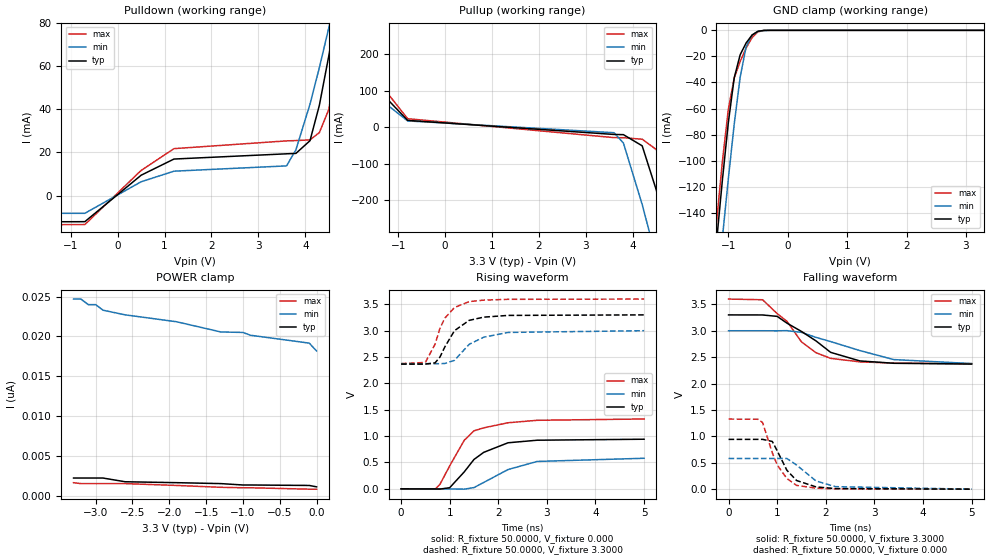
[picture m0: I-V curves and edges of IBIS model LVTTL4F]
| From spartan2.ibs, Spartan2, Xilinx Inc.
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|   Model LVTTL4F
[Model]   LVTTL4F
Model_type   I/O
Polarity   Non-Inverting
Enable   Active-Low
Vinl =   0.800V
Vinh =   2.000V
Vmeas =   1.4000V
Cref =  35.0000pF
Rref =   1.0000M
Vref =  0.000V
C_comp   6.5000pF   5.0000pF   8.0000pF
[Temperature Range]   27.0000   100.0000   0.000
[Voltage Range]   3.3000V   3.0000V   3.6000V
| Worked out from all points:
|   slope of the pulldown table from 0 to 0.495 V, typ, clamps not added: 52.7 ohm
|   slope of the pullup table from 0 to 0.495 V, typ, clamps not added: 72 ohm
|   GND clamp passes 1 mA (typ) near -0.51 V on its own axis
|   rising waveform, R_fixture 50.0000, V_fixture 0.000: 20-80 % time 649ps typ, 853ps min, 538ps max; typ from 0 V to 0.941 V
|   rising waveform, R_fixture 50.0000, V_fixture 3.3000: 20-80 % time 419ps typ, 526ps min, 353ps max; typ from 2.37 V to 3.3 V
|   falling waveform, R_fixture 50.0000, V_fixture 3.3000: 20-80 % time 914ps typ, 1.33ns min, 768ps max; typ from 3.3 V to 2.37 V
|   falling waveform, R_fixture 50.0000, V_fixture 0.000: 20-80 % time 386ps typ, 512ps min, 365ps max; typ from 0.943 V to 0.001 V
[Pulldown]
| voltage   I(typ)   I(min)   I(max)
-3.3V     -12.23mA   -8.171mA   -13.61mA
-700mV    -12.05mA   -8.171mA   -13.39mA
500mV     9.467mA    6.427mA    11.68mA
1.2V      16.95mA    11.33mA    21.76mA
3.6V      19.37mA    13.78mA    25.36mA
3.8V      19.56mA    21.23mA    25.5mA
4.1V      25.44mA    42.35mA    25.81mA
4.3V      41.86mA    59.27mA    29.21mA
4.5V      64.6mA     77.61mA    39.82mA
4.7V      89.71mA    97.03mA    64.96mA
4.9V      116.1mA    117.3mA    95.67mA
6.6V      348mA      295mA      376.7mA
[Pullup]
| voltage   I(typ)   I(min)   I(max)
-3.3V     354.4mA    271.9mA    429.9mA
-2.7V     272.8mA    207.8mA    331mA
-800mV    18.43mA    17.03mA    23.04mA
3.6V      -19.96mA   -15.22mA   -28.65mA
3.8V      -20.52mA   -43.41mA   -28.84mA
4.2V      -51mA      -211.2mA   -32.92mA
4.5V      -171.4mA   -357.8mA   -61.08mA
4.7V      -272mA     -457.9mA   -116mA
4.9V      -376.2mA   -559mA     -210.3mA
5.1V      -482.2mA   -660.7mA   -313.6mA
5.3V      -589.2mA   -762.8mA   -420.3mA
6.6V      -1.293A    -1.432A    -1.133A
[GND_clamp]
| voltage   I(typ)   I(min)   I(max)
-3.3V     -1.286A    -1.273A    -1.289A
-1.2V     -163.3mA   -206.7mA   -148.3mA
-1.1V     -115.2mA   -159.6mA   -101mA
-1V       -71.04mA   -114.2mA   -60.78mA
-900mV    -36.42mA   -71.86mA   -36.53mA
-800mV    -18.72mA   -35.86mA   -23.84mA
-700mV    -9.715mA   -12.62mA   -13.63mA
-600mV    -3.608mA   -3.649mA   -5.601mA
-500mV    -692.7uA   -854.2uA   -1.156mA
-400mV    -68.48uA   -138.7uA   -98.51uA
-300mV    -4.365uA   -16.73uA   -4.597uA
3.3V      1.164nA    19.44nA    698.5pA
[POWER_clamp]
| voltage   I(typ)   I(min)   I(max)
-3.3V     2.212nA    24.68nA    1.63nA
-3.2V     2.212nA    24.68nA    1.513nA
-3.1V     2.212nA    23.98nA    1.513nA
-3V       2.212nA    23.98nA    1.513nA
-2.9V     2.212nA    23.28nA    1.513nA
-2.6V     1.746nA    22.7nA     1.513nA
-1.9V     1.63nA     21.83nA    1.281nA
-1.3V     1.513nA    20.55nA    1.048nA
-1V       1.339nA    20.49nA    989.5pA
-900mV    1.339nA    20.14nA    989.5pA
-100mV    1.281nA    19.15nA    814.9pA
0V        1.106nA    18.16nA    814.9pA
[Ramp]
| variable   typ   min   max
dV/dt_r   0.5647/0.6500n   0.3480/0.8497n   0.7950/0.5579n
dV/dt_f   0.5586/0.9517n   0.3726/1.3252n   0.7338/0.7688n
R_load = 50.0000
[Rising Waveform]
R_fixture = 50.0000
V_fixture = 0.000
| time   V(typ)   V(min)   V(max)
0s        0V         0V         0V
700ps     -2.021mV   226.2uV    -4.415mV
800ps     -4.588mV   188uV      85.45mV
1ns       21.52mV    -1.672mV   434.2mV
1.3ns     321.5mV    -6.047mV   921.4mV
1.5ns     557.2mV    23.94mV    1.1V
1.7ns     692mV      121.2mV    1.157V
2.2ns     873.5mV    365.6mV    1.253V
2.8ns     922.2mV    519.7mV    1.3V
5ns       941.2mV    580mV      1.325V
[Rising Waveform]
R_fixture = 50.0000
V_fixture = 3.3000
V_fixture_min = 3.0000
V_fixture_max = 3.6000
| time   V(typ)   V(min)   V(max)
0s        2.365V     2.374V     2.375V
500ps     2.365V     2.374V     2.397V
700ps     2.39V      2.374V     2.744V
800ps     2.499V     2.374V     3.043V
900ps     2.691V     2.377V     3.237V
1.1ns     3V         2.437V     3.439V
1.4ns     3.195V     2.74V      3.551V
1.7ns     3.256V     2.876V     3.579V
2.2ns     3.289V     2.966V     3.594V
5ns       3.299V     2.999V     3.599V
[Falling Waveform]
R_fixture = 50.0000
V_fixture = 3.3000
V_fixture_min = 3.0000
V_fixture_max = 3.6000
| time   V(typ)   V(min)   V(max)
0s        3.3V       3V         3.6V
700ps     3.299V     3V         3.587V
1ns       3.272V     2.999V     3.325V
1.2ns     3.145V     3.002V     3.18V
1.5ns     2.987V     2.97V      2.789V
1.8ns     2.807V     2.874V     2.584V
2.1ns     2.591V     2.795V     2.477V
2.7ns     2.429V     2.625V     2.411V
3.4ns     2.384V     2.454V     2.388V
5ns       2.369V     2.379V     2.377V
[Falling Waveform]
R_fixture = 50.0000
V_fixture = 0.000
| time   V(typ)   V(min)   V(max)
0s        943.3mV    581.6mV    1.327V
600ps     943.4mV    581.6mV    1.325V
700ps     943.7mV    581.6mV    1.262V
900ps     903.3mV    581.6mV    689.3mV
1ns       728.3mV    581.8mV    460.1mV
1.2ns     357.9mV    581.3mV    201.4mV
1.4ns     164mV      456.6mV    71.6mV
1.8ns     43.47mV    155.2mV    18.74mV
2.2ns     11.27mV    47.74mV    7.191mV
5ns       636.3uV    446.4uV    717.8uV
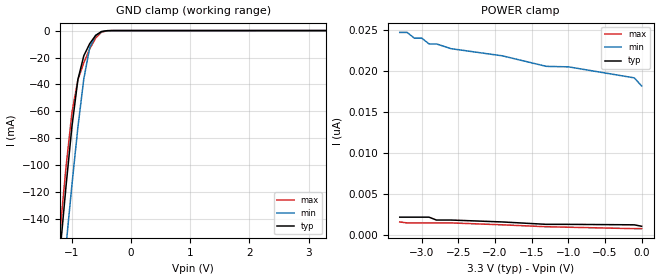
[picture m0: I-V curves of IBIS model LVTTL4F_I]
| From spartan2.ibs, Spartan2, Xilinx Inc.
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|   Model LVTTL4F_I
[Model]   LVTTL4F_I
Model_type   Input
Polarity   Non-Inverting
Vinl =   0.800V
Vinh =   2.000V
C_comp   6.5000pF   5.0000pF   8.0000pF
[Temperature Range]   27.0000   100.0000   0.000
[Voltage Range]   3.3000V   3.0000V   3.6000V
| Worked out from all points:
|   GND clamp passes 1 mA (typ) near -0.51 V on its own axis
[GND_clamp]
| voltage   I(typ)   I(min)   I(max)
-3.3V     -1.286A    -1.273A    -1.289A
-1.2V     -163.3mA   -206.7mA   -148.3mA
-1.1V     -115.2mA   -159.6mA   -101mA
-1V       -71.04mA   -114.2mA   -60.78mA
-900mV    -36.42mA   -71.86mA   -36.53mA
-800mV    -18.72mA   -35.86mA   -23.84mA
-700mV    -9.715mA   -12.62mA   -13.63mA
-600mV    -3.608mA   -3.649mA   -5.601mA
-500mV    -692.7uA   -854.2uA   -1.156mA
-400mV    -68.48uA   -138.7uA   -98.51uA
-300mV    -4.365uA   -16.73uA   -4.597uA
3.3V      1.164nA    19.44nA    698.5pA
[POWER_clamp]
| voltage   I(typ)   I(min)   I(max)
-3.3V     2.212nA    24.68nA    1.63nA
-3.2V     2.212nA    24.68nA    1.513nA
-3.1V     2.212nA    23.98nA    1.513nA
-3V       2.212nA    23.98nA    1.513nA
-2.9V     2.212nA    23.28nA    1.513nA
-2.8V     1.863nA    23.28nA    1.513nA
-2.6V     1.863nA    22.7nA     1.513nA
-1.9V     1.63nA     21.83nA    1.281nA
-1.3V     1.339nA    20.55nA    1.048nA
-1V       1.339nA    20.49nA    989.5pA
-100mV    1.281nA    19.15nA    814.9pA
0V        1.106nA    18.16nA    814.9pA
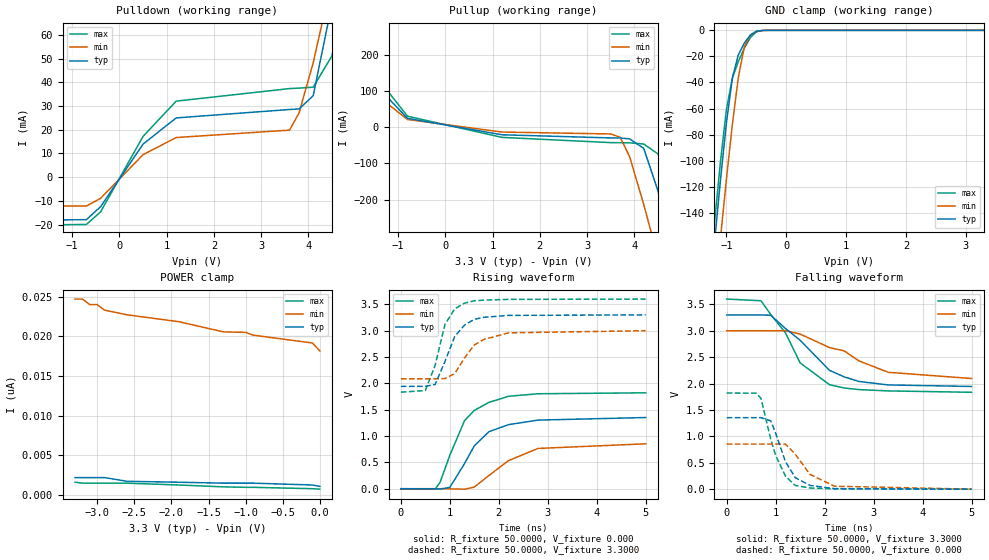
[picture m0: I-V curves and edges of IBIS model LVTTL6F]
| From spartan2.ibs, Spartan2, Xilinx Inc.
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|   Model LVTTL6F
[Model]   LVTTL6F
Model_type   I/O
Polarity   Non-Inverting
Enable   Active-Low
Vinl =   0.800V
Vinh =   2.000V
Vmeas =   1.4000V
Cref =  35.0000pF
Rref =   1.0000M
Vref =  0.000V
C_comp   6.5000pF   5.0000pF   8.0000pF
[Temperature Range]   27.0000   100.0000   0.000
[Voltage Range]   3.3000V   3.0000V   3.6000V
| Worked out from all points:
|   slope of the pulldown table from 0 to 0.495 V, typ, clamps not added: 35.8 ohm
|   slope of the pullup table from 0 to 0.495 V, typ, clamps not added: 48 ohm
|   GND clamp passes 1 mA (typ) near -0.51 V on its own axis
|   rising waveform, R_fixture 50.0000, V_fixture 0.000: 20-80 % time 637ps typ, 848ps min, 572ps max; typ from 0 V to 1.35 V
|   rising waveform, R_fixture 50.0000, V_fixture 3.3000: 20-80 % time 381ps typ, 505ps min, 322ps max; typ from 1.94 V to 3.3 V
|   falling waveform, R_fixture 50.0000, V_fixture 3.3000: 20-80 % time 938ps typ, 1.32ns min, 791ps max; typ from 3.3 V to 1.95 V
|   falling waveform, R_fixture 50.0000, V_fixture 0.000: 20-80 % time 371ps typ, 475ps min, 357ps max; typ from 1.35 V to 0.001 V
[Pulldown]
| voltage   I(typ)   I(min)   I(max)
-3.3V     -18.29mA   -12.15mA   -20.46mA
-700mV    -17.9mA    -12.15mA   -19.91mA
-400mV    -12.43mA   -8.91mA    -14.62mA
500mV     13.96mA    9.497mA    17.21mA
1.2V      24.98mA    16.71mA    32.05mA
3.6V      28.53mA    19.84mA    37.34mA
3.8V      28.75mA    27.06mA    37.54mA
4.1V      34.3mA     48.19mA    37.92mA
4.5V      73.34mA    83.53mA    51.22mA
4.7V      98.49mA    103mA      76.31mA
4.9V      124.9mA    123.2mA    107.1mA
6.6V      356.8mA    300.9mA    388.1mA
[Pullup]
| voltage   I(typ)   I(min)   I(max)
-3.3V     367mA      281.8mA    444.6mA
-2.7V     284.5mA    216.8mA    344.6mA
-800mV    24.26mA    21.1mA     30.17mA
1.2V      -21.09mA   -13.54mA   -28.27mA
3.5V      -29.77mA   -18.84mA   -42.7mA
3.7V      -29.99mA   -27.95mA   -43mA
3.9V      -32.42mA   -80.94mA   -43.28mA
4.2V      -58.74mA   -213.5mA   -46.66mA
4.5V      -175.5mA   -359.9mA   -73.69mA
4.9V      -379.7mA   -561mA     -216mA
5.1V      -485.7mA   -662.7mA   -318.8mA
6.6V      -1.296A    -1.434A    -1.138A
[GND_clamp]
| voltage   I(typ)   I(min)   I(max)
-3.3V     -1.286A    -1.273A    -1.289A
-1.2V     -163.3mA   -206.7mA   -148.3mA
-1.1V     -115.2mA   -159.6mA   -101mA
-1V       -71.04mA   -114.2mA   -60.78mA
-900mV    -36.42mA   -71.86mA   -36.53mA
-800mV    -18.72mA   -35.86mA   -23.84mA
-700mV    -9.715mA   -12.62mA   -13.63mA
-600mV    -3.608mA   -3.649mA   -5.601mA
-500mV    -692.7uA   -854.2uA   -1.156mA
-400mV    -68.48uA   -138.7uA   -98.51uA
-300mV    -4.365uA   -16.73uA   -4.597uA
3.3V      1.106nA    19.38nA    756.7pA
[POWER_clamp]
| voltage   I(typ)   I(min)   I(max)
-3.3V     2.212nA    24.68nA    1.63nA
-3.2V     2.212nA    24.68nA    1.513nA
-3.1V     2.212nA    23.98nA    1.513nA
-3V       2.212nA    23.98nA    1.513nA
-2.9V     2.212nA    23.28nA    1.513nA
-2.6V     1.746nA    22.7nA     1.513nA
-1.9V     1.63nA     21.83nA    1.281nA
-1.3V     1.513nA    20.55nA    1.048nA
-1V       1.513nA    20.49nA    989.5pA
-900mV    1.513nA    20.14nA    989.5pA
-100mV    1.281nA    19.15nA    814.9pA
0V        1.106nA    18.16nA    756.7pA
[Ramp]
| variable   typ   min   max
dV/dt_r   0.8106/0.6383n   0.5113/0.8456n   1.0920/0.5977n
dV/dt_f   0.8130/0.9718n   0.5424/1.3196n   1.0590/0.7913n
R_load = 50.0000
[Rising Waveform]
R_fixture = 50.0000
V_fixture = 0.000
| time   V(typ)   V(min)   V(max)
0s        0V         0V         0V
700ps     -2.548mV   477.9uV    -7.13mV
800ps     -6.399mV   465uV      119.4mV
1ns       24.33mV    -2.208mV   634mV
1.3ns     476.9mV    -8.459mV   1.291V
1.5ns     813.5mV    30.35mV    1.486V
1.8ns     1.083V     252.1mV    1.639V
2.2ns     1.216V     533.5mV    1.754V
2.8ns     1.302V     764.5mV    1.802V
5ns       1.351V     852.1mV    1.82V
[Rising Waveform]
R_fixture = 50.0000
V_fixture = 3.3000
V_fixture_min = 3.0000
V_fixture_max = 3.6000
| time   V(typ)   V(min)   V(max)
0s        1.942V     2.086V     1.832V
500ps     1.943V     2.086V     1.863V
700ps     1.978V     2.086V     2.342V
900ps     2.413V     2.09V      3.116V
1.1ns     2.889V     2.184V     3.413V
1.3ns     3.104V     2.481V     3.522V
1.5ns     3.216V     2.728V     3.566V
1.7ns     3.253V     2.835V     3.579V
2.2ns     3.289V     2.958V     3.593V
5ns       3.299V     2.999V     3.599V
[Falling Waveform]
R_fixture = 50.0000
V_fixture = 3.3000
V_fixture_min = 3.0000
V_fixture_max = 3.6000
| time   V(typ)   V(min)   V(max)
0s        3.3V       3V         3.6V
700ps     3.299V     3V         3.568V
900ps     3.293V     3V         3.307V
1.2ns     3.043V     3.002V     2.962V
1.5ns     2.82V      2.937V     2.392V
2.1ns     2.25V      2.681V     1.978V
2.4ns     2.127V     2.619V     1.916V
2.7ns     2.04V      2.43V      1.886V
3.3ns     1.974V     2.213V     1.861V
5ns       1.945V     2.096V     1.835V
[Falling Waveform]
R_fixture = 50.0000
V_fixture = 0.000
| time   V(typ)   V(min)   V(max)
0s        1.354V     854.4mV    1.821V
600ps     1.354V     854.3mV    1.818V
700ps     1.354V     854.4mV    1.722V
900ps     1.294V     854.4mV    943.9mV
1ns       1.06V      854.6mV    638.2mV
1.2ns     521.9mV    853.2mV    247.6mV
1.4ns     219.7mV    664.2mV    70.24mV
1.7ns     71.28mV    280.8mV    22.14mV
2.2ns     10.91mV    56.52mV    6.667mV
5ns       677.6uV    604.3uV    703.3uV
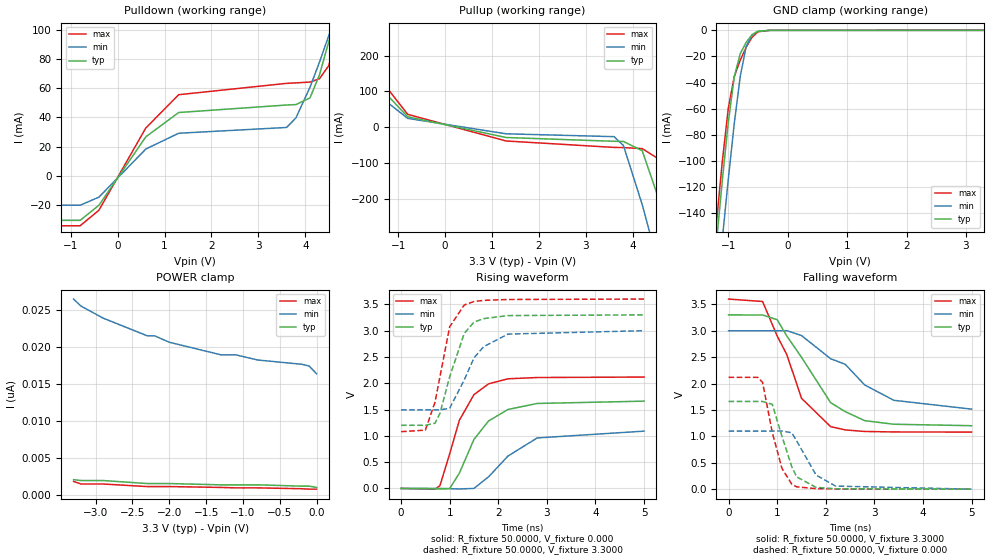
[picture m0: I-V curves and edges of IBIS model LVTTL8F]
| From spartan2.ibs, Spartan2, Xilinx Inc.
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|   Model LVTTL8F
[Model]   LVTTL8F
Model_type   I/O
Polarity   Non-Inverting
Enable   Active-Low
Vinl =   0.800V
Vinh =   2.000V
Vmeas =   1.4000V
Cref =  35.0000pF
Rref =   1.0000M
Vref =  0.000V
C_comp   6.5000pF   5.0000pF   8.0000pF
[Temperature Range]   27.0000   100.0000   0.000
[Voltage Range]   3.3000V   3.0000V   3.6000V
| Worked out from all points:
|   slope of the pulldown table from 0 to 0.495 V, typ, clamps not added: 21.7 ohm
|   slope of the pullup table from 0 to 0.495 V, typ, clamps not added: 37.4 ohm
|   GND clamp passes 1 mA (typ) near -0.51 V on its own axis
|   rising waveform, R_fixture 50.0000, V_fixture 0.000: 20-80 % time 658ps typ, 816ps min, 496ps max; typ from 0 V to 1.66 V
|   rising waveform, R_fixture 50.0000, V_fixture 3.3000: 20-80 % time 405ps typ, 509ps min, 328ps max; typ from 1.2 V to 3.3 V
|   falling waveform, R_fixture 50.0000, V_fixture 3.3000: 20-80 % time 910ps typ, 1.33ns min, 701ps max; typ from 3.3 V to 1.2 V
|   falling waveform, R_fixture 50.0000, V_fixture 0.000: 20-80 % time 338ps typ, 441ps min, 314ps max; typ from 1.66 V to 0.001 V
[Pulldown]
| voltage   I(typ)   I(min)   I(max)
-3.3V     -30.59mA   -20.24mA   -34.35mA
-800mV    -30.59mA   -20.24mA   -34.32mA
-400mV    -20.27mA   -14.69mA   -23.66mA
600mV     26.67mA    18.3mA     32.74mA
1.3V      43.34mA    29.13mA    55.56mA
3.6V      48.49mA    33.09mA    63.34mA
3.8V      48.79mA    39.63mA    63.67mA
4.1V      53.36mA    60.68mA    64.22mA
4.3V      68.97mA    77.68mA    66.46mA
4.5V      91.81mA    96.06mA    75.48mA
4.7V      116.9mA    115.5mA    100.2mA
6.6V      374.6mA    313mA      411.1mA
[Pullup]
| voltage   I(typ)   I(min)   I(max)
-3.3V     377.1mA    289.5mA    456.1mA
-2.5V     265.1mA    201.1mA    320.9mA
-800mV    29.02mA    24.47mA    35.82mA
1.3V      -28.95mA   -18.62mA   -38.67mA
3.6V      -39.57mA   -26.6mA    -56.67mA
3.8V      -40.06mA   -51.24mA   -57.06mA
4.2V      -65.76mA   -216.1mA   -59.97mA
4.5V      -180mA     -362.3mA   -84.67mA
4.7V      -279.7mA   -462.3mA   -131.8mA
4.9V      -383.6mA   -563.4mA   -223.1mA
5.1V      -489.5mA   -665.1mA   -325mA
6.6V      -1.3A      -1.437A    -1.143A
[GND_clamp]
| voltage   I(typ)   I(min)   I(max)
-3.3V     -1.286A    -1.273A    -1.29A
-1.3V     -213.2mA   -255.1mA   -198mA
-1.2V     -163mA     -206.8mA   -147.7mA
-1.1V     -114.8mA   -159.6mA   -100.3mA
-1V       -70.57mA   -114.1mA   -59.86mA
-900mV    -35.79mA   -71.75mA   -35.46mA
-800mV    -18.04mA   -35.69mA   -22.98mA
-700mV    -9.256mA   -12.38mA   -13.06mA
-600mV    -3.388mA   -3.468mA   -5.299mA
-500mV    -637.4uA   -792.4uA   -1.07mA
-300mV    -3.973uA   -15.32uA   -4.185uA
3.3V      1.048nA    17.64nA    698.5pA
[POWER_clamp]
| voltage   I(typ)   I(min)   I(max)
-3.3V     2.095nA    26.43nA    1.863nA
-3.2V     1.979nA    25.49nA    1.513nA
-2.9V     1.979nA    23.87nA    1.513nA
-2.3V     1.572nA    21.48nA    1.164nA
-2.2V     1.572nA    21.48nA    1.164nA
-2V       1.572nA    20.61nA    1.164nA
-1.3V     1.397nA    18.92nA    1.048nA
-1.1V     1.397nA    18.92nA    989.5pA
-800mV    1.397nA    18.22nA    989.5pA
-200mV    1.222nA    17.64nA    873.1pA
-100mV    1.222nA    17.4nA     814.9pA
0V        1.048nA    16.36nA    814.9pA
[Ramp]
| variable   typ   min   max
dV/dt_r   0.9954/0.6562n   0.6534/0.8177n   1.2702/0.5188n
dV/dt_f   1.2588/0.9349n   0.8904/1.3360n   1.5114/0.7027n
R_load = 50.0000
[Rising Waveform]
R_fixture = 50.0000
V_fixture = 0.000
| time   V(typ)   V(min)   V(max)
0s        0V         0V         0V
700ps     -3.523mV   474.9uV    -13.49mV
800ps     -8.549mV   441.1uV    53.62mV
1ns       -3.398mV   -3.191mV   657.2mV
1.2ns     291.8mV    -10.29mV   1.297V
1.5ns     932.3mV    594.8uV    1.783V
1.8ns     1.282V     220.5mV    1.988V
2.2ns     1.501V     616.2mV    2.084V
2.8ns     1.615V     959.9mV    2.108V
5ns       1.659V     1.089V     2.117V
[Rising Waveform]
R_fixture = 50.0000
V_fixture = 3.3000
V_fixture_min = 3.0000
V_fixture_max = 3.6000
| time   V(typ)   V(min)   V(max)
0s        1.2V       1.493V     1.079V
500ps     1.2V       1.493V     1.108V
700ps     1.24V      1.493V     1.645V
800ps     1.426V     1.493V     2.122V
1ns       2.122V     1.524V     3.072V
1.3ns     2.947V     2.061V     3.487V
1.5ns     3.161V     2.481V     3.553V
1.7ns     3.227V     2.695V     3.574V
2.2ns     3.285V     2.933V     3.591V
5ns       3.299V     2.998V     3.599V
[Falling Waveform]
R_fixture = 50.0000
V_fixture = 3.3000
V_fixture_min = 3.0000
V_fixture_max = 3.6000
| time   V(typ)   V(min)   V(max)
0s        3.3V       3V         3.6V
700ps     3.299V     3V         3.554V
1ns       3.209V     2.999V     2.901V
1.2ns     2.898V     3.002V     2.546V
1.5ns     2.499V     2.91V      1.722V
2.1ns     1.639V     2.47V      1.184V
2.4ns     1.469V     2.365V     1.123V
2.8ns     1.298V     1.974V     1.093V
3.4ns     1.23V      1.683V     1.084V
5ns       1.202V     1.516V     1.081V
[Falling Waveform]
R_fixture = 50.0000
V_fixture = 0.000
| time   V(typ)   V(min)   V(max)
0s        1.661V     1.1V       2.118V
600ps     1.661V     1.1V       2.118V
700ps     1.661V     1.1V       2.023V
900ps     1.606V     1.1V       1.072V
1.1ns     997.6mV    1.101V     390.8mV
1.3ns     427mV      1.07V      97.05mV
1.4ns     233.5mV    915.8mV    44.14mV
1.8ns     34.79mV    268.1mV    11.02mV
2.2ns     7.949mV    58.66mV    4.811mV
5ns       542.7uV    608.4uV    549.4uV
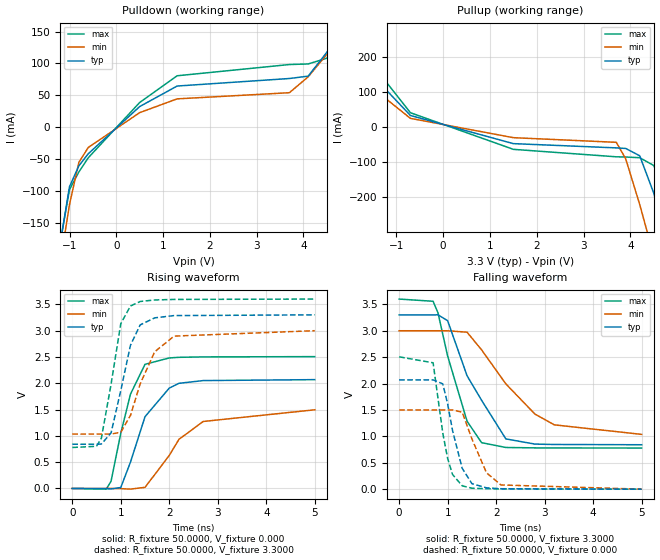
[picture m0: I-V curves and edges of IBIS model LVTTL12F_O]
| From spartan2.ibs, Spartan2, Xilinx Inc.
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|   Model LVTTL12F_O
[Model]   LVTTL12F_O
Model_type   Output
Polarity   Non-Inverting
Vmeas =   1.4000V
Cref =  35.0000pF
Rref =   1.0000M
Vref =  0.000V
C_comp   6.5000pF   5.0000pF   8.0000pF
[Temperature Range]   27.0000   100.0000   0.000
[Voltage Range]   3.3000V   3.0000V   3.6000V
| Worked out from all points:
|   slope of the pulldown table from 0 to 0.495 V, typ, clamps not added: 15.4 ohm
|   slope of the pullup table from 0 to 0.495 V, typ, clamps not added: 25.2 ohm
|   rising waveform, R_fixture 50.0000, V_fixture 0.000: 20-80 % time 556ps typ, 797ps min, 400ps max; typ from 0 V to 2.07 V
|   rising waveform, R_fixture 50.0000, V_fixture 3.3000: 20-80 % time 372ps typ, 492ps min, 288ps max; typ from 0.84 V to 3.3 V
|   falling waveform, R_fixture 50.0000, V_fixture 3.3000: 20-80 % time 727ps typ, 1.07ns min, 508ps max; typ from 3.3 V to 0.841 V
|   falling waveform, R_fixture 50.0000, V_fixture 0.000: 20-80 % time 305ps typ, 397ps min, 266ps max; typ from 2.07 V to 0 V
[Pulldown]
| voltage   I(typ)   I(min)   I(max)
-3.3V     -1.282A    -1.27A     -1.284A
-1.5V     -318.7mA   -354mA     -306.2mA
-1V       -93.5mA    -121.5mA   -98.07mA
-800mV    -60.84mA   -55.35mA   -70.38mA
-600mV    -41.86mA   -32.01mA   -48.2mA
500mV     32.35mA    22.81mA    38.75mA
1.3V      64.57mA    44.42mA    80.71mA
3.7V      76.41mA    54.11mA    98.37mA
4.1V      80.11mA    79.08mA    99.25mA
4.5V      117.6mA    114.4mA    108.3mA
4.9V      168.6mA    153.8mA    162.6mA
6.6V      399mA      330.4mA    441.4mA
[Pullup]
| voltage   I(typ)   I(min)   I(max)
-3.3V     401.3mA    308.2mA    484mA
-2.9V     344.8mA    263.9mA    415.5mA
-2.5V     286.5mA    217.5mA    345.7mA
-700mV    33.24mA    24.98mA    41.08mA
1.5V      -47.01mA   -30.01mA   -63.27mA
3.7V      -59.11mA   -43.28mA   -84.54mA
3.9V      -60.68mA   -90.11mA   -85.1mA
4.2V      -81.62mA   -220.4mA   -87.14mA
4.5V      -188mA     -366.4mA   -109.3mA
4.9V      -390.3mA   -567.4mA   -234.7mA
5.1V      -496.1mA   -669.1mA   -335.2mA
6.6V      -1.307A    -1.441A    -1.153A
[Ramp]
| variable   typ   min   max
dV/dt_r   1.2408/0.5535n   0.8970/0.7922n   1.5030/0.3954n
dV/dt_f   1.4752/0.7257n   1.1772/1.1183n   1.6925/0.5243n
R_load = 50.0000
[Rising Waveform]
R_fixture = 50.0000
V_fixture = 0.000
| time   V(typ)   V(min)   V(max)
0s        0V         0V         0V
700ps     -3.771mV   692.4uV    -13.4mV
800ps     -9.635mV   799.2uV    138.3mV
1ns       17.96mV    -3.585mV   1.048V
1.2ns     500.5mV    -12.31mV   1.792V
1.5ns     1.364V     21.02mV    2.359V
2ns       1.907V     627.7mV    2.48V
2.2ns     1.998V     933.5mV    2.492V
2.7ns     2.05V      1.273V     2.5V
5ns       2.068V     1.495V     2.505V
[Rising Waveform]
R_fixture = 50.0000
V_fixture = 3.3000
V_fixture_min = 3.0000
V_fixture_max = 3.6000
| time   V(typ)   V(min)   V(max)
0s        840.3mV    1.034V     778.4mV
500ps     841.4mV    1.034V     801.3mV
600ps     844.4mV    1.034V     955.5mV
800ps     1.055V     1.034V     1.98V
1ns       1.861V     1.067V     3.131V
1.2ns     2.721V     1.388V     3.467V
1.4ns     3.108V     1.987V     3.553V
1.7ns     3.242V     2.598V     3.582V
2.1ns     3.285V     2.895V     3.592V
5ns       3.299V     2.998V     3.599V
[Falling Waveform]
R_fixture = 50.0000
V_fixture = 3.3000
V_fixture_min = 3.0000
V_fixture_max = 3.6000
| time   V(typ)   V(min)   V(max)
0s        3.3V       3V         3.6V
700ps     3.299V     3V         3.558V
800ps     3.303V     3V         3.341V
1ns       3.19V      2.999V     2.521V
1.4ns     2.149V     2.973V     1.288V
1.7ns     1.683V     2.638V     880.4mV
2.2ns     952.2mV    1.994V     789.8mV
2.8ns     853.7mV    1.422V     782.3mV
3.2ns     846.6mV    1.218V     780.9mV
5ns       841.4mV    1.038V     779.2mV
[Falling Waveform]
R_fixture = 50.0000
V_fixture = 0.000
| time   V(typ)   V(min)   V(max)
0s        2.07V      1.5V       2.506V
700ps     2.07V      1.5V       2.393V
900ps     1.994V     1.5V       1.06V
1ns       1.615V     1.5V       581mV
1.1ns     1.113V     1.501V     280.2mV
1.3ns     395.3mV    1.458V     63.91mV
1.5ns     105.3mV    953.5mV    17.9mV
1.8ns     26.06mV    311.6mV    8.619mV
2.1ns     8.631mV    80.09mV    4.709mV
5ns       466uV      547.1uV    485uV
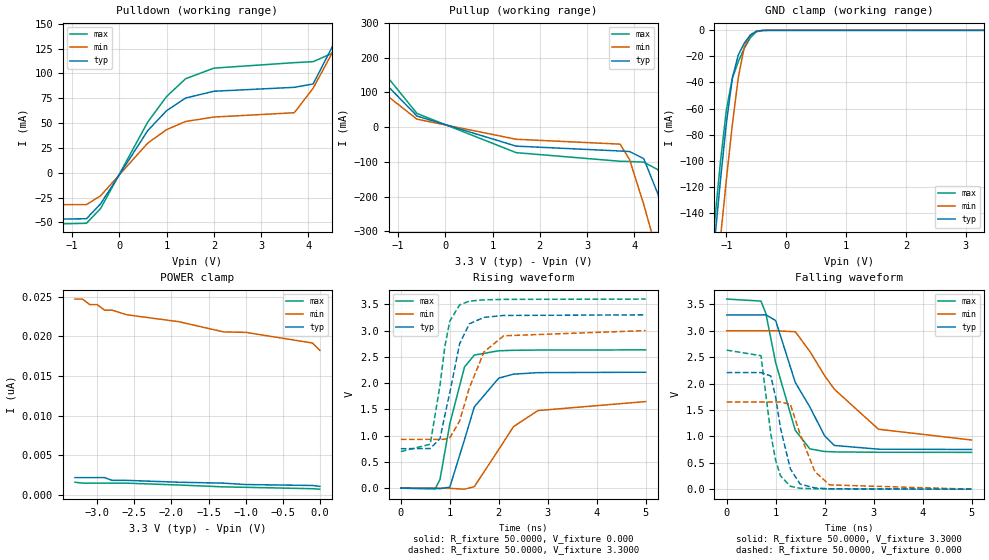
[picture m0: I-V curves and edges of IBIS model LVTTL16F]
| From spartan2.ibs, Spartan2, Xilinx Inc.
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|   Model LVTTL16F
[Model]   LVTTL16F
Model_type   I/O
Polarity   Non-Inverting
Enable   Active-Low
Vinl =   0.800V
Vinh =   2.000V
Vmeas =   1.4000V
Cref =  35.0000pF
Rref =   1.0000M
Vref =  0.000V
C_comp   6.5000pF   5.0000pF   8.0000pF
[Temperature Range]   27.0000   100.0000   0.000
[Voltage Range]   3.3000V   3.0000V   3.6000V
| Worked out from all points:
|   slope of the pulldown table from 0 to 0.495 V, typ, clamps not added: 13.7 ohm
|   slope of the pullup table from 0 to 0.495 V, typ, clamps not added: 21.7 ohm
|   GND clamp passes 1 mA (typ) near -0.51 V on its own axis
|   rising waveform, R_fixture 50.0000, V_fixture 0.000: 20-80 % time 500ps typ, 772ps min, 357ps max; typ from 0 V to 2.21 V
|   rising waveform, R_fixture 50.0000, V_fixture 3.3000: 20-80 % time 348ps typ, 474ps min, 266ps max; typ from 0.751 V to 3.3 V
|   falling waveform, R_fixture 50.0000, V_fixture 3.3000: 20-80 % time 696ps typ, 1.06ns min, 490ps max; typ from 3.3 V to 0.752 V
|   falling waveform, R_fixture 50.0000, V_fixture 0.000: 20-80 % time 289ps typ, 392ps min, 245ps max; typ from 2.21 V to 0 V
[Pulldown]
| voltage   I(typ)   I(min)   I(max)
-3.3V     -48.03mA   -32.17mA   -53.62mA
-700mV    -46.38mA   -32.17mA   -50.97mA
-400mV    -31.4mA    -23.23mA   -36.15mA
600mV     42.55mA    29.94mA    51.16mA
1V        62.63mA    43.47mA    76.94mA
1.4V      75.27mA    51.64mA    94.7mA
2V        82.09mA    56.09mA    105.4mA
3.7V      86.04mA    60.44mA    110.9mA
4.1V      89.48mA    85.22mA    111.9mA
4.5V      126.6mA    120.5mA    120.3mA
4.9V      177.6mA    159.9mA    174.2mA
6.6V      407.8mA    336.3mA    452.6mA
[Pullup]
| voltage   I(typ)   I(min)   I(max)
-3.3V     413.8mA    317.9mA    498.5mA
-2.9V     356.6mA    273mA      429.3mA
-2.5V     297.6mA    226.1mA    358.6mA
-600mV    31.98mA    22.96mA    39.44mA
1.5V      -54.66mA   -34.94mA   -73.46mA
3.7V      -68.75mA   -48.9mA    -98.25mA
3.9V      -70.27mA   -93.43mA   -98.9mA
4.2V      -90.62mA   -222.7mA   -100.8mA
4.5V      -192.3mA   -368.3mA   -122.6mA
4.9V      -393.7mA   -569.2mA   -241mA
5.1V      -499.3mA   -670.9mA   -340.5mA
6.6V      -1.31A     -1.442A    -1.157A
[GND_clamp]
| voltage   I(typ)   I(min)   I(max)
-3.3V     -1.286A    -1.273A    -1.289A
-1.2V     -163.3mA   -206.7mA   -148.3mA
-1.1V     -115.2mA   -159.6mA   -101mA
-1V       -71.04mA   -114.2mA   -60.78mA
-900mV    -36.42mA   -71.86mA   -36.53mA
-800mV    -18.72mA   -35.86mA   -23.84mA
-700mV    -9.715mA   -12.62mA   -13.63mA
-600mV    -3.608mA   -3.649mA   -5.602mA
-500mV    -692.7uA   -854.2uA   -1.156mA
-400mV    -68.48uA   -138.7uA   -98.54uA
-300mV    -4.365uA   -16.73uA   -4.627uA
3.3V      1.106nA    19.38nA    40.4nA
[POWER_clamp]
| voltage   I(typ)   I(min)   I(max)
-3.3V     2.212nA    24.68nA    1.63nA
-3.2V     2.212nA    24.68nA    1.513nA
-3.1V     2.212nA    23.98nA    1.513nA
-3V       2.212nA    23.98nA    1.513nA
-2.9V     2.212nA    23.28nA    1.513nA
-2.8V     1.863nA    23.28nA    1.513nA
-2.6V     1.863nA    22.7nA     1.513nA
-1.9V     1.63nA     21.83nA    1.281nA
-1.3V     1.513nA    20.55nA    1.048nA
-1V       1.339nA    20.49nA    989.5pA
-100mV    1.222nA    19.15nA    814.9pA
0V        1.106nA    18.22nA    756.7pA
[Ramp]
| variable   typ   min   max
dV/dt_r   1.3242/0.4985n   0.9888/0.7729n   1.5792/0.3516n
dV/dt_f   1.5287/0.6938n   1.2413/1.0975n   1.7416/0.4965n
R_load = 50.0000
[Rising Waveform]
R_fixture = 50.0000
V_fixture = 0.000
| time   V(typ)   V(min)   V(max)
0s        0V         0V         0V
700ps     -3.795mV   862.2uV    -13.55mV
800ps     -9.498mV   979.2uV    167.9mV
1ns       20.18mV    -3.712mV   1.226V
1.3ns     923.5mV    -18.43mV   2.307V
1.5ns     1.546V     29.14mV    2.533V
2ns       2.095V     737.9mV    2.615V
2.3ns     2.17V      1.171V     2.624V
2.8ns     2.199V     1.477V     2.629V
5ns       2.207V     1.648V     2.632V
[Rising Waveform]
R_fixture = 50.0000
V_fixture = 3.3000
V_fixture_min = 3.0000
V_fixture_max = 3.6000
| time   V(typ)   V(min)   V(max)
0s        751.2mV    928.2mV    696.8mV
600ps     755.2mV    928.8mV    836.4mV
800ps     943.5mV    928.5mV    1.963V
900ps     1.393V     932.2mV    2.704V
1ns       1.821V     959.1mV    3.179V
1.2ns     2.748V     1.276V     3.488V
1.4ns     3.129V     1.913V     3.56V
1.7ns     3.251V     2.595V     3.584V
2.1ns     3.287V     2.9V       3.593V
5ns       3.299V     2.999V     3.599V
[Falling Waveform]
R_fixture = 50.0000
V_fixture = 3.3000
V_fixture_min = 3.0000
V_fixture_max = 3.6000
| time   V(typ)   V(min)   V(max)
0s        3.3V       3V         3.6V
700ps     3.299V     3V         3.562V
800ps     3.303V     3V         3.329V
1ns       3.193V     2.999V     2.395V
1.4ns     2.023V     2.981V     1.116V
1.7ns     1.554V     2.608V     761.8mV
2ns       1.01V      2.148V     714.3mV
2.2ns     828.5mV    1.892V     706mV
3.1ns     757.3mV    1.135V     699.1mV
5ns       752.1mV    931.2mV    697.4mV
[Falling Waveform]
R_fixture = 50.0000
V_fixture = 0.000
| time   V(typ)   V(min)   V(max)
0s        2.208V     1.651V     2.633V
700ps     2.208V     1.651V     2.528V
900ps     2.144V     1.65V      1.05V
1ns       1.74V      1.651V     545.6mV
1.1ns     1.151V     1.651V     251.9mV
1.3ns     385.6mV    1.607V     55.11mV
1.5ns     96.7mV     1.042V     16.4mV
1.8ns     23.75mV    334.2mV    8.086mV
2.1ns     8.195mV    81.18mV    4.432mV
5ns       477.8uV    527.6uV    435.5uV
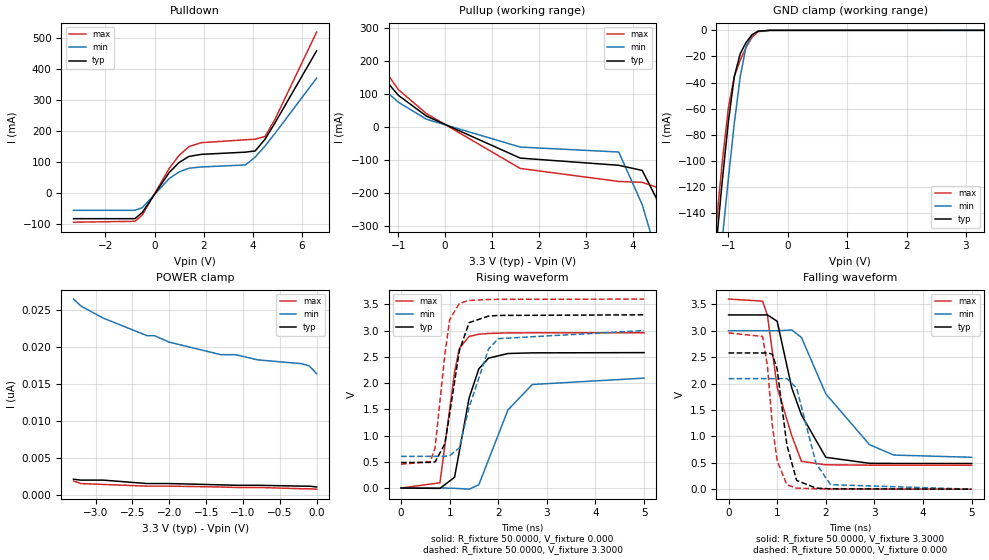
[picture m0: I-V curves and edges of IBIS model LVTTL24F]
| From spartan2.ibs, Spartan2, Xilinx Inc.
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|   Model LVTTL24F
[Model]   LVTTL24F
Model_type   I/O
Polarity   Non-Inverting
Enable   Active-Low
Vinl =   0.800V
Vinh =   2.000V
Vmeas =   1.4000V
Cref =  35.0000pF
Rref =   1.0000M
Vref =  0.000V
C_comp   6.5000pF   5.0000pF   8.0000pF
[Temperature Range]   27.0000   100.0000   0.000
[Voltage Range]   3.3000V   3.0000V   3.6000V
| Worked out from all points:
|   slope of the pulldown table from 0 to 0.495 V, typ, clamps not added: 8.65 ohm
|   slope of the pullup table from 0 to 0.495 V, typ, clamps not added: 13.4 ohm
|   GND clamp passes 1 mA (typ) near -0.51 V on its own axis
|   rising waveform, R_fixture 50.0000, V_fixture 0.000: 20-80 % time 335ps typ, 609ps min, 264ps max; typ from 0 V to 2.58 V
|   rising waveform, R_fixture 50.0000, V_fixture 3.3000: 20-80 % time 297ps typ, 440ps min, 225ps max; typ from 0.486 V to 3.3 V
|   falling waveform, R_fixture 50.0000, V_fixture 3.3000: 20-80 % time 618ps typ, 1.04ns min, 425ps max; typ from 3.3 V to 0.486 V
|   falling waveform, R_fixture 50.0000, V_fixture 0.000: 20-80 % time 251ps typ, 371ps min, 198ps max; typ from 2.58 V to 0 V
[Pulldown]
| voltage   I(typ)   I(min)   I(max)
-3.3V     -81.51mA   -54.57mA   -92.84mA
-800mV    -81.51mA   -54.57mA   -90.02mA
-500mV    -61.52mA   -46.16mA   -69.96mA
600mV     67.49mA    47.78mA    80.85mA
1V        99.44mA    69.02mA    122.2mA
1.4V      118.8mA    80.89mA    150.5mA
1.9V      125.5mA    84.94mA    163mA
3.7V      132.6mA    91.36mA    172.5mA
4.1V      136.6mA    116.8mA    174.3mA
4.5V      174.4mA    152.6mA    183.2mA
4.9V      226mA      192.5mA    237.8mA
6.6V      458.7mA    370.8mA    519.1mA
[Pullup]
| voltage   I(typ)   I(min)   I(max)
-3.3V     469.9mA    361.3mA    563.1mA
-2.7V     378.5mA    289.2mA    453mA
-2.3V     314.1mA    238.4mA    376.6mA
-1V       96.63mA    75.68mA    113.8mA
-400mV    33.52mA    23.96mA    40.98mA
1.6V      -93.78mA   -60.33mA   -125.1mA
3.7V      -115.5mA   -75.41mA   -164.4mA
4.2V      -131.1mA   -234.2mA   -167.2mA
4.5V      -214.4mA   -378.8mA   -181.5mA
4.9V      -410.7mA   -579.3mA   -274.3mA
5.1V      -515.8mA   -681mA     -367.8mA
6.6V      -1.327A    -1.453A    -1.18A
[GND_clamp]
| voltage   I(typ)   I(min)   I(max)
-3.3V     -1.286A    -1.273A    -1.29A
-1.3V     -213.2mA   -255.1mA   -198mA
-1.2V     -163mA     -206.8mA   -147.7mA
-1.1V     -114.8mA   -159.6mA   -100.3mA
-1V       -70.57mA   -114.1mA   -59.86mA
-900mV    -35.79mA   -71.75mA   -35.46mA
-800mV    -18.04mA   -35.69mA   -22.98mA
-700mV    -9.256mA   -12.38mA   -13.06mA
-600mV    -3.388mA   -3.468mA   -5.299mA
-500mV    -637.4uA   -792.4uA   -1.07mA
-300mV    -3.973uA   -15.32uA   -4.185uA
3.3V      1.048nA    17.64nA    698.5pA
[POWER_clamp]
| voltage   I(typ)   I(min)   I(max)
-3.3V     2.095nA    26.43nA    1.863nA
-3.2V     1.979nA    25.49nA    1.513nA
-2.9V     1.979nA    23.87nA    1.397nA
-2.3V     1.513nA    21.48nA    1.164nA
-2.2V     1.513nA    21.48nA    1.164nA
-2V       1.513nA    20.61nA    1.164nA
-1.3V     1.339nA    18.92nA    1.048nA
-1.1V     1.281nA    18.92nA    989.5pA
-800mV    1.281nA    18.22nA    989.5pA
-200mV    1.164nA    17.7nA     814.9pA
-100mV    1.164nA    17.4nA     814.9pA
0V        1.048nA    16.36nA    756.7pA
[Ramp]
| variable   typ   min   max
dV/dt_r   1.5474/0.3574n   1.2558/0.6149n   1.7748/0.2495n
dV/dt_f   1.6883/0.6190n   1.4376/1.0661n   1.8878/0.4204n
R_load = 50.0000
[Rising Waveform]
R_fixture = 50.0000
V_fixture = 0.000
| time   V(typ)   V(min)   V(max)
0s        0V         0V         0V
800ps     -7.133mV   1.143mV    99.13mV
1.1ns     203.7mV    -6.078mV   2.199V
1.2ns     701.5mV    -11.02mV   2.66V
1.4ns     1.714V     -22.03mV   2.887V
1.6ns     2.269V     61.66mV    2.929V
1.8ns     2.474V     538.2mV    2.944V
2.2ns     2.562V     1.488V     2.954V
2.7ns     2.574V     1.972V     2.956V
5ns       2.579V     2.093V     2.958V
[Rising Waveform]
R_fixture = 50.0000
V_fixture = 3.3000
V_fixture_min = 3.0000
V_fixture_max = 3.6000
| time   V(typ)   V(min)   V(max)
0s        485.6mV    602.6mV    453.2mV
600ps     487.9mV    603.1mV    500.7mV
700ps     496.1mV    603.4mV    766.4mV
900ps     838.8mV    604.8mV    2.534V
1ns       1.417V     615.9mV    3.208V
1.2ns     2.618V     765.3mV    3.518V
1.4ns     3.15V      1.537V     3.572V
1.8ns     3.275V     2.649V     3.591V
2ns       3.287V     2.845V     3.594V
5ns       3.299V     2.999V     3.599V
[Falling Waveform]
R_fixture = 50.0000
V_fixture = 3.3000
V_fixture_min = 3.0000
V_fixture_max = 3.6000
| time   V(typ)   V(min)   V(max)
0s        3.3V       3V         3.6V
700ps     3.299V     3V         3.561V
800ps     3.3V       3V         3.289V
1ns       3.179V     2.999V     1.931V
1.3ns     1.919V     3.015V     1.014V
1.5ns     1.406V     2.872V     527.1mV
2ns       603.7mV    1.806V     462mV
2.9ns     489.9mV    842.3mV    454.9mV
3.4ns     487.4mV    646.1mV    454.2mV
5ns       486.1mV    604mV      453.6mV
[Falling Waveform]
R_fixture = 50.0000
V_fixture = 0.000
| time   V(typ)   V(min)   V(max)
0s        2.579V     2.094V     2.959V
700ps     2.579V     2.094V     2.892V
800ps     2.58V      2.094V     2.337V
900ps     2.557V     2.094V     1.216V
1ns       2.271V     2.094V     539.9mV
1.2ns     836.7mV    2.095V     83.39mV
1.4ns     165.8mV    1.915V     20.35mV
1.8ns     20.82mV    487.3mV    6.461mV
2.1ns     7.058mV    85.16mV    3.38mV
5ns       319.1uV    429.6uV    332.1uV
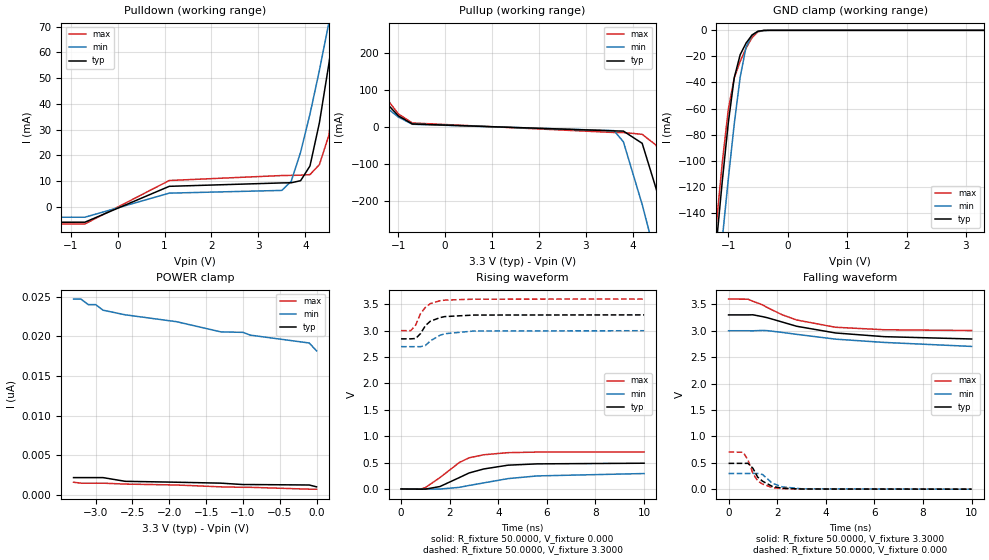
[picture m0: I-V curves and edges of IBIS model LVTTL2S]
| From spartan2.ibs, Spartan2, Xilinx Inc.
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|   Model LVTTL2S
[Model]   LVTTL2S
Model_type   I/O
Polarity   Non-Inverting
Enable   Active-Low
Vinl =   0.800V
Vinh =   2.000V
Vmeas =   1.4000V
Cref =  35.0000pF
Rref =   1.0000M
Vref =  0.000V
C_comp   6.5000pF   5.0000pF   8.0000pF
[Temperature Range]   27.0000   100.0000   0.000
[Voltage Range]   3.3000V   3.0000V   3.6000V
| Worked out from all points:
|   slope of the pulldown table from 0 to 0.495 V, typ, clamps not added: 106 ohm
|   slope of the pullup table from 0 to 0.495 V, typ, clamps not added: 139 ohm
|   GND clamp passes 1 mA (typ) near -0.51 V on its own axis
|   rising waveform, R_fixture 50.0000, V_fixture 0.000: 20-80 % time 1.66ns typ, 2.56ns min, 1.25ns max; typ from 0 V to 0.488 V
|   rising waveform, R_fixture 50.0000, V_fixture 3.3000: 20-80 % time 581ps typ, 684ps min, 494ps max; typ from 2.85 V to 3.3 V
|   falling waveform, R_fixture 50.0000, V_fixture 3.3000: 20-80 % time 3.05ns typ, 4.38ns min, 2.2ns max; typ from 3.3 V to 2.84 V
|   falling waveform, R_fixture 50.0000, V_fixture 0.000: 20-80 % time 561ps typ, 601ps min, 460ps max; typ from 0.489 V to 0 V
[Pulldown]
| voltage   I(typ)   I(min)   I(max)
-3.3V     -6.06mA    -4.064mA   -6.94mA
-700mV    -6.005mA   -4.064mA   -6.69mA
1.1V      7.946mA    5.295mA    10.21mA
3.5V      9.269mA    6.357mA    12.14mA
3.7V      9.327mA    9.93mA     12.21mA
3.9V      10.13mA    21.22mA    12.27mA
4.1V      15.87mA    36.07mA    12.5mA
4.3V      32.58mA    52.96mA    16.38mA
4.5V      55.25mA    71.28mA    27.63mA
4.7V      80.31mA    90.68mA    52.84mA
4.9V      106.7mA    110.9mA    83.48mA
6.6V      338.9mA    288.8mA    364.9mA
[Pullup]
| voltage   I(typ)   I(min)   I(max)
-3.3V     342.7mA    262.9mA    416.4mA
-2.7V     262.1mA    199.6mA    318.5mA
-1V       30.69mA    27.37mA    35.9mA
-700mV    8.534mA    7.753mA    11.26mA
3.6V      -10.07mA   -9.493mA   -14.48mA
3.8V      -10.68mA   -39.78mA   -14.57mA
4.2V      -43.78mA   -209.1mA   -19.4mA
4.5V      -167.4mA   -355.7mA   -49.03mA
4.9V      -372.8mA   -557mA     -204.3mA
5.1V      -478.9mA   -658.7mA   -308.3mA
5.3V      -585.9mA   -760.9mA   -415.3mA
6.6V      -1.29A     -1.43A     -1.128A
[GND_clamp]
| voltage   I(typ)   I(min)   I(max)
-3.3V     -1.286A    -1.273A    -1.289A
-1.2V     -163.3mA   -206.7mA   -148.3mA
-1.1V     -115.2mA   -159.6mA   -101mA
-1V       -71.04mA   -114.2mA   -60.78mA
-900mV    -36.42mA   -71.86mA   -36.53mA
-800mV    -18.72mA   -35.86mA   -23.84mA
-700mV    -9.715mA   -12.62mA   -13.63mA
-600mV    -3.608mA   -3.649mA   -5.602mA
-500mV    -692.7uA   -854.2uA   -1.156mA
-400mV    -68.48uA   -138.7uA   -98.54uA
-300mV    -4.365uA   -16.73uA   -4.627uA
3.3V      1.106nA    19.38nA    40.4nA
[POWER_clamp]
| voltage   I(typ)   I(min)   I(max)
-3.3V     2.212nA    24.68nA    1.63nA
-3.2V     2.212nA    24.68nA    1.513nA
-3.1V     2.212nA    23.98nA    1.513nA
-3V       2.212nA    23.98nA    1.513nA
-2.9V     2.212nA    23.28nA    1.513nA
-2.6V     1.746nA    22.7nA     1.397nA
-1.9V     1.63nA     21.83nA    1.281nA
-1.3V     1.513nA    20.55nA    1.048nA
-1V       1.339nA    20.49nA    989.5pA
-900mV    1.339nA    20.14nA    989.5pA
-100mV    1.281nA    19.15nA    756.7pA
0V        1.048nA    18.16nA    756.7pA
[Ramp]
| variable   typ   min   max
dV/dt_r   0.2928/1.6524n   0.1754/2.5361n   0.4216/1.2638n
dV/dt_f   0.2676/2.8635n   0.1662/3.7190n   0.3576/2.1933n
R_load = 50.0000
[Rising Waveform]
R_fixture = 50.0000
V_fixture = 0.000
| time   V(typ)   V(min)   V(max)
0s        0V         0V         0V
800ps     -3.787mV   135.9uV    -2.881mV
1ns       -2.807mV   -1.359mV   25.82mV
1.6ns     46.2mV     -1.634mV   215.6mV
2.4ns     216.2mV    30.53mV    502.1mV
2.8ns     303.4mV    66.27mV    590.7mV
3.4ns     378.8mV    115.2mV    647.9mV
4.4ns     450.7mV    196.3mV    688.3mV
5.6ns     475.6mV    247.3mV    698.9mV
10ns      488mV      292.3mV    702.7mV
[Rising Waveform]
R_fixture = 50.0000
V_fixture = 3.3000
V_fixture_min = 3.0000
V_fixture_max = 3.6000
| time   V(typ)   V(min)   V(max)
0s        2.845V     2.697V     3.001V
400ps     2.845V     2.697V     3.001V
600ps     2.851V     2.697V     3.104V
800ps     2.944V     2.697V     3.322V
1ns       3.094V     2.718V     3.44V
1.2ns     3.178V     2.804V     3.512V
1.6ns     3.247V     2.913V     3.567V
1.8ns     3.267V     2.942V     3.579V
3ns       3.296V     2.994V     3.597V
10ns      3.299V     2.999V     3.599V
[Falling Waveform]
R_fixture = 50.0000
V_fixture = 3.3000
V_fixture_min = 3.0000
V_fixture_max = 3.6000
| time   V(typ)   V(min)   V(max)
0s        3.3V       3V         3.6V
800ps     3.3V       3V         3.598V
1ns       3.302V     2.999V     3.559V
1.4ns     3.267V     3.006V     3.49V
1.6ns     3.246V     3.002V     3.438V
2.2ns     3.166V     2.969V     3.304V
2.8ns     3.085V     2.932V     3.204V
4.4ns     2.958V     2.841V     3.066V
6.4ns     2.888V     2.779V     3.019V
10ns      2.844V     2.703V     3.004V
[Falling Waveform]
R_fixture = 50.0000
V_fixture = 0.000
| time   V(typ)   V(min)   V(max)
0s        488.8mV    297.5mV    703.2mV
600ps     489mV      297.5mV    698.8mV
800ps     489.7mV    297.6mV    554.5mV
1ns       397.6mV    297.7mV    299.6mV
1.2ns     227.5mV    297.8mV    155mV
1.4ns     151mV      276.9mV    97.32mV
1.8ns     52.31mV    113mV      29.31mV
2.2ns     18.76mV    44.76mV    10.73mV
3ns       3.354mV    7.434mV    2.542mV
10ns      218uV      190.9uV    254.6uV
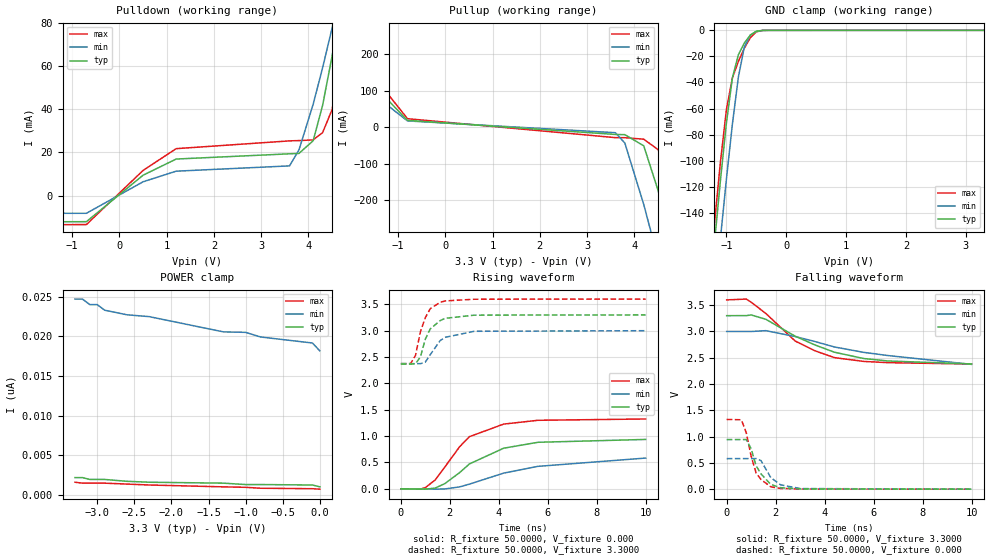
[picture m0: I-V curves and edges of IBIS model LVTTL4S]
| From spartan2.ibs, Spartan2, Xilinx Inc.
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|   Model LVTTL4S
[Model]   LVTTL4S
Model_type   I/O
Polarity   Non-Inverting
Enable   Active-Low
Vinl =   0.800V
Vinh =   2.000V
Vmeas =   1.4000V
Cref =  35.0000pF
Rref =   1.0000M
Vref =  0.000V
C_comp   6.5000pF   5.0000pF   8.0000pF
[Temperature Range]   27.0000   100.0000   0.000
[Voltage Range]   3.3000V   3.0000V   3.6000V
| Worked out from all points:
|   slope of the pulldown table from 0 to 0.495 V, typ, clamps not added: 52.7 ohm
|   slope of the pullup table from 0 to 0.495 V, typ, clamps not added: 72 ohm
|   GND clamp passes 1 mA (typ) near -0.51 V on its own axis
|   rising waveform, R_fixture 50.0000, V_fixture 0.000: 20-80 % time 2.01ns typ, 3.45ns min, 1.51ns max; typ from 0 V to 0.937 V
|   rising waveform, R_fixture 50.0000, V_fixture 3.3000: 20-80 % time 564ps typ, 671ps min, 487ps max; typ from 2.37 V to 3.3 V
|   falling waveform, R_fixture 50.0000, V_fixture 3.3000: 20-80 % time 2.73ns typ, 4.31ns min, 2.08ns max; typ from 3.3 V to 2.38 V
|   falling waveform, R_fixture 50.0000, V_fixture 0.000: 20-80 % time 550ps typ, 587ps min, 467ps max; typ from 0.943 V to 0 V
[Pulldown]
| voltage   I(typ)   I(min)   I(max)
-3.3V     -12.23mA   -8.171mA   -13.61mA
-700mV    -12.05mA   -8.171mA   -13.39mA
500mV     9.467mA    6.427mA    11.68mA
1.2V      16.95mA    11.33mA    21.76mA
3.6V      19.37mA    13.78mA    25.36mA
3.8V      19.56mA    21.23mA    25.5mA
4.1V      25.44mA    42.35mA    25.81mA
4.3V      41.86mA    59.27mA    29.21mA
4.5V      64.6mA     77.61mA    39.82mA
4.7V      89.71mA    97.03mA    64.96mA
4.9V      116.1mA    117.3mA    95.67mA
6.6V      348mA      295mA      376.7mA
[Pullup]
| voltage   I(typ)   I(min)   I(max)
-3.3V     354.4mA    271.9mA    429.9mA
-2.7V     272.8mA    207.8mA    331mA
-800mV    18.43mA    17.03mA    23.04mA
3.6V      -19.96mA   -15.22mA   -28.65mA
3.8V      -20.52mA   -43.41mA   -28.84mA
4.2V      -51mA      -211.2mA   -32.92mA
4.5V      -171.4mA   -357.8mA   -61.08mA
4.7V      -272mA     -457.9mA   -116mA
4.9V      -376.2mA   -559mA     -210.3mA
5.1V      -482.2mA   -660.7mA   -313.6mA
5.3V      -589.2mA   -762.8mA   -420.3mA
6.6V      -1.293A    -1.432A    -1.133A
[GND_clamp]
| voltage   I(typ)   I(min)   I(max)
-3.3V     -1.286A    -1.273A    -1.289A
-1.2V     -163.3mA   -206.7mA   -148.3mA
-1.1V     -115.2mA   -159.6mA   -101mA
-1V       -71.04mA   -114.2mA   -60.78mA
-900mV    -36.42mA   -71.86mA   -36.53mA
-800mV    -18.72mA   -35.86mA   -23.84mA
-700mV    -9.715mA   -12.62mA   -13.63mA
-600mV    -3.608mA   -3.649mA   -5.602mA
-500mV    -692.7uA   -854.2uA   -1.156mA
-400mV    -68.48uA   -138.7uA   -98.54uA
-300mV    -4.365uA   -16.73uA   -4.627uA
3.3V      1.164nA    19.5nA     40.4nA
[POWER_clamp]
| voltage   I(typ)   I(min)   I(max)
-3.3V     2.212nA    24.68nA    1.63nA
-3.2V     2.212nA    24.68nA    1.513nA
-3.1V     1.979nA    23.98nA    1.513nA
-3V       1.979nA    23.98nA    1.513nA
-2.9V     1.979nA    23.28nA    1.513nA
-2.6V     1.746nA    22.7nA     1.397nA
-2.3V     1.63nA     22.47nA    1.281nA
-1.3V     1.513nA    20.55nA    1.048nA
-1V       1.339nA    20.49nA    989.5pA
-800mV    1.339nA    19.91nA    873.1pA
-100mV    1.281nA    19.15nA    814.9pA
0V        1.048nA    18.16nA    756.7pA
[Ramp]
| variable   typ   min   max
dV/dt_r   0.5622/2.0206n   0.3323/2.9769n   0.7950/1.5333n
dV/dt_f   0.5508/2.7270n   0.3456/3.6283n   0.7320/2.0742n
R_load = 50.0000
[Rising Waveform]
R_fixture = 50.0000
V_fixture = 0.000
| time   V(typ)   V(min)   V(max)
0s        0V         0V         0V
800ps     -4.944mV   227.6uV    -6.08mV
1ns       -5.859mV   -1.95mV    24.41mV
1.4ns     14.65mV    -5.822mV   166.1mV
1.8ns     99.94mV    -1.623mV   416.7mV
2.4ns     307.7mV    36.82mV    798.3mV
2.8ns     472.4mV    89.52mV    989.3mV
4.2ns     770.7mV    298.6mV    1.228V
5.6ns     882.9mV    426.6mV    1.3V
10ns      937mV      583.8mV    1.325V
[Rising Waveform]
R_fixture = 50.0000
V_fixture = 3.3000
V_fixture_min = 3.0000
V_fixture_max = 3.6000
| time   V(typ)   V(min)   V(max)
0s        2.365V     2.374V     2.375V
400ps     2.365V     2.374V     2.375V
600ps     2.373V     2.374V     2.532V
800ps     2.503V     2.374V     2.98V
1ns       2.839V     2.404V     3.247V
1.2ns     3.032V     2.544V     3.417V
1.6ns     3.189V     2.808V     3.536V
1.8ns     3.233V     2.873V     3.563V
3ns       3.294V     2.988V     3.596V
10ns      3.299V     2.999V     3.599V
[Falling Waveform]
R_fixture = 50.0000
V_fixture = 3.3000
V_fixture_min = 3.0000
V_fixture_max = 3.6000
| time   V(typ)   V(min)   V(max)
0s        3.3V       3V         3.6V
800ps     3.301V     3V         3.616V
1ns       3.314V     2.999V     3.556V
1.6ns     3.231V     3.015V     3.342V
2.8ns     2.909V     2.903V     2.817V
3.6ns     2.744V     2.809V     2.633V
4.4ns     2.605V     2.705V     2.502V
5.6ns     2.485V     2.602V     2.43V
6.6ns     2.438V     2.541V     2.406V
10ns      2.382V     2.374V     2.38V
[Falling Waveform]
R_fixture = 50.0000
V_fixture = 0.000
| time   V(typ)   V(min)   V(max)
0s        943.3mV    581.6mV    1.327V
600ps     943.5mV    581.6mV    1.32V
800ps     944.6mV    581.7mV    1.073V
1ns       768.5mV    581.9mV    624.7mV
1.2ns     447mV      582.5mV    311.4mV
1.4ns     292mV      543.9mV    184.9mV
1.8ns     90.22mV    221.4mV    44.92mV
2.2ns     28.84mV    83.5mV     14.21mV
3ns       4.552mV    12.04mV    3.466mV
10ns      359.8uV    293.3uV    372.9uV
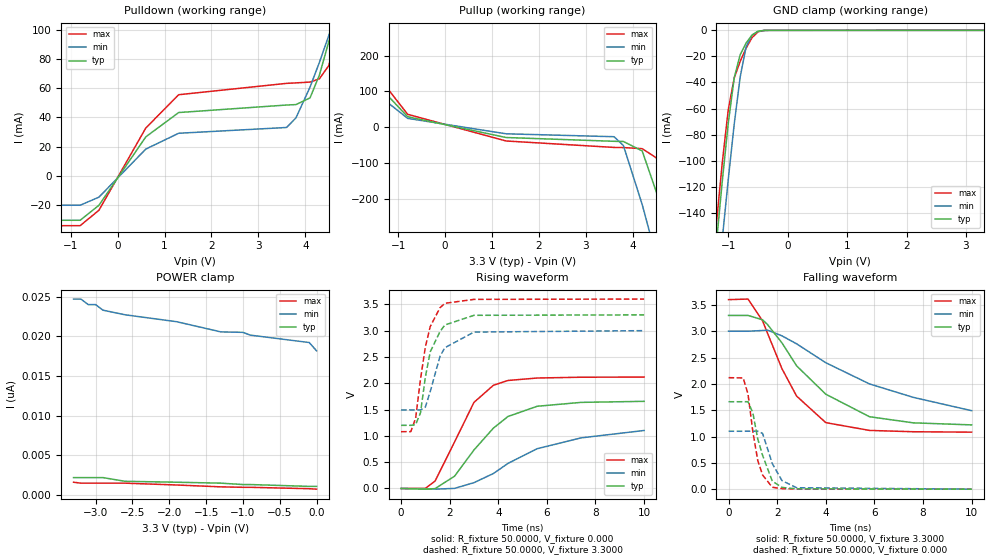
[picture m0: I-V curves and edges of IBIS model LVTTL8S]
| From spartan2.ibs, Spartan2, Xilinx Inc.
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|   Model LVTTL8S
[Model]   LVTTL8S
Model_type   I/O
Polarity   Non-Inverting
Enable   Active-Low
Vinl =   0.800V
Vinh =   2.000V
Vmeas =   1.4000V
Cref =  35.0000pF
Rref =   1.0000M
Vref =  0.000V
C_comp   6.5000pF   5.0000pF   8.0000pF
[Temperature Range]   27.0000   100.0000   0.000
[Voltage Range]   3.3000V   3.0000V   3.6000V
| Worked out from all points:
|   slope of the pulldown table from 0 to 0.495 V, typ, clamps not added: 21.7 ohm
|   slope of the pullup table from 0 to 0.495 V, typ, clamps not added: 37.4 ohm
|   GND clamp passes 1 mA (typ) near -0.51 V on its own axis
|   rising waveform, R_fixture 50.0000, V_fixture 0.000: 20-80 % time 1.89ns typ, 3.02ns min, 1.37ns max; typ from 0 V to 1.66 V
|   rising waveform, R_fixture 50.0000, V_fixture 3.3000: 20-80 % time 637ps typ, 679ps min, 554ps max; typ from 1.2 V to 3.3 V
|   falling waveform, R_fixture 50.0000, V_fixture 3.3000: 20-80 % time 2.49ns typ, 4.23ns min, 1.68ns max; typ from 3.3 V to 1.22 V
|   falling waveform, R_fixture 50.0000, V_fixture 0.000: 20-80 % time 547ps typ, 572ps min, 457ps max; typ from 1.66 V to 0 V
[Pulldown]
| voltage   I(typ)   I(min)   I(max)
-3.3V     -30.54mA   -20.22mA   -34.33mA
-800mV    -30.54mA   -20.22mA   -34.23mA
-400mV    -20.27mA   -14.69mA   -23.66mA
600mV     26.67mA    18.3mA     32.74mA
1.3V      43.34mA    29.13mA    55.56mA
3.6V      48.49mA    33.09mA    63.34mA
3.8V      48.79mA    39.63mA    63.67mA
4.1V      53.36mA    60.68mA    64.22mA
4.3V      68.97mA    77.68mA    66.46mA
4.5V      91.81mA    96.06mA    75.48mA
4.7V      116.9mA    115.5mA    100.2mA
6.6V      374.6mA    313mA      411.1mA
[Pullup]
| voltage   I(typ)   I(min)   I(max)
-3.3V     377.1mA    289.5mA    456.1mA
-2.5V     265.1mA    201.1mA    320.9mA
-800mV    29.02mA    24.47mA    35.82mA
1.3V      -28.95mA   -18.62mA   -38.67mA
3.6V      -39.57mA   -26.75mA   -56.67mA
3.8V      -40.09mA   -51.43mA   -57.06mA
4.2V      -66.46mA   -216mA     -60.14mA
4.5V      -180.3mA   -362.2mA   -85.65mA
4.7V      -279.8mA   -462.2mA   -132.6mA
4.9V      -383.6mA   -563.2mA   -223.6mA
5.1V      -489.4mA   -665mA     -325.3mA
6.6V      -1.3A      -1.436A    -1.143A
[GND_clamp]
| voltage   I(typ)   I(min)   I(max)
-3.3V     -1.286A    -1.273A    -1.289A
-1.2V     -163.3mA   -206.7mA   -148.3mA
-1.1V     -115.2mA   -159.6mA   -101mA
-1V       -71.04mA   -114.2mA   -60.78mA
-900mV    -36.42mA   -71.86mA   -36.53mA
-800mV    -18.72mA   -35.86mA   -23.84mA
-700mV    -9.715mA   -12.62mA   -13.63mA
-600mV    -3.608mA   -3.649mA   -5.602mA
-500mV    -692.7uA   -854.2uA   -1.156mA
-400mV    -68.48uA   -138.7uA   -98.54uA
-300mV    -4.365uA   -16.73uA   -4.627uA
3.3V      1.106nA    19.44nA    40.45nA
[POWER_clamp]
| voltage   I(typ)   I(min)   I(max)
-3.3V     2.212nA    24.68nA    1.63nA
-3.2V     2.212nA    24.68nA    1.513nA
-3.1V     2.212nA    23.98nA    1.513nA
-3V       2.212nA    23.98nA    1.513nA
-2.9V     2.212nA    23.28nA    1.513nA
-2.6V     1.746nA    22.7nA     1.513nA
-1.9V     1.63nA     21.83nA    1.281nA
-1.3V     1.513nA    20.55nA    1.048nA
-1V       1.339nA    20.49nA    989.5pA
-900mV    1.339nA    20.14nA    989.5pA
-100mV    1.106nA    19.21nA    814.9pA
0V        1.106nA    18.16nA    756.7pA
[Ramp]
| variable   typ   min   max
dV/dt_r   0.9936/1.9579n   0.6312/2.7392n   1.2702/1.3857n
dV/dt_f   1.2474/2.5568n   0.8334/3.5562n   1.5102/1.6863n
R_load = 50.0000
[Rising Waveform]
R_fixture = 50.0000
V_fixture = 0.000
| time   V(typ)   V(min)   V(max)
0s        0V         0V         0V
1ns       -12.71mV   -3.826mV   2.356mV
1.4ns     -2.362mV   -12.82mV   141.4mV
2.2ns     233.3mV    2.066mV    883.2mV
3ns       732mV      110.9mV    1.636V
3.8ns     1.147V     284.8mV    1.961V
4.4ns     1.368V     476.9mV    2.052V
5.6ns     1.562V     755.2mV    2.099V
7.4ns     1.636V     961.3mV    2.114V
10ns      1.656V     1.102V     2.117V
[Rising Waveform]
R_fixture = 50.0000
V_fixture = 3.3000
V_fixture_min = 3.0000
V_fixture_max = 3.6000
| time   V(typ)   V(min)   V(max)
0s        1.2V       1.493V     1.079V
400ps     1.2V       1.493V     1.08V
600ps     1.212V     1.493V     1.336V
800ps     1.438V     1.493V     2.078V
1ns       2.116V     1.547V     2.688V
1.2ns     2.596V     1.841V     3.076V
1.6ns     2.979V     2.508V     3.432V
1.8ns     3.106V     2.674V     3.518V
3ns       3.29V      2.972V     3.593V
10ns      3.299V     2.999V     3.599V
[Falling Waveform]
R_fixture = 50.0000
V_fixture = 3.3000
V_fixture_min = 3.0000
V_fixture_max = 3.6000
| time   V(typ)   V(min)   V(max)
0s        3.3V       3V         3.6V
800ps     3.3V       3V         3.611V
1.4ns     3.217V     3.014V     3.196V
1.6ns     3.129V     3.022V     2.966V
2.2ns     2.777V     2.912V     2.286V
2.8ns     2.343V     2.761V     1.768V
4ns       1.804V     2.402V     1.264V
5.8ns     1.376V     1.999V     1.116V
7.6ns     1.26V      1.744V     1.091V
10ns      1.221V     1.491V     1.083V
[Falling Waveform]
R_fixture = 50.0000
V_fixture = 0.000
| time   V(typ)   V(min)   V(max)
0s        1.661V     1.1V       2.118V
600ps     1.661V     1.1V       2.113V
800ps     1.662V     1.101V     1.809V
1ns       1.449V     1.101V     1.092V
1.2ns     955.3mV    1.101V     547.3mV
1.4ns     642.9mV    1.06V      270.2mV
1.8ns     151.3mV    486.3mV    36.26mV
2.2ns     33.33mV    161.3mV    10.3mV
2.8ns     6.159mV    27.53mV    3.684mV
10ns      338.1uV    436.9uV    299.4uV
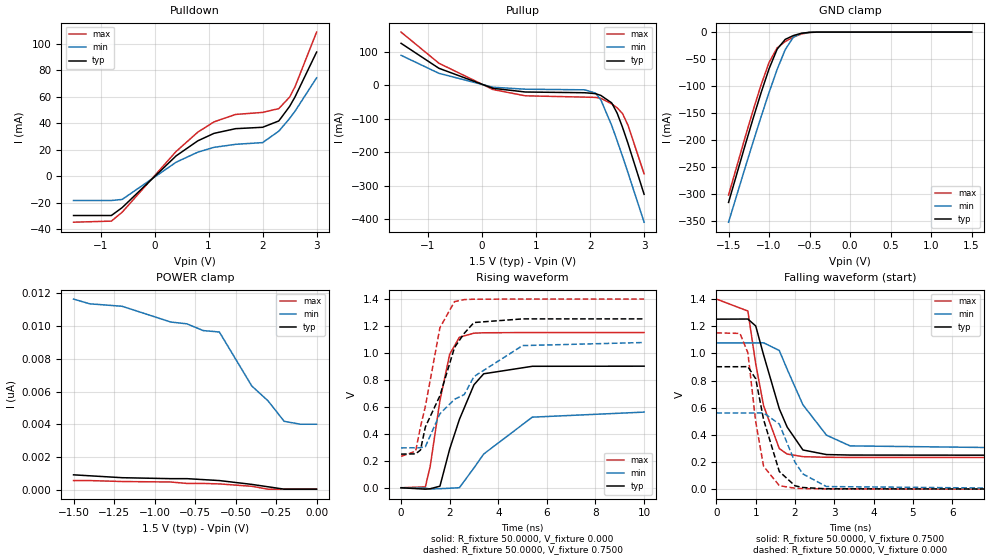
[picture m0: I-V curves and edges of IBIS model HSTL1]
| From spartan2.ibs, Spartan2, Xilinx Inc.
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|   Model HSTL1
[Model]   HSTL1
Model_type   I/O
Polarity   Non-Inverting
Enable   Active-Low
Vinl =   0.650V
Vinh =   0.850V
Vmeas =   0.7500V
Cref =  20.0000pF
Rref =  50.0000
Vref =   0.7500V
C_comp   6.5000pF   5.0000pF   8.0000pF
[Temperature Range]   27.0000   100.0000   0.000
[Voltage Range]   1.5000V   1.4000V   1.6000V
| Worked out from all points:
|   slope of the pulldown table from 0 to 0.225 V, typ, clamps not added: 24.8 ohm
|   slope of the pullup table from 0 to 0.225 V, typ, clamps not added: 24.4 ohm
|   GND clamp passes 1 mA (typ) near -0.53 V on its own axis
|   rising waveform, R_fixture 50.0000, V_fixture 0.000: 20-80 % time 1.03ns typ, 1.88ns min, 663ps max; typ from 0 V to 0.901 V
|   rising waveform, R_fixture 50.0000, V_fixture 0.7500: 20-80 % time 1.25ns typ, 2.16ns min, 755ps max; typ from 0.249 V to 1.25 V
|   falling waveform, R_fixture 50.0000, V_fixture 0.7500: 20-80 % time 671ps typ, 927ps min, 500ps max; typ from 1.25 V to 0.25 V
|   falling waveform, R_fixture 50.0000, V_fixture 0.000: 20-80 % time 476ps typ, 559ps min, 329ps max; typ from 0.902 V to 0 V
[Pulldown]
| voltage   I(typ)   I(min)   I(max)
-1.5V     -29.68mA   -18.37mA   -34.72mA
-800mV    -29.68mA   -18.37mA   -33.91mA
-600mV    -23.72mA   -17.55mA   -27.19mA
400mV     15.34mA    10.55mA    18.69mA
800mV     26.64mA    18.1mA     33.19mA
1.1V      32.29mA    21.75mA    40.96mA
1.5V      35.84mA    24.03mA    46.57mA
2V        36.88mA    25.32mA    48.11mA
2.3V      41.65mA    33.95mA    50.96mA
2.5V      52.62mA    43.52mA    59.65mA
2.6V      59.75mA    48.98mA    67.43mA
3V        93.62mA    74.2mA     108.7mA
[Pullup]
| voltage   I(typ)   I(min)   I(max)
-1.5V     125.9mA    90.12mA    159.4mA
-800mV    51.38mA    36.35mA    66.49mA
200mV     -8.409mA   -5.19mA    -12mA
800mV     -19.49mA   -11.15mA   -30.84mA
1.9V      -21.68mA   -12.97mA   -34.78mA
2.1V      -24.39mA   -22.73mA   -35.61mA
2.2V      -29.81mA   -43.31mA   -38.52mA
2.4V      -52.01mA   -119.4mA   -54.99mA
2.5V      -82.26mA   -164.5mA   -66.45mA
2.6V      -124.7mA   -211.5mA   -83.78mA
2.7V      -172.1mA   -259.7mA   -118mA
3V        -325mA     -408.2mA   -263.8mA
[GND_clamp]
| voltage   I(typ)   I(min)   I(max)
-1.5V     -315.9mA   -352.6mA   -302.3mA
-1.3V     -212.2mA   -253.8mA   -197.4mA
-1.2V     -161.8mA   -205.3mA   -146.7mA
-1.1V     -113.2mA   -157.8mA   -98.56mA
-1V       -68.04mA   -112mA     -56.27mA
-900mV    -31.6mA    -69.09mA   -29.2mA
-800mV    -13.5mA    -32.34mA   -17.42mA
-700mV    -6.408mA   -9.455mA   -9.303mA
-600mV    -2.237mA   -2.349mA   -3.538mA
-500mV    -423.5uA   -545.3uA   -698.2uA
-400mV    -42.44uA   -91.25uA   -59.93uA
1.5V      -87.31pA   4.555nA    -232.8pA
[POWER_clamp]
| voltage   I(typ)   I(min)   I(max)
-1.5V     931.3pA    11.64nA    582.1pA
-1.4V     873.1pA    11.35nA    582.1pA
-1.2V     756.7pA    11.2nA     523.9pA
-900mV    698.5pA    10.24nA    494.8pA
-800mV    698.5pA    10.13nA    407.5pA
-700mV    640.3pA    9.721nA    407.5pA
-600mV    582.1pA    9.633nA    378.3pA
-400mV    349.2pA    6.345nA    232.8pA
-300mV    203.7pA    5.442nA    58.21pA
-200mV    58.21pA    4.191nA    58.21pA
-100mV    58.21pA    4.016nA    58.21pA
0V        58.21pA    4.016nA    58.21pA
[Ramp]
| variable   typ   min   max
dV/dt_r   0.5408/1.0716n   0.3365/1.8300n   0.6906/0.6205n
dV/dt_f   0.5827/0.7352n   0.4596/1.1486n   0.6673/0.5435n
R_load = 50.0000
[Rising Waveform]
R_fixture = 50.0000
V_fixture = 0.000
| time   V(typ)   V(min)   V(max)
0s        0V         0V         0V
1ns       -10.54mV   -3.072mV   6.601mV
1.2ns     -7.344mV   -9.406mV   159.2mV
1.6ns     11.53mV    -6.788mV   646.7mV
2ns       286.5mV    -3.729mV   989.2mV
2.4ns     506.4mV    592.4uV    1.116V
3ns       763.5mV    146.9mV    1.146V
3.4ns     844.9mV    250mV      1.149V
5.4ns     900.5mV    523.4mV    1.151V
10ns      901.3mV    560.8mV    1.151V
[Rising Waveform]
R_fixture = 50.0000
V_fixture = 0.7500
V_fixture_min = 0.7000
V_fixture_max = 0.8000
| time   V(typ)   V(min)   V(max)
0s        249.3mV    295.8mV    232.7mV
600ps     251.2mV    296.4mV    270.9mV
800ps     279.9mV    296.5mV    452.6mV
1ns       450.6mV    304.1mV    602.7mV
1.6ns     682.8mV    548.7mV    1.187V
2.2ns     1.04V      655.8mV    1.38V
2.6ns     1.145V     691mV      1.395V
3ns       1.225V     824.5mV    1.398V
5ns       1.252V     1.054V     1.399V
10ns      1.252V     1.077V     1.399V
[Falling Waveform]
R_fixture = 50.0000
V_fixture = 0.7500
V_fixture_min = 0.7000
V_fixture_max = 0.8000
| time   V(typ)   V(min)   V(max)
0s        1.252V     1.077V     1.4V
800ps     1.253V     1.077V     1.312V
1ns       1.202V     1.077V     923.5mV
1.2ns     988.8mV    1.078V     614.8mV
1.6ns     591.7mV    1.021V     298.9mV
1.8ns     457.4mV    883.1mV    258.7mV
2.2ns     288.9mV    621.8mV    239.6mV
2.8ns     255mV      397.7mV    235mV
3.4ns     251.4mV    318.9mV    233.9mV
10ns      249.6mV    296.2mV    232.9mV
[Falling Waveform]
R_fixture = 50.0000
V_fixture = 0.000
| time   V(typ)   V(min)   V(max)
0s        901.7mV    561.2mV    1.151V
600ps     901.8mV    561.3mV    1.147V
800ps     902.4mV    561.4mV    1.005V
1ns       812.9mV    561.3mV    496.1mV
1.2ns     512.5mV    562mV      169.1mV
1.6ns     130.3mV    479.6mV    25.94mV
2ns       24.99mV    197.9mV    6.981mV
2.2ns     12.24mV    112.4mV    4.699mV
2.8ns     2.94mV     19.47mV    1.812mV
10ns      229.3uV    270.9uV    216.6uV
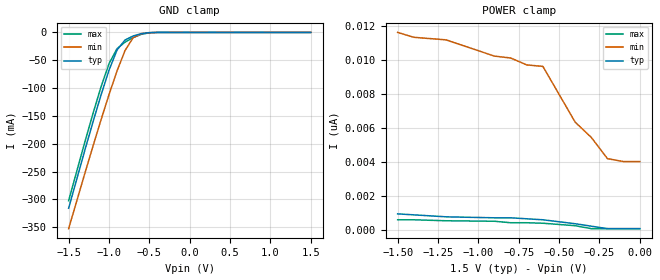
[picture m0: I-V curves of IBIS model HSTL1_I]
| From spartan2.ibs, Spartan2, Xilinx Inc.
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|   Model HSTL1_I
[Model]   HSTL1_I
Model_type   Input
Polarity   Non-Inverting
Vinl =   0.650V
Vinh =   0.850V
C_comp   6.5000pF   5.0000pF   8.0000pF
[Temperature Range]   27.0000   100.0000   0.000
[Voltage Range]   1.5000V   1.4000V   1.6000V
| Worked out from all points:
|   GND clamp passes 1 mA (typ) near -0.53 V on its own axis
[GND_clamp]
| voltage   I(typ)   I(min)   I(max)
-1.5V     -315.9mA   -352.6mA   -302.3mA
-1.3V     -212.2mA   -253.8mA   -197.4mA
-1.2V     -161.8mA   -205.3mA   -146.7mA
-1.1V     -113.2mA   -157.8mA   -98.56mA
-1V       -68.04mA   -112mA     -56.27mA
-900mV    -31.6mA    -69.09mA   -29.2mA
-800mV    -13.5mA    -32.34mA   -17.42mA
-700mV    -6.408mA   -9.455mA   -9.303mA
-600mV    -2.237mA   -2.349mA   -3.538mA
-500mV    -423.5uA   -545.3uA   -698.2uA
-400mV    -42.44uA   -91.25uA   -59.93uA
1.5V      -87.31pA   4.555nA    -232.8pA
[POWER_clamp]
| voltage   I(typ)   I(min)   I(max)
-1.5V     931.3pA    11.64nA    582.1pA
-1.4V     873.1pA    11.35nA    582.1pA
-1.2V     756.7pA    11.2nA     523.9pA
-900mV    698.5pA    10.24nA    494.8pA
-800mV    698.5pA    10.13nA    407.5pA
-700mV    640.3pA    9.721nA    407.5pA
-600mV    582.1pA    9.633nA    378.3pA
-400mV    349.2pA    6.345nA    232.8pA
-300mV    203.7pA    5.442nA    58.21pA
-200mV    58.21pA    4.191nA    58.21pA
-100mV    58.21pA    4.016nA    58.21pA
0V        58.21pA    4.016nA    58.21pA
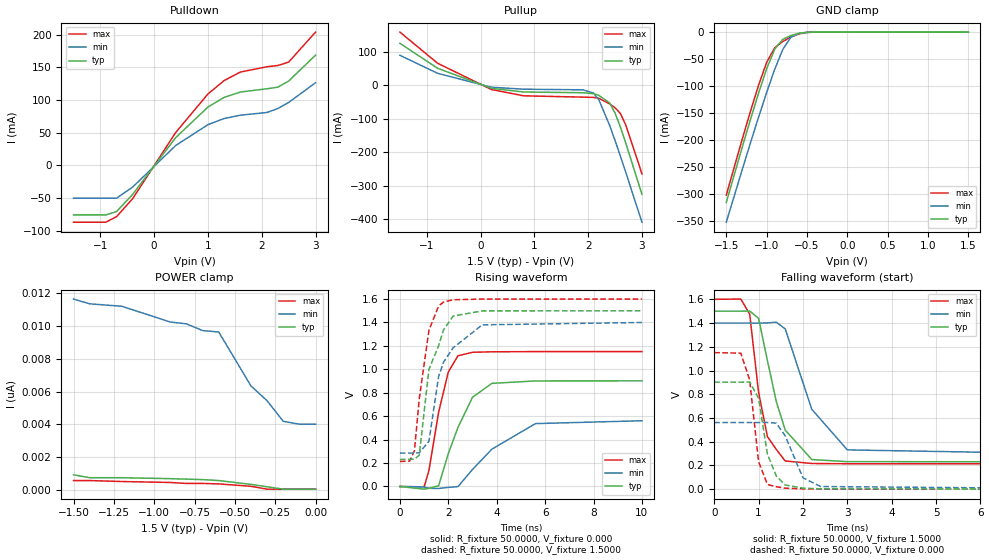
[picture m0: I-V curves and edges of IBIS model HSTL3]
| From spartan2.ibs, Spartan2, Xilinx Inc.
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|   Model HSTL3
[Model]   HSTL3
Model_type   I/O
Polarity   Non-Inverting
Enable   Active-Low
Vinl =   0.800V
Vinh =   1.000V
Vmeas =   0.9000V
Cref =  20.0000pF
Rref =  50.0000
Vref =   1.5000V
C_comp   6.5000pF   5.0000pF   8.0000pF
[Temperature Range]   27.0000   100.0000   0.000
[Voltage Range]   1.5000V   1.4000V   1.6000V
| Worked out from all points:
|   slope of the pulldown table from 0 to 0.225 V, typ, clamps not added: 9.08 ohm
|   slope of the pullup table from 0 to 0.225 V, typ, clamps not added: 24.4 ohm
|   GND clamp passes 1 mA (typ) near -0.53 V on its own axis
|   rising waveform, R_fixture 50.0000, V_fixture 0.000: 20-80 % time 1.03ns typ, 1.88ns min, 658ps max; typ from 0 V to 0.901 V
|   rising waveform, R_fixture 50.0000, V_fixture 1.5000: 20-80 % time 759ps typ, 889ps min, 508ps max; typ from 0.23 V to 1.5 V
|   falling waveform, R_fixture 50.0000, V_fixture 1.5000: 20-80 % time 517ps typ, 848ps min, 328ps max; typ from 1.5 V to 0.23 V
|   falling waveform, R_fixture 50.0000, V_fixture 0.000: 20-80 % time 305ps typ, 374ps min, 203ps max; typ from 0.902 V to 0 V
[Pulldown]
| voltage   I(typ)   I(min)   I(max)
-1.5V     -76.04mA   -50.45mA   -87.2mA
-900mV    -76.04mA   -50.45mA   -87.2mA
-700mV    -70.92mA   -50.45mA   -78.75mA
-400mV    -44.61mA   -33.36mA   -51.11mA
400mV     42.41mA    30.33mA    50.21mA
1V        89.28mA    62.26mA    109.3mA
1.3V      104mA      71.66mA    129.8mA
1.6V      112.2mA    76.72mA    142.8mA
2.1V      117.3mA    80.97mA    151.1mA
2.3V      119.7mA    87.01mA    152.9mA
2.5V      129.1mA    96.26mA    158.1mA
3V        168.7mA    126.5mA    204.1mA
[Pullup]
| voltage   I(typ)   I(min)   I(max)
-1.5V     125.9mA    90.12mA    159.4mA
-800mV    51.38mA    36.35mA    66.49mA
200mV     -8.409mA   -5.19mA    -12mA
800mV     -19.49mA   -11.15mA   -30.84mA
1.9V      -21.68mA   -12.97mA   -34.78mA
2.1V      -24.39mA   -22.73mA   -35.61mA
2.2V      -29.81mA   -43.31mA   -38.52mA
2.4V      -52.01mA   -119.4mA   -54.99mA
2.5V      -82.26mA   -164.5mA   -66.45mA
2.6V      -124.7mA   -211.5mA   -83.78mA
2.7V      -172.1mA   -259.7mA   -118mA
3V        -325mA     -408.2mA   -263.8mA
[GND_clamp]
| voltage   I(typ)   I(min)   I(max)
-1.5V     -315.9mA   -352.6mA   -302.3mA
-1.3V     -212.2mA   -253.8mA   -197.4mA
-1.2V     -161.8mA   -205.3mA   -146.7mA
-1.1V     -113.2mA   -157.8mA   -98.56mA
-1V       -68.04mA   -112mA     -56.27mA
-900mV    -31.6mA    -69.09mA   -29.2mA
-800mV    -13.5mA    -32.34mA   -17.42mA
-700mV    -6.408mA   -9.455mA   -9.303mA
-600mV    -2.237mA   -2.349mA   -3.538mA
-500mV    -423.5uA   -545.3uA   -698.2uA
-400mV    -42.44uA   -91.25uA   -59.93uA
1.5V      -189.2pA   4.555nA    -232.8pA
[POWER_clamp]
| voltage   I(typ)   I(min)   I(max)
-1.5V     931.3pA    11.64nA    582.1pA
-1.4V     756.7pA    11.35nA    582.1pA
-1.2V     756.7pA    11.2nA     523.9pA
-900mV    698.5pA    10.24nA    465.7pA
-800mV    669.4pA    10.13nA    407.5pA
-700mV    640.3pA    9.721nA    407.5pA
-600mV    582.1pA    9.633nA    378.3pA
-400mV    349.2pA    6.345nA    232.8pA
-300mV    203.7pA    5.442nA    58.21pA
-200mV    58.21pA    4.191nA    58.21pA
-100mV    58.21pA    4.016nA    58.21pA
0V        58.21pA    4.016nA    58.21pA
[Ramp]
| variable   typ   min   max
dV/dt_r   0.5408/1.0679n   0.3365/1.8265n   0.6906/0.6208n
dV/dt_f   0.7618/0.4372n   0.6689/0.8417n   0.8318/0.3121n
R_load = 50.0000
[Rising Waveform]
R_fixture = 50.0000
V_fixture = 0.000
| time   V(typ)   V(min)   V(max)
0s        0V         0V         0V
1ns       -22.84mV   -4.376mV   -3.153mV
1.2ns     -15.39mV   -15.88mV   136.3mV
1.6ns     6.461mV    -16.9mV    633.8mV
2ns       281.1mV    -7.623mV   977mV
2.4ns     503.9mV    -1.114mV   1.115V
3ns       761.1mV    145.4mV    1.145V
3.8ns     879.9mV    318.3mV    1.149V
5.6ns     900.6mV    536.4mV    1.151V
10ns      901.3mV    560.9mV    1.151V
[Rising Waveform]
R_fixture = 50.0000
V_fixture = 1.5000
V_fixture_min = 1.4000
V_fixture_max = 1.6000
| time   V(typ)   V(min)   V(max)
0s        230.3mV    284.9mV    213.5mV
400ps     231.3mV    285.1mV    216.3mV
600ps     233.3mV    285.9mV    303.6mV
800ps     267.2mV    286.4mV    748.7mV
1.2ns     999.6mV    387.1mV    1.333V
1.6ns     1.202V     938.2mV    1.54V
1.8ns     1.335V     1.06V      1.573V
2.2ns     1.454V     1.183V     1.593V
3.4ns     1.498V     1.379V     1.599V
10ns      1.499V     1.399V     1.599V
[Falling Waveform]
R_fixture = 50.0000
V_fixture = 1.5000
V_fixture_min = 1.4000
V_fixture_max = 1.6000
| time   V(typ)   V(min)   V(max)
0s        1.5V       1.4V       1.6V
600ps     1.5V       1.4V       1.602V
800ps     1.501V     1.4V       1.475V
1ns       1.44V      1.399V     816.4mV
1.2ns     1.083V     1.401V     442.4mV
1.4ns     738.2mV    1.407V     334.8mV
1.6ns     498mV      1.351V     237.9mV
2.2ns     249.9mV    673mV      216.4mV
3ns       232mV      331.1mV    214.3mV
10ns      230.4mV    285.1mV    213.6mV
[Falling Waveform]
R_fixture = 50.0000
V_fixture = 0.000
| time   V(typ)   V(min)   V(max)
0s        901.7mV    561.2mV    1.151V
600ps     901.8mV    561.3mV    1.146V
800ps     903.1mV    561.3mV    919.7mV
1ns       765.6mV    561.3mV    232mV
1.2ns     294.3mV    562mV      39.25mV
1.4ns     109.9mV    556.8mV    20.52mV
1.6ns     35.55mV    449.3mV    8.203mV
2ns       8.481mV    95.92mV    2.753mV
2.4ns     2.878mV    22.21mV    1.252mV
10ns      101.2uV    121.3uV    94.98uV
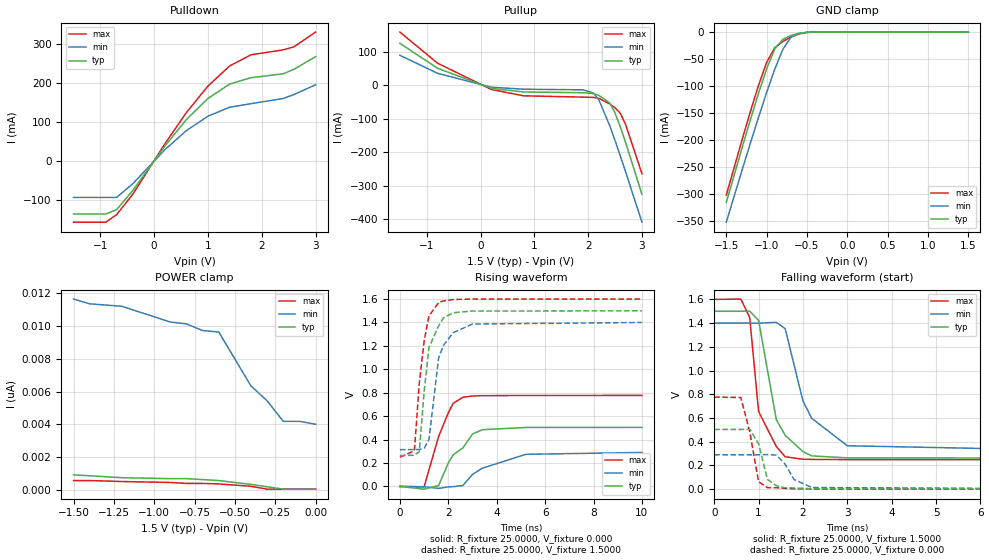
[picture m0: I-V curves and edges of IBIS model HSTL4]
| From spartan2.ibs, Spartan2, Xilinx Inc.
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|   Model HSTL4
[Model]   HSTL4
Model_type   I/O
Polarity   Non-Inverting
Enable   Active-Low
Vinl =   0.800V
Vinh =   1.000V
Vmeas =   0.9000V
Cref =  20.0000pF
Rref =  25.0000
Vref =   1.5000V
C_comp   6.5000pF   5.0000pF   8.0000pF
[Temperature Range]   27.0000   100.0000   0.000
[Voltage Range]   1.5000V   1.4000V   1.6000V
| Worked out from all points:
|   slope of the pulldown table from 0 to 0.225 V, typ, clamps not added: 5.28 ohm
|   slope of the pullup table from 0 to 0.225 V, typ, clamps not added: 24.4 ohm
|   GND clamp passes 1 mA (typ) near -0.53 V on its own axis
|   rising waveform, R_fixture 25.0000, V_fixture 0.000: 20-80 % time 1.01ns typ, 1.77ns min, 733ps max; typ from 0 V to 0.503 V
|   rising waveform, R_fixture 25.0000, V_fixture 1.5000: 20-80 % time 468ps typ, 477ps min, 409ps max; typ from 0.263 V to 1.5 V
|   falling waveform, R_fixture 25.0000, V_fixture 1.5000: 20-80 % time 445ps typ, 737ps min, 282ps max; typ from 1.5 V to 0.263 V
|   falling waveform, R_fixture 25.0000, V_fixture 0.000: 20-80 % time 220ps typ, 350ps min, 251ps max; typ from 0.503 V to 0 V
[Pulldown]
| voltage   I(typ)   I(min)   I(max)
-1.5V     -136.4mA   -94.05mA   -157.5mA
-900mV    -136.4mA   -94.05mA   -157.5mA
-700mV    -125.6mA   -94.05mA   -138.3mA
-400mV    -76.79mA   -59.23mA   -86.45mA
200mV     38.08mA    28.46mA    43.69mA
600mV     105.8mA    77.4mA     123.8mA
1V        159.7mA    114.1mA    191.4mA
1.4V      196.5mA    137.1mA    242.7mA
1.8V      212.9mA    146.3mA    271.6mA
2.4V      222.9mA    159.6mA    284.2mA
2.6V      234.5mA    169.8mA    292.2mA
3V        266.8mA    194.7mA    329.8mA
[Pullup]
| voltage   I(typ)   I(min)   I(max)
-1.5V     125.9mA    90.12mA    159.4mA
-800mV    51.38mA    36.35mA    66.49mA
200mV     -8.409mA   -5.19mA    -12mA
800mV     -19.49mA   -11.15mA   -30.84mA
1.9V      -21.68mA   -12.97mA   -34.78mA
2.1V      -24.39mA   -22.73mA   -35.61mA
2.2V      -29.81mA   -43.31mA   -38.52mA
2.4V      -52.01mA   -119.4mA   -54.99mA
2.5V      -82.26mA   -164.5mA   -66.45mA
2.6V      -124.7mA   -211.5mA   -83.78mA
2.7V      -172.1mA   -259.7mA   -118mA
3V        -325mA     -408.2mA   -263.8mA
[GND_clamp]
| voltage   I(typ)   I(min)   I(max)
-1.5V     -315.9mA   -352.6mA   -302.3mA
-1.3V     -212.2mA   -253.8mA   -197.4mA
-1.2V     -161.8mA   -205.3mA   -146.7mA
-1.1V     -113.2mA   -157.8mA   -98.56mA
-1V       -68.04mA   -112mA     -56.27mA
-900mV    -31.6mA    -69.09mA   -29.2mA
-800mV    -13.5mA    -32.34mA   -17.42mA
-700mV    -6.408mA   -9.455mA   -9.303mA
-600mV    -2.237mA   -2.349mA   -3.538mA
-500mV    -423.5uA   -545.3uA   -698.2uA
-400mV    -42.44uA   -91.25uA   -59.93uA
1.5V      -87.31pA   4.555nA    -232.8pA
[POWER_clamp]
| voltage   I(typ)   I(min)   I(max)
-1.5V     931.3pA    11.64nA    582.1pA
-1.4V     873.1pA    11.35nA    582.1pA
-1.2V     756.7pA    11.2nA     523.9pA
-900mV    698.5pA    10.24nA    465.7pA
-800mV    698.5pA    10.13nA    407.5pA
-700mV    640.3pA    9.721nA    407.5pA
-600mV    582.1pA    9.633nA    378.3pA
-400mV    349.2pA    6.345nA    232.8pA
-300mV    203.7pA    5.442nA    58.21pA
-200mV    58.21pA    4.191nA    58.21pA
-100mV    58.21pA    4.191nA    58.21pA
0V        58.21pA    4.016nA    58.21pA
[Ramp]
| variable   typ   min   max
dV/dt_r   0.3020/1.0477n   0.1741/1.7652n   0.4658/0.6963n
dV/dt_f   0.7423/0.3128n   0.6519/0.7113n   0.8106/0.2196n
R_load = 25.0000
[Rising Waveform]
R_fixture = 25.0000
V_fixture = 0.000
| time   V(typ)   V(min)   V(max)
0s        0V         0V         0V
1ns       -23.52mV   -2.938mV   -4.198mV
1.6ns     7.869mV    -16.9mV    426.8mV
2ns       200mV      -4.044mV   628.2mV
2.2ns     269.8mV    -1.904mV   709.1mV
2.6ns     328mV      7.621mV    760.6mV
3ns       447mV      102.4mV    772.1mV
3.4ns     483.9mV    154.7mV    774.3mV
5.2ns     503mV      273.8mV    776.2mV
10ns      503.4mV    290.1mV    776.4mV
[Rising Waveform]
R_fixture = 25.0000
V_fixture = 1.5000
V_fixture_min = 1.4000
V_fixture_max = 1.6000
| time   V(typ)   V(min)   V(max)
0s        262.8mV    313.4mV    248.9mV
600ps     266.5mV    314.6mV    304.3mV
800ps     295.3mV    315.2mV    878.5mV
1ns       804.6mV    325.2mV    1.238V
1.2ns     1.185V     398.9mV    1.455V
1.6ns     1.37V      1.098V     1.569V
1.8ns     1.438V     1.204V     1.583V
2.2ns     1.482V     1.312V     1.595V
3ns       1.497V     1.386V     1.599V
10ns      1.499V     1.399V     1.599V
[Falling Waveform]
R_fixture = 25.0000
V_fixture = 1.5000
V_fixture_min = 1.4000
V_fixture_max = 1.6000
| time   V(typ)   V(min)   V(max)
0s        1.5V       1.4V       1.6V
600ps     1.5V       1.4V       1.603V
800ps     1.501V     1.4V       1.448V
1ns       1.424V     1.399V     654.8mV
1.4ns     586.2mV    1.407V     360mV
1.6ns     453.8mV    1.353V     272.9mV
2ns       316.8mV    743.5mV    252.5mV
2.2ns     280.5mV    597mV      250.8mV
3ns       263.9mV    366.1mV    249.3mV
10ns      262.8mV    313.5mV    249mV
[Falling Waveform]
R_fixture = 25.0000
V_fixture = 0.000
| time   V(typ)   V(min)   V(max)
0s        503.5mV    290.2mV    776.6mV
600ps     503.5mV    290.2mV    772.8mV
800ps     504.7mV    290.2mV    485.8mV
1ns       383.1mV    290.2mV    62.66mV
1.2ns     81.73mV    291.4mV    12.94mV
1.4ns     29.22mV    287.7mV    12.28mV
1.6ns     11.23mV    210.4mV    6.348mV
1.8ns     10.19mV    81.89mV    3.159mV
2.2ns     3.481mV    13.88mV    929.3uV
10ns      40.18uV    50.83uV    38.78uV
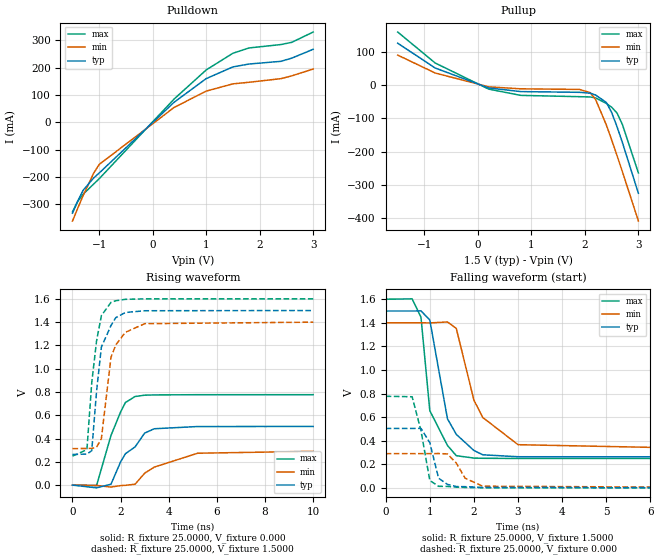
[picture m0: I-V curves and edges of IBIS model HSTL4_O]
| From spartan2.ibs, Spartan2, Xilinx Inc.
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|   Model HSTL4_O
[Model]   HSTL4_O
Model_type   Output
Polarity   Non-Inverting
Vmeas =   0.9000V
Cref =  20.0000pF
Rref =  25.0000
Vref =   1.5000V
C_comp   6.5000pF   5.0000pF   8.0000pF
[Temperature Range]   27.0000   100.0000   0.000
[Voltage Range]   1.5000V   1.4000V   1.6000V
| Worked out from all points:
|   slope of the pulldown table from 0 to 0.225 V, typ, clamps not added: 5.28 ohm
|   slope of the pullup table from 0 to 0.225 V, typ, clamps not added: 24.4 ohm
|   rising waveform, R_fixture 25.0000, V_fixture 0.000: 20-80 % time 1.01ns typ, 1.77ns min, 733ps max; typ from 0 V to 0.503 V
|   rising waveform, R_fixture 25.0000, V_fixture 1.5000: 20-80 % time 468ps typ, 477ps min, 409ps max; typ from 0.263 V to 1.5 V
|   falling waveform, R_fixture 25.0000, V_fixture 1.5000: 20-80 % time 445ps typ, 737ps min, 282ps max; typ from 1.5 V to 0.263 V
|   falling waveform, R_fixture 25.0000, V_fixture 0.000: 20-80 % time 220ps typ, 350ps min, 251ps max; typ from 0.503 V to 0 V
[Pulldown]
| voltage   I(typ)   I(min)   I(max)
-1.5V     -331.8mA   -360.4mA   -326.5mA
-1.4V     -286.6mA   -313mA     -288.2mA
-1.3V     -248mA     -267mA     -262.3mA
-1.1V     -202.4mA   -184.3mA   -224.6mA
-1V       -185mA     -153.7mA   -205.8mA
400mV     73.46mA    54.34mA    85.07mA
1V        159.7mA    114.1mA    191.4mA
1.5V      202.5mA    140.5mA    252.4mA
1.8V      212.9mA    146.3mA    271.6mA
2.4V      222.9mA    159.6mA    284.2mA
2.6V      234.5mA    169.8mA    292.2mA
3V        266.8mA    194.7mA    329.8mA
[Pullup]
| voltage   I(typ)   I(min)   I(max)
-1.5V     125.9mA    90.12mA    159.4mA
-800mV    51.38mA    36.35mA    66.49mA
200mV     -8.409mA   -5.19mA    -12mA
800mV     -19.49mA   -11.15mA   -30.84mA
1.9V      -21.68mA   -12.97mA   -34.78mA
2.1V      -24.39mA   -22.73mA   -35.61mA
2.2V      -29.81mA   -43.31mA   -38.52mA
2.4V      -52.01mA   -119.4mA   -54.99mA
2.5V      -82.26mA   -164.5mA   -66.45mA
2.6V      -124.7mA   -211.5mA   -83.78mA
2.7V      -172.1mA   -259.7mA   -118mA
3V        -325mA     -408.2mA   -263.8mA
[Ramp]
| variable   typ   min   max
dV/dt_r   0.3020/1.0477n   0.1741/1.7652n   0.4658/0.6963n
dV/dt_f   0.7423/0.3128n   0.6519/0.7113n   0.8106/0.2196n
R_load = 25.0000
[Rising Waveform]
R_fixture = 25.0000
V_fixture = 0.000
| time   V(typ)   V(min)   V(max)
0s        0V         0V         0V
1ns       -23.52mV   -2.938mV   -4.198mV
1.6ns     7.869mV    -16.9mV    426.8mV
2ns       200mV      -4.044mV   628.2mV
2.2ns     269.8mV    -1.904mV   709.1mV
2.6ns     328mV      7.621mV    760.6mV
3ns       447mV      102.4mV    772.1mV
3.4ns     483.9mV    154.7mV    774.3mV
5.2ns     503mV      273.8mV    776.2mV
10ns      503.4mV    290.1mV    776.4mV
[Rising Waveform]
R_fixture = 25.0000
V_fixture = 1.5000
V_fixture_min = 1.4000
V_fixture_max = 1.6000
| time   V(typ)   V(min)   V(max)
0s        262.8mV    313.4mV    248.9mV
600ps     266.5mV    314.6mV    304.3mV
800ps     295.3mV    315.2mV    878.5mV
1ns       804.6mV    325.2mV    1.238V
1.2ns     1.185V     398.9mV    1.455V
1.6ns     1.37V      1.098V     1.569V
1.8ns     1.438V     1.204V     1.583V
2.2ns     1.482V     1.312V     1.595V
3ns       1.497V     1.386V     1.599V
10ns      1.499V     1.399V     1.599V
[Falling Waveform]
R_fixture = 25.0000
V_fixture = 1.5000
V_fixture_min = 1.4000
V_fixture_max = 1.6000
| time   V(typ)   V(min)   V(max)
0s        1.5V       1.4V       1.6V
600ps     1.5V       1.4V       1.603V
800ps     1.501V     1.4V       1.448V
1ns       1.424V     1.399V     654.8mV
1.4ns     586.2mV    1.407V     360mV
1.6ns     453.8mV    1.353V     272.9mV
2ns       316.8mV    743.5mV    252.5mV
2.2ns     280.5mV    597mV      250.8mV
3ns       263.9mV    366.1mV    249.3mV
10ns      262.8mV    313.5mV    249mV
[Falling Waveform]
R_fixture = 25.0000
V_fixture = 0.000
| time   V(typ)   V(min)   V(max)
0s        503.5mV    290.2mV    776.6mV
600ps     503.5mV    290.2mV    772.8mV
800ps     504.7mV    290.2mV    485.8mV
1ns       383.1mV    290.2mV    62.66mV
1.2ns     81.73mV    291.4mV    12.94mV
1.4ns     29.22mV    287.7mV    12.28mV
1.6ns     11.23mV    210.4mV    6.348mV
1.8ns     10.19mV    81.89mV    3.159mV
2.2ns     3.481mV    13.88mV    929.3uV
10ns      40.18uV    50.83uV    38.78uV
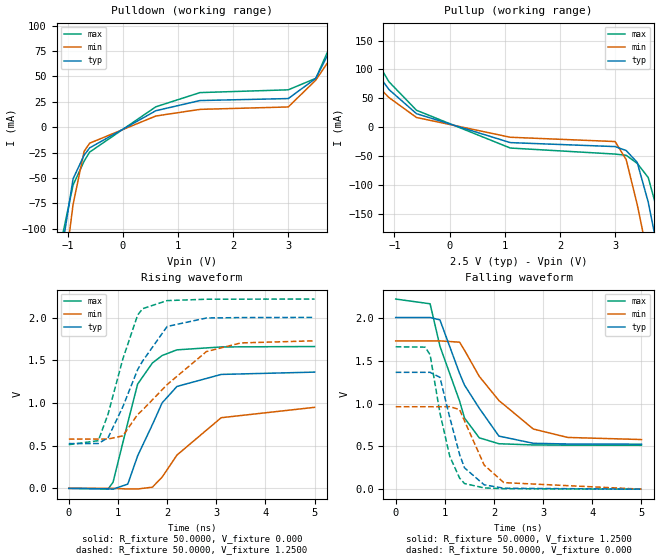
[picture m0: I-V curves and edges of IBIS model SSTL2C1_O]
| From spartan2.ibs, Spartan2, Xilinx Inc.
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|   Model SSTL2C1_O
[Model]   SSTL2C1_O
Model_type   Output
Polarity   Non-Inverting
Vmeas =   1.2500V
Cref =  30.0000pF
| The Rref below represents only the parallel load, there is actually a series
| R, see the application notes for details.
Rref =  50.0000
Vref =   1.2500V
C_comp   6.5000pF   5.0000pF   8.0000pF
[Temperature Range]   27.0000   100.0000   0.000
[Voltage Range]   2.5000V   2.3750V   2.6250V
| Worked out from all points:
|   slope of the pulldown table from 0 to 0.375 V, typ, clamps not added: 34.4 ohm
|   slope of the pullup table from 0 to 0.375 V, typ, clamps not added: 31.7 ohm
|   rising waveform, R_fixture 50.0000, V_fixture 0.000: 20-80 % time 665ps typ, 904ps min, 486ps max; typ from 0 V to 1.36 V
|   rising waveform, R_fixture 50.0000, V_fixture 1.2500: 20-80 % time 756ps typ, 1.24ns min, 513ps max; typ from 0.524 V to 2 V
|   falling waveform, R_fixture 50.0000, V_fixture 1.2500: 20-80 % time 753ps typ, 1.1ns min, 565ps max; typ from 2 V to 0.525 V
|   falling waveform, R_fixture 50.0000, V_fixture 0.000: 20-80 % time 378ps typ, 511ps min, 358ps max; typ from 1.36 V to 0.001 V
[Pulldown]
| voltage   I(typ)   I(min)   I(max)
-2.5V     -852.6mA   -861.6mA   -848.1mA
-1.1V     -119.9mA   -161.5mA   -108.6mA
-900mV    -50.85mA   -76.14mA   -56.99mA
-700mV    -27.61mA   -23.85mA   -33.54mA
-600mV    -20.43mA   -15.8mA    -24.57mA
600mV     16.16mA    10.96mA    20.03mA
1.4V      26.19mA    17.5mA     34.01mA
3V        28.13mA    19.87mA    36.74mA
3.5V      48.03mA    46.32mA    48.06mA
4V        101.6mA    86.66mA    109.5mA
4.2V      125.5mA    104.7mA    138.5mA
5V        225.3mA    181.9mA    258.3mA
[Pullup]
| voltage   I(typ)   I(min)   I(max)
-2.5V     251.1mA    191.7mA    303.5mA
-2.1V     197.5mA    149.4mA    240.2mA
-1.1V     65.28mA    51.35mA    78.74mA
-600mV    23.34mA    16.74mA    29.24mA
1.1V      -26.83mA   -17.54mA   -36.23mA
3V        -33.72mA   -24.99mA   -46.7mA
3.2V      -40.57mA   -56.24mA   -48.81mA
3.4V      -61.01mA   -134.1mA   -62.77mA
3.6V      -130mA     -226.7mA   -87.4mA
3.8V      -226.1mA   -324mA     -157.1mA
4V        -328.7mA   -423.6mA   -255.1mA
5V        -863.9mA   -933mA     -795.2mA
[Ramp]
| variable   typ   min   max
dV/dt_r   0.8172/0.6545n   0.5697/0.9344n   0.9972/0.5112n
dV/dt_f   0.7566/1.0572n   0.5220/1.3229n   0.9174/0.7917n
R_load = 50.0000
[Rising Waveform]
R_fixture = 50.0000
V_fixture = 0.000
| time   V(typ)   V(min)   V(max)
0s        5.066uV    0V         0V
800ps     -5.766mV   489.9uV    -6.745mV
900ps     -9.454mV   -471.6uV   71.65mV
1.2ns     49.91mV    -7.187mV   769.9mV
1.4ns     380.9mV    -7.485mV   1.222V
1.7ns     746.4mV    13.69mV    1.469V
1.9ns     1.003V     132.8mV    1.557V
2.2ns     1.194V     390.3mV    1.623V
3.1ns     1.335V     827.8mV    1.657V
5ns       1.362V     949.4mV    1.662V
[Rising Waveform]
R_fixture = 50.0000
V_fixture = 1.2500
V_fixture_min = 1.1100
V_fixture_max = 1.3900
| time   V(typ)   V(min)   V(max)
0s        524.3mV    577.6mV    512mV
600ps     525.7mV    577.9mV    558.9mV
800ps     594.2mV    578mV      872.6mV
1.1ns     957.2mV    615.2mV    1.518V
1.4ns     1.391V     865.2mV    2.03V
1.5ns     1.49V      917.9mV    2.105V
2ns       1.897V     1.216V     2.2V
2.8ns     1.996V     1.603V     2.216V
3.5ns     2.001V     1.704V     2.217V
5ns       2.003V     1.729V     2.218V
[Falling Waveform]
R_fixture = 50.0000
V_fixture = 1.2500
V_fixture_min = 1.1100
V_fixture_max = 1.3900
| time   V(typ)   V(min)   V(max)
0s        2.004V     1.731V     2.219V
700ps     2.004V     1.731V     2.164V
900ps     1.976V     1.731V     1.669V
1.3ns     1.351V     1.716V     1.028V
1.4ns     1.215V     1.622V     830.6mV
1.7ns     945.3mV    1.317V     600mV
2.1ns     619.8mV    1.035V     530.8mV
2.8ns     535.9mV    702.3mV    516.5mV
3.5ns     527.9mV    604.2mV    514mV
5ns       525.4mV    579.8mV    512.8mV
[Falling Waveform]
R_fixture = 50.0000
V_fixture = 0.000
| time   V(typ)   V(min)   V(max)
0s        1.364V     962.4mV    1.662V
600ps     1.364V     962.4mV    1.658V
700ps     1.364V     962.4mV    1.569V
900ps     1.306V     962.4mV    889.9mV
1.1ns     836.9mV    963.4mV    383.4mV
1.3ns     406mV      929.8mV    130.3mV
1.4ns     249.6mV    797.3mV    66.27mV
1.8ns     51.46mV    282.1mV    15.25mV
2.2ns     11.45mV    77.02mV    6.166mV
5ns       689.5uV    808.1uV    659.1uV
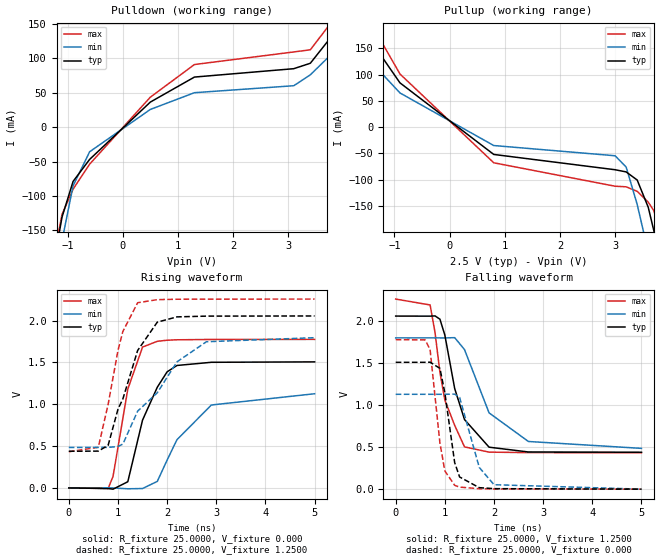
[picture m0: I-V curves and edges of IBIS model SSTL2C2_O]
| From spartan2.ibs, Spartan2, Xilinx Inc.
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|   Model SSTL2C2_O
[Model]   SSTL2C2_O
Model_type   Output
Polarity   Non-Inverting
Vmeas =   1.2500V
Cref =  30.0000pF
| The Rref below represents only the parallel load, there is actually a series
| R, see the application notes for details.
Rref =  25.0000
Vref =   1.2500V
C_comp   6.5000pF   5.0000pF   8.0000pF
[Temperature Range]   27.0000   100.0000   0.000
[Voltage Range]   2.5000V   2.3750V   2.6250V
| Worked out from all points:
|   slope of the pulldown table from 0 to 0.375 V, typ, clamps not added: 13.3 ohm
|   slope of the pullup table from 0 to 0.375 V, typ, clamps not added: 13.5 ohm
|   rising waveform, R_fixture 25.0000, V_fixture 0.000: 20-80 % time 501ps typ, 810ps min, 346ps max; typ from 0 V to 1.51 V
|   rising waveform, R_fixture 25.0000, V_fixture 1.2500: 20-80 % time 565ps typ, 996ps min, 379ps max; typ from 0.438 V to 2.06 V
|   falling waveform, R_fixture 25.0000, V_fixture 1.2500: 20-80 % time 455ps typ, 705ps min, 375ps max; typ from 2.06 V to 0.439 V
|   falling waveform, R_fixture 25.0000, V_fixture 0.000: 20-80 % time 229ps typ, 327ps min, 209ps max; typ from 1.51 V to 0 V
[Pulldown]
| voltage   I(typ)   I(min)   I(max)
-2.5V     -848.1mA   -858.2mA   -843.7mA
-1.3V     -219.8mA   -257.6mA   -208.1mA
-1.1V     -130.8mA   -165.1mA   -126.9mA
-900mV    -78.97mA   -85.43mA   -90.15mA
-600mV    -46.92mA   -35.82mA   -53.89mA
500mV     36.44mA    25.74mA    43.59mA
1.3V      72.85mA    50.1mA     91.09mA
3.1V      85.03mA    60.25mA    109.4mA
3.4V      92.93mA    76.09mA    112.5mA
4V        153.7mA    123.1mA    175.4mA
4.4V      201.7mA    159.6mA    233.2mA
5V        276.1mA    217.6mA    322.4mA
[Pullup]
| voltage   I(typ)   I(min)   I(max)
-2.5V     327.4mA    250.2mA    392.3mA
-1.7V     206mA      155.7mA    248.4mA
-900mV    84.49mA    65.22mA    101.4mA
800mV     -52.07mA   -35.08mA   -67.97mA
3V        -81.26mA   -54.59mA   -112.7mA
3.2V      -85.38mA   -76.17mA   -113.8mA
3.4V      -100.9mA   -147.5mA   -122.5mA
3.6V      -152.8mA   -238.4mA   -143mA
3.7V      -196.7mA   -286.3mA   -159mA
3.8V      -244.6mA   -335.1mA   -190.1mA
4V        -346mA     -434.4mA   -281.1mA
5V        -880.7mA   -943.9mA   -818.2mA
[Ramp]
| variable   typ   min   max
dV/dt_r   0.9042/0.5002n   0.6756/0.8377n   1.0656/0.3423n
dV/dt_f   0.9190/0.7247n   0.7164/1.1416n   1.0479/0.5134n
R_load = 25.0000
[Rising Waveform]
R_fixture = 25.0000
V_fixture = 0.000
| time   V(typ)   V(min)   V(max)
0s        2.219uV    0V         0V
800ps     -7.399mV   1.028mV    -7.234mV
900ps     -14.9mV    -547uV     138.2mV
1.2ns     74.01mV    -10.37mV   1.181V
1.5ns     811.1mV    -7.305mV   1.684V
1.8ns     1.204V     77.93mV    1.753V
2ns       1.388V     332.7mV    1.766V
2.2ns     1.464V     576.4mV    1.771V
2.9ns     1.502V     991.3mV    1.775V
5ns       1.507V     1.126V     1.776V
[Rising Waveform]
R_fixture = 25.0000
V_fixture = 1.2500
V_fixture_min = 1.1100
V_fixture_max = 1.3900
| time   V(typ)   V(min)   V(max)
0s        438.3mV    484.1mV    432.9mV
600ps     440.1mV    484.6mV    485.5mV
800ps     509.7mV    484.8mV    1V
1ns       941.2mV    495.1mV    1.644V
1.1ns     1.065V     524.6mV    1.871V
1.4ns     1.643V     917.7mV    2.214V
1.8ns     1.982V     1.138V     2.251V
2.2ns     2.045V     1.507V     2.256V
2.8ns     2.054V     1.748V     2.257V
5ns       2.056V     1.796V     2.258V
[Falling Waveform]
R_fixture = 25.0000
V_fixture = 1.2500
V_fixture_min = 1.1100
V_fixture_max = 1.3900
| time   V(typ)   V(min)   V(max)
0s        2.056V     1.797V     2.258V
700ps     2.055V     1.797V     2.188V
800ps     2.058V     1.797V     1.863V
900ps     2.019V     1.797V     1.387V
1ns       1.831V     1.796V     1.058V
1.2ns     1.196V     1.8V       758.4mV
1.4ns     826.9mV    1.658V     502.5mV
1.9ns     498.9mV    906.1mV    440.2mV
2.7ns     442mV      566.6mV    434.4mV
5ns       438.7mV    484.8mV    433.2mV
[Falling Waveform]
R_fixture = 25.0000
V_fixture = 0.000
| time   V(typ)   V(min)   V(max)
0s        1.507V     1.127V     1.776V
600ps     1.507V     1.127V     1.773V
700ps     1.508V     1.127V     1.657V
900ps     1.435V     1.127V     548.7mV
1ns       1.145V     1.127V     216.6mV
1.2ns     315.5mV    1.129V     46.19mV
1.3ns     145.2mV    1.091V     24.41mV
1.7ns     18.01mV    258.4mV    5.774mV
2ns       6.311mV    53.19mV    3.161mV
5ns       294.6uV    356.6uV    279.6uV
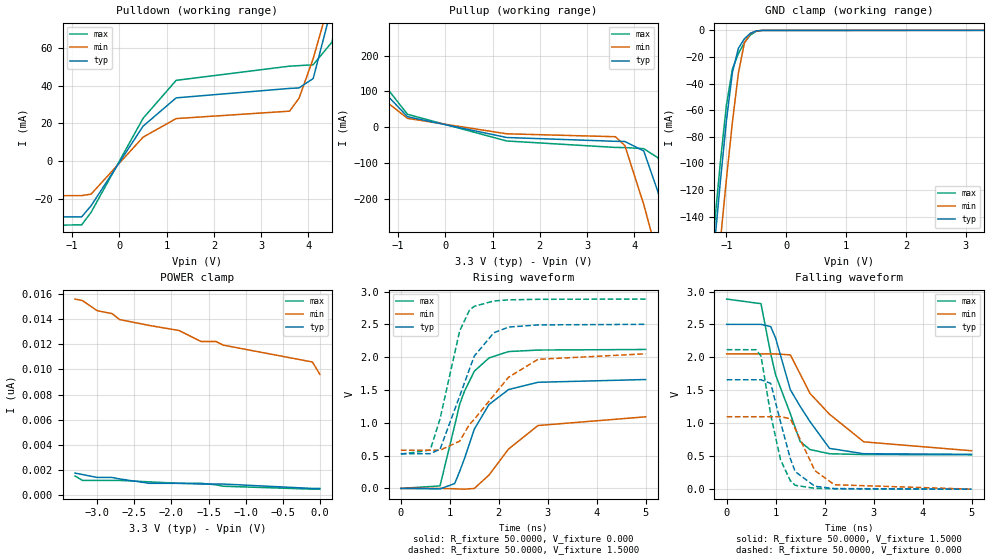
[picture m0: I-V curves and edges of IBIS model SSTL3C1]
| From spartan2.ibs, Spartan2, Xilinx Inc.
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|   Model SSTL3C1
[Model]   SSTL3C1
Model_type   I/O
Polarity   Non-Inverting
Enable   Active-Low
Vinl =   1.300V
Vinh =   1.700V
Vmeas =   1.5000V
Cref =  30.0000pF
| The Rref below represents only the parallel load, there is actually a series
| R, see the application notes for details.
Rref =  50.0000
Vref =   1.5000V
C_comp   6.5000pF   5.0000pF   8.0000pF
[Temperature Range]   27.0000   100.0000   0.000
[Voltage Range]   3.3000V   3.0000V   3.6000V
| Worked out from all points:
|   slope of the pulldown table from 0 to 0.495 V, typ, clamps not added: 26.9 ohm
|   slope of the pullup table from 0 to 0.495 V, typ, clamps not added: 37.4 ohm
|   GND clamp passes 1 mA (typ) near -0.53 V on its own axis
|   rising waveform, R_fixture 50.0000, V_fixture 0.000: 20-80 % time 638ps typ, 812ps min, 484ps max; typ from 0 V to 1.66 V
|   rising waveform, R_fixture 50.0000, V_fixture 1.5000: 20-80 % time 595ps typ, 986ps min, 430ps max; typ from 0.529 V to 2.5 V
|   falling waveform, R_fixture 50.0000, V_fixture 1.5000: 20-80 % time 712ps typ, 1.08ns min, 533ps max; typ from 2.5 V to 0.53 V
|   falling waveform, R_fixture 50.0000, V_fixture 0.000: 20-80 % time 353ps typ, 458ps min, 334ps max; typ from 1.66 V to 0.001 V
[Pulldown]
| voltage   I(typ)   I(min)   I(max)
-3.3V     -29.68mA   -18.37mA   -34.72mA
-800mV    -29.68mA   -18.37mA   -33.91mA
-600mV    -23.72mA   -17.55mA   -27.19mA
500mV     18.56mA    12.72mA    22.73mA
1.2V      33.61mA    22.59mA    42.92mA
3.6V      38.63mA    26.54mA    50.47mA
3.8V      38.89mA    33.38mA    50.74mA
4.1V      43.87mA    54.46mA    51.2mA
4.5V      82.59mA    89.82mA    63.33mA
4.7V      107.7mA    109.3mA    88.23mA
4.9V      134.1mA    129.5mA    119mA
6.6V      365.7mA    306.9mA    399.5mA
[Pullup]
| voltage   I(typ)   I(min)   I(max)
-3.3V     377.1mA    289.5mA    456.1mA
-2.5V     265.1mA    201.1mA    320.9mA
-800mV    29.02mA    24.47mA    35.82mA
1.3V      -28.95mA   -18.62mA   -38.67mA
3.6V      -39.57mA   -26.75mA   -56.67mA
3.8V      -40.09mA   -51.43mA   -57.06mA
4.2V      -66.46mA   -216mA     -60.14mA
4.5V      -180.3mA   -362.2mA   -85.64mA
4.7V      -279.8mA   -462.2mA   -132.6mA
4.9V      -383.6mA   -563.2mA   -223.6mA
5.1V      -489.4mA   -665mA     -325.3mA
6.6V      -1.3A      -1.436A    -1.143A
[GND_clamp]
| voltage   I(typ)   I(min)   I(max)
-3.3V     -1.286A    -1.272A    -1.289A
-1.2V     -161.8mA   -205.3mA   -146.7mA
-1.1V     -113.2mA   -157.8mA   -98.56mA
-1V       -68.04mA   -112mA     -56.27mA
-900mV    -31.6mA    -69.09mA   -29.2mA
-800mV    -13.5mA    -32.34mA   -17.42mA
-700mV    -6.408mA   -9.455mA   -9.303mA
-600mV    -2.237mA   -2.349mA   -3.538mA
-500mV    -423.5uA   -545.3uA   -698.2uA
-400mV    -42.47uA   -91.26uA   -59.93uA
3.3V      29.92nA    10.77nA    349.2pA
[POWER_clamp]
| voltage   I(typ)   I(min)   I(max)
-3.3V     1.746nA    15.6nA     1.513nA
-3.2V     1.63nA     15.48nA    1.164nA
-3V       1.397nA    14.67nA    1.164nA
-2.8V     1.397nA    14.44nA    1.164nA
-2.7V     1.281nA    13.97nA    1.164nA
-2.3V     931.3pA    13.5nA     1.048nA
-1.9V     931.3pA    13.1nA     931.3pA
-1.6V     873.1pA    12.22nA    931.3pA
-1.4V     873.1pA    12.22nA    814.9pA
-1.3V     873.1pA    11.93nA    698.5pA
-100mV    523.9pA    10.59nA    465.7pA
0V        523.9pA    9.604nA    465.7pA
[Ramp]
| variable   typ   min   max
dV/dt_r   0.9954/0.6371n   0.6546/0.8153n   1.2702/0.5064n
dV/dt_f   1.0728/0.9626n   0.7290/1.3495n   1.3524/0.7579n
R_load = 50.0000
[Rising Waveform]
R_fixture = 50.0000
V_fixture = 0.000
| time   V(typ)   V(min)   V(max)
0s        5.675uV    709.9nV    0V
800ps     -7.329mV   407.7uV    37.95mV
1.1ns     74.18mV    -5.769mV   960.5mV
1.2ns     256.9mV    -9.435mV   1.279V
1.3ns     456.1mV    -11.53mV   1.482V
1.5ns     902mV      -669.3uV   1.785V
1.8ns     1.278V     203.6mV    1.988V
2.2ns     1.506V     600.1mV    2.085V
2.8ns     1.617V     957.9mV    2.108V
5ns       1.659V     1.091V     2.117V
[Rising Waveform]
R_fixture = 50.0000
V_fixture = 1.5000
V_fixture_min = 1.3000
V_fixture_max = 1.7000
| time   V(typ)   V(min)   V(max)
0s        528.6mV    581.9mV    521.6mV
600ps     529.5mV    582.2mV    584mV
800ps     596mV      582.1mV    1.059V
1.2ns     1.404V     719.6mV    2.397V
1.4ns     1.815V     973.8mV    2.714V
1.5ns     2.017V     1.053V     2.775V
1.9ns     2.372V     1.421V     2.856V
2.2ns     2.458V     1.694V     2.873V
2.8ns     2.491V     1.967V     2.881V
5ns       2.5V       2.051V     2.885V
[Falling Waveform]
R_fixture = 50.0000
V_fixture = 1.5000
V_fixture_min = 1.3000
V_fixture_max = 1.7000
| time   V(typ)   V(min)   V(max)
0s        2.502V     2.053V     2.886V
700ps     2.502V     2.053V     2.816V
900ps     2.468V     2.053V     2.054V
1ns       2.291V     2.053V     1.733V
1.3ns     1.51V      2.039V     1.145V
1.5ns     1.258V     1.749V     723.8mV
1.7ns     1.028V     1.455V     602.1mV
2.1ns     619.8mV    1.138V     538.3mV
2.8ns     538.6mV    718.7mV    526mV
5ns       529.6mV    583.8mV    522.5mV
[Falling Waveform]
R_fixture = 50.0000
V_fixture = 0.000
| time   V(typ)   V(min)   V(max)
0s        1.661V     1.1V       2.118V
600ps     1.661V     1.1V       2.117V
700ps     1.661V     1.1V       2.023V
900ps     1.606V     1.1V       1.125V
1.1ns     1.019V     1.101V     448mV
1.3ns     462.8mV    1.069V     128.8mV
1.4ns     266.4mV    917.1mV    59.3mV
1.8ns     44.88mV    282.5mV    13.7mV
2.2ns     9.742mV    67.92mV    5.859mV
5ns       635.3uV    688uV      654.3uV
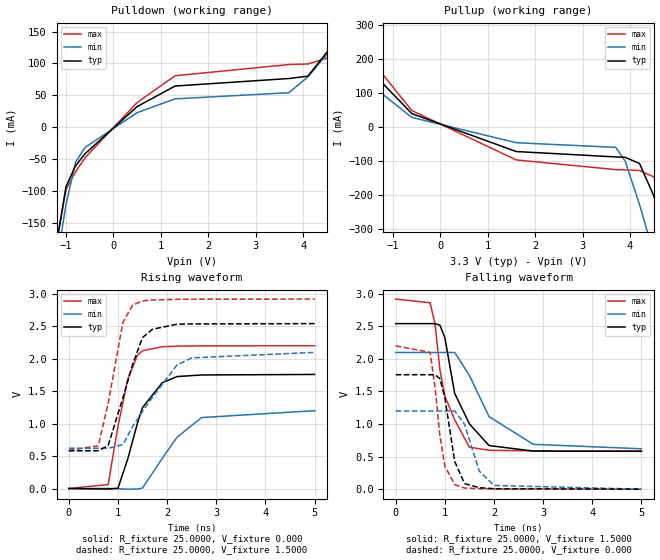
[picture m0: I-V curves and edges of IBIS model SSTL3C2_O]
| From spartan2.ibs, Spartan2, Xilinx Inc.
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|   Model SSTL3C2_O
[Model]   SSTL3C2_O
Model_type   Output
Polarity   Non-Inverting
Vmeas =   1.5000V
Cref =  30.0000pF
| The Rref below represents only the parallel load, there is actually a series
| R, see the application notes for details.
Rref =  25.0000
Vref =   1.5000V
C_comp   6.5000pF   5.0000pF   8.0000pF
[Temperature Range]   27.0000   100.0000   0.000
[Voltage Range]   3.3000V   3.0000V   3.6000V
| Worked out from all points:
|   slope of the pulldown table from 0 to 0.495 V, typ, clamps not added: 15.4 ohm
|   slope of the pullup table from 0 to 0.495 V, typ, clamps not added: 17.3 ohm
|   rising waveform, R_fixture 25.0000, V_fixture 0.000: 20-80 % time 464ps typ, 701ps min, 340ps max; typ from 0 V to 1.76 V
|   rising waveform, R_fixture 25.0000, V_fixture 1.5000: 20-80 % time 461ps typ, 830ps min, 333ps max; typ from 0.581 V to 2.54 V
|   falling waveform, R_fixture 25.0000, V_fixture 1.5000: 20-80 % time 514ps typ, 772ps min, 395ps max; typ from 2.54 V to 0.582 V
|   falling waveform, R_fixture 25.0000, V_fixture 0.000: 20-80 % time 235ps typ, 317ps min, 218ps max; typ from 1.76 V to 0 V
[Pulldown]
| voltage   I(typ)   I(min)   I(max)
-3.3V     -1.281A    -1.27A     -1.284A
-1.5V     -318.9mA   -354.1mA   -306.4mA
-1V       -93.51mA   -121.5mA   -98.08mA
-800mV    -60.84mA   -55.35mA   -70.38mA
-600mV    -41.86mA   -32.01mA   -48.2mA
500mV     32.35mA    22.81mA    38.75mA
1.3V      64.57mA    44.42mA    80.71mA
3.7V      76.41mA    54.11mA    98.37mA
4.1V      80.11mA    79.08mA    99.25mA
4.5V      117.6mA    114.4mA    108.3mA
4.9V      168.6mA    153.8mA    162.6mA
6.6V      399mA      330.4mA    441.4mA
[Pullup]
| voltage   I(typ)   I(min)   I(max)
-3.3V     436.2mA    335.3mA    524.4mA
-2.7V     347.9mA    265.6mA    417.8mA
-2.3V     285.8mA    216.7mA    344mA
-600mV    39.77mA    28.63mA    48.74mA
1.6V      -71.79mA   -45.85mA   -96.47mA
3.7V      -87.68mA   -59.58mA   -125.1mA
3.9V      -88.89mA   -100.8mA   -125.9mA
4.2V      -107mA     -227.6mA   -127.6mA
4.5V      -202.1mA   -372.5mA   -146.3mA
4.9V      -400.7mA   -573.2mA   -255.5mA
5.1V      -506mA     -674.9mA   -352.4mA
6.6V      -1.316A    -1.447A    -1.167A
[Ramp]
| variable   typ   min   max
dV/dt_r   1.0542/0.4566n   0.7194/0.6978n   1.3194/0.3340n
dV/dt_f   1.0404/0.7570n   0.7338/1.1465n   1.2834/0.5563n
R_load = 25.0000
[Rising Waveform]
R_fixture = 25.0000
V_fixture = 0.000
| time   V(typ)   V(min)   V(max)
0s        0V         0V         0V
800ps     -8.148mV   637.2uV    61.22mV
1ns       4.559mV    -2.903mV   958.8mV
1.2ns     458.2mV    -9.873mV   1.685V
1.4ns     1.018V     -7.774mV   2.058V
1.5ns     1.247V     8.379mV    2.122V
1.9ns     1.629V     463.4mV    2.183V
2.2ns     1.724V     788.7mV    2.193V
2.7ns     1.749V     1.093V     2.197V
5ns       1.757V     1.199V     2.199V
[Rising Waveform]
R_fixture = 25.0000
V_fixture = 1.5000
V_fixture_min = 1.3000
V_fixture_max = 1.7000
| time   V(typ)   V(min)   V(max)
0s        581mV      619.4mV    586.2mV
600ps     582.4mV    619.8mV    660.9mV
800ps     662mV      619.8mV    1.31V
1.1ns     1.395V     676.1mV    2.557V
1.3ns     1.917V     958.2mV    2.827V
1.5ns     2.326V     1.187V     2.889V
1.7ns     2.453V     1.403V     2.904V
2.2ns     2.53V      1.902V     2.914V
2.5ns     2.535V     2.012V     2.916V
5ns       2.54V      2.097V     2.918V
[Falling Waveform]
R_fixture = 25.0000
V_fixture = 1.5000
V_fixture_min = 1.3000
V_fixture_max = 1.7000
| time   V(typ)   V(min)   V(max)
0s        2.541V     2.098V     2.918V
700ps     2.541V     2.098V     2.861V
800ps     2.541V     2.098V     2.536V
900ps     2.517V     2.098V     1.833V
1ns       2.326V     2.098V     1.431V
1.2ns     1.47V      2.099V     1.065V
1.5ns     1.002V     1.745V     643.9mV
1.9ns     669.5mV    1.113V     597.2mV
2.8ns     584.8mV    688.5mV    588.1mV
5ns       581.5mV    620.2mV    586.7mV
[Falling Waveform]
R_fixture = 25.0000
V_fixture = 0.000
| time   V(typ)   V(min)   V(max)
0s        1.757V     1.2V       2.2V
700ps     1.757V     1.2V       2.099V
800ps     1.756V     1.2V       1.569V
900ps     1.695V     1.2V       815.8mV
1ns       1.401V     1.2V       355mV
1.2ns     427.4mV    1.201V     70.29mV
1.4ns     86.47mV    998.5mV    17.77mV
1.7ns     22.51mV    277.9mV    7.462mV
2ns       7.442mV    56.8mV     4.103mV
5ns       336.6uV    356uV      336.4uV
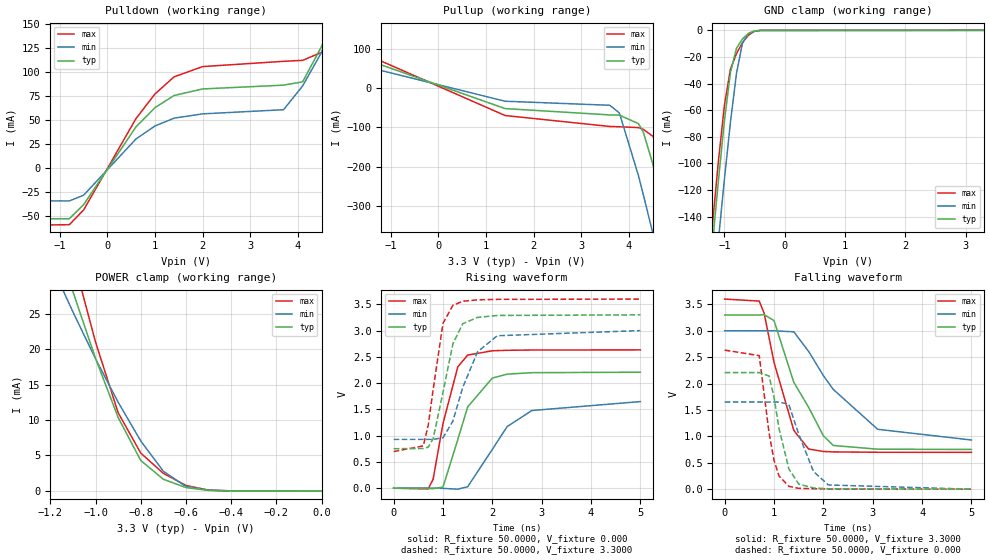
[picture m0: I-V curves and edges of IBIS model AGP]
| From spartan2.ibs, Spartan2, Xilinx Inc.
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|   Model AGP
[Model]   AGP
Model_type   I/O
Polarity   Non-Inverting
Enable   Active-Low
Vinl =   1.120V
Vinh =   1.520V
| Vmeas depends on rising or falling edge, select one of the following:
| For rising edge:
|Vmeas =   0.940V
| For falling edge:
|Vmeas =   2.00V
Cref =  10.0000pF
Rref =  50.0000
| Vref depends on rising or falling edge, select one of the following:
| For rising edge:
|Vref =   0.00V
| For falling edge:
|Vref =   3.30V
C_comp   6.5000pF   5.0000pF   8.0000pF
[Temperature Range]   27.0000   100.0000   0.000
[Voltage Range]   3.3000V   3.0000V   3.6000V
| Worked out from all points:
|   slope of the pulldown table from 0 to 0.495 V, typ, clamps not added: 13.7 ohm
|   slope of the pullup table from 0 to 0.495 V, typ, clamps not added: 21.7 ohm
|   GND clamp passes 1 mA (typ) near -0.53 V on its own axis
|   POWER clamp passes 1 mA (typ) near -0.64 V on its own axis
|   rising waveform, R_fixture 50.0000, V_fixture 0.000: 20-80 % time 499ps typ, 771ps min, 358ps max; typ from 0 V to 2.21 V
|   rising waveform, R_fixture 50.0000, V_fixture 3.3000: 20-80 % time 348ps typ, 473ps min, 265ps max; typ from 0.751 V to 3.3 V
|   falling waveform, R_fixture 50.0000, V_fixture 3.3000: 20-80 % time 695ps typ, 1.06ns min, 488ps max; typ from 3.3 V to 0.752 V
|   falling waveform, R_fixture 50.0000, V_fixture 0.000: 20-80 % time 290ps typ, 392ps min, 245ps max; typ from 2.21 V to 0 V
[Pulldown]
| voltage   I(typ)   I(min)   I(max)
-3.3V     -53.26mA   -34.66mA   -60.95mA
-800mV    -53.26mA   -34.66mA   -59.46mA
-500mV    -38.59mA   -28.75mA   -44.11mA
600mV     42.54mA    29.94mA    51.16mA
1V        62.63mA    43.47mA    76.94mA
1.4V      75.27mA    51.64mA    94.7mA
2V        82.09mA    56.09mA    105.4mA
3.7V      86.04mA    60.44mA    110.9mA
4.1V      89.49mA    85.22mA    111.9mA
4.5V      126.6mA    120.5mA    120.3mA
4.9V      177.6mA    159.9mA    174.2mA
6.6V      407.8mA    336.3mA    452.6mA
[Pullup]
| voltage   I(typ)   I(min)   I(max)
-3.3V     137.4mA    116.7mA    152.3mA
-1.5V     71.46mA    53.37mA    84.23mA
1.4V      -52.42mA   -33.71mA   -70.06mA
3.6V      -68.53mA   -44mA      -97.91mA
3.8V      -69.08mA   -63.63mA   -98.58mA
4.2V      -90.62mA   -222.7mA   -100.8mA
4.3V      -111.5mA   -270.4mA   -105mA
4.5V      -192.3mA   -368.3mA   -122.6mA
4.7V      -290.4mA   -468.2mA   -157.6mA
4.9V      -393.7mA   -569.2mA   -241mA
5.1V      -499.3mA   -670.9mA   -340.5mA
6.6V      -1.31A     -1.442A    -1.157A
[GND_clamp]
| voltage   I(typ)   I(min)   I(max)
-3.3V     -1.286A    -1.272A    -1.289A
-1.2V     -161.8mA   -205.3mA   -146.7mA
-1.1V     -113.2mA   -157.8mA   -98.56mA
-1V       -68.04mA   -112mA     -56.27mA
-900mV    -31.6mA    -69.09mA   -29.2mA
-800mV    -13.5mA    -32.34mA   -17.42mA
-700mV    -6.408mA   -9.455mA   -9.303mA
-600mV    -2.237mA   -2.349mA   -3.538mA
-500mV    -423.5uA   -545.3uA   -698.2uA
-400mV    -42.44uA   -91.25uA   -59.93uA
3.3V      523.9pA    1.466uA    349.2pA
[POWER_clamp]
| voltage   I(typ)   I(min)   I(max)
-3.3V     276.4mA    201.2mA    346.2mA
-1.2V     38.21mA    32.25mA    46.01mA
-1.1V     28.13mA    25.27mA    33mA
-1V       18.72mA    18.66mA    21.02mA
-900mV    10.37mA    12.52mA    11.04mA
-800mV    4.3mA      7.057mA    5.343mA
-700mV    1.647mA    2.774mA    2.48mA
-600mV    473.1uA    621.1uA    767.7uA
-500mV    71.72uA    106uA      114.9uA
-400mV    5.959uA    14.29uA    7.91uA
0V        523.9pA    8.324nA    407.5pA
[Ramp]
| variable   typ   min   max
dV/dt_r   1.3242/0.4971n   0.9888/0.7709n   1.5792/0.3468n
dV/dt_f   1.5287/0.6912n   1.2413/1.0958n   1.7416/0.4938n
R_load = 50.0000
[Rising Waveform]
R_fixture = 50.0000
V_fixture = 0.000
| time   V(typ)   V(min)   V(max)
0s        0V         0V         0V
700ps     -3.8mV     862.5uV    -14.13mV
800ps     -9.51mV    982.4uV    170.4mV
1ns       21.17mV    -3.713mV   1.232V
1.3ns     925mV      -18.54mV   2.309V
1.5ns     1.547V     27.03mV    2.533V
2ns       2.096V     739.6mV    2.615V
2.3ns     2.17V      1.172V     2.624V
2.8ns     2.198V     1.478V     2.629V
5ns       2.207V     1.648V     2.632V
[Rising Waveform]
R_fixture = 50.0000
V_fixture = 3.3000
V_fixture_min = 3.0000
V_fixture_max = 3.6000
| time   V(typ)   V(min)   V(max)
0s        751.2mV    928.2mV    696.8mV
600ps     755.2mV    928.8mV    804.3mV
700ps     780.4mV    929mV      1.195V
800ps     939.8mV    928.5mV    1.876V
1ns       1.823V     959.2mV    3.139V
1.2ns     2.746V     1.276V     3.479V
1.4ns     3.13V      1.916V     3.558V
1.7ns     3.25V      2.596V     3.584V
2.1ns     3.287V     2.901V     3.593V
5ns       3.299V     2.999V     3.599V
[Falling Waveform]
R_fixture = 50.0000
V_fixture = 3.3000
V_fixture_min = 3.0000
V_fixture_max = 3.6000
| time   V(typ)   V(min)   V(max)
0s        3.3V       3V         3.6V
700ps     3.299V     3V         3.562V
800ps     3.303V     3V         3.33V
1ns       3.192V     2.999V     2.401V
1.4ns     2.024V     2.98V      1.114V
1.7ns     1.552V     2.61V      761.6mV
2ns       1.011V     2.151V     714.3mV
2.2ns     828.1mV    1.89V      706mV
3.1ns     757.3mV    1.134V     699.1mV
5ns       752.1mV    931.2mV    697.4mV
[Falling Waveform]
R_fixture = 50.0000
V_fixture = 0.000
| time   V(typ)   V(min)   V(max)
0s        2.208V     1.651V     2.633V
700ps     2.208V     1.651V     2.529V
900ps     2.143V     1.65V      1.058V
1ns       1.738V     1.651V     545.8mV
1.1ns     1.153V     1.651V     251.5mV
1.3ns     385.2mV    1.607V     54.49mV
1.5ns     96.57mV    1.042V     16.26mV
1.8ns     23.66mV    334.1mV    8.044mV
2.1ns     8.124mV    79.81mV    4.419mV
5ns       448.4uV    515.5uV    436.4uV
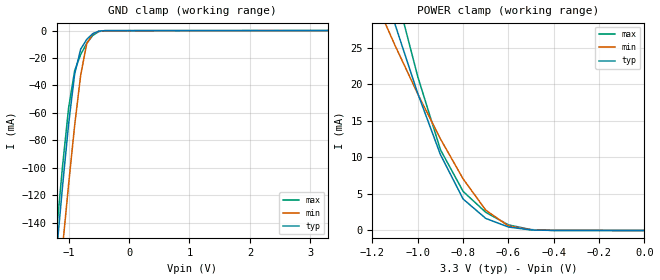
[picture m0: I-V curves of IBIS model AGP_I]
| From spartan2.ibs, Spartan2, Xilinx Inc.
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|   Model AGP_I
[Model]   AGP_I
Model_type   Input
Polarity   Non-Inverting
Vinl =   1.120V
Vinh =   1.520V
C_comp   6.5000pF   5.0000pF   8.0000pF
[Temperature Range]   27.0000   100.0000   0.000
[Voltage Range]   3.3000V   3.0000V   3.6000V
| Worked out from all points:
|   GND clamp passes 1 mA (typ) near -0.53 V on its own axis
|   POWER clamp passes 1 mA (typ) near -0.64 V on its own axis
[GND_clamp]
| voltage   I(typ)   I(min)   I(max)
-3.3V     -1.286A    -1.272A    -1.289A
-1.2V     -161.8mA   -205.3mA   -146.7mA
-1.1V     -113.2mA   -157.8mA   -98.56mA
-1V       -68.04mA   -112mA     -56.27mA
-900mV    -31.6mA    -69.09mA   -29.2mA
-800mV    -13.5mA    -32.34mA   -17.42mA
-700mV    -6.408mA   -9.455mA   -9.303mA
-600mV    -2.237mA   -2.349mA   -3.538mA
-500mV    -423.5uA   -545.3uA   -698.2uA
-400mV    -42.44uA   -91.25uA   -59.93uA
3.3V      523.9pA    1.466uA    349.2pA
[POWER_clamp]
| voltage   I(typ)   I(min)   I(max)
-3.3V     276.4mA    201.2mA    346.2mA
-1.2V     38.21mA    32.25mA    46.01mA
-1.1V     28.13mA    25.27mA    33mA
-1V       18.72mA    18.66mA    21.02mA
-900mV    10.37mA    12.52mA    11.04mA
-800mV    4.3mA      7.057mA    5.343mA
-700mV    1.647mA    2.774mA    2.48mA
-600mV    473.1uA    621.1uA    767.7uA
-500mV    71.72uA    106uA      114.9uA
-400mV    5.959uA    14.29uA    7.91uA
0V        523.9pA    8.324nA    407.5pA
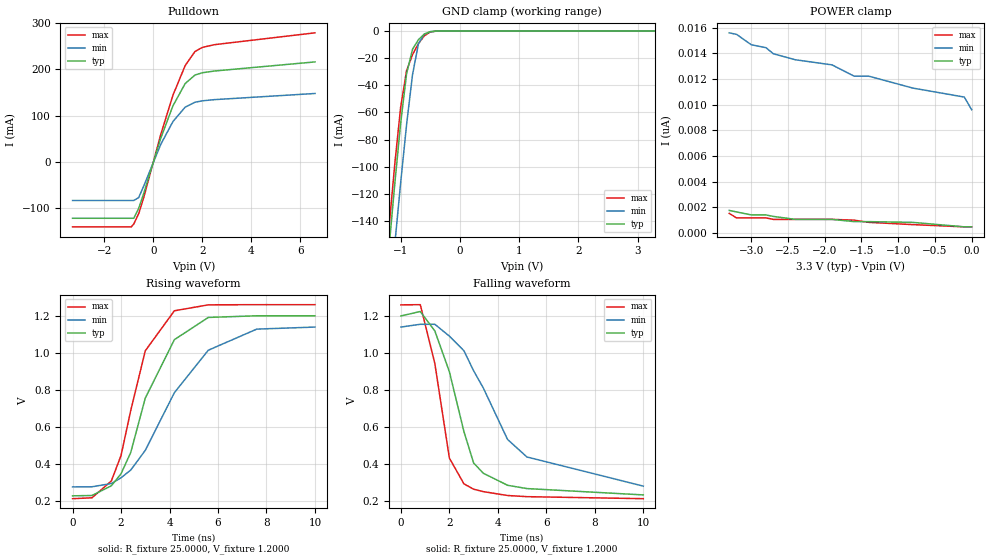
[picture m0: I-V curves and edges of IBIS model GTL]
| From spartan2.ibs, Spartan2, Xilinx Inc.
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|   Model GTL
[Model]   GTL
Model_type   I/O_open_drain
Polarity   Non-Inverting
Enable   Active-Low
Vinl =   0.750V
Vinh =   0.850V
Vmeas =   0.8000V
Cref =  0.000F
Rref =  25.0000
Vref =   1.2000V
C_comp   6.5000pF   5.0000pF   8.0000pF
[Temperature Range]   27.0000   100.0000   0.000
[Voltage Range]   3.3000V   3.0000V   3.6000V
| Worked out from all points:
|   slope of the pulldown table from 0 to 0.495 V, typ, clamps not added: 6.14 ohm
|   GND clamp passes 1 mA (typ) near -0.53 V on its own axis
|   rising waveform, R_fixture 25.0000, V_fixture 1.2000: 20-80 % time 1.57ns typ, 2.36ns min, 1.24ns max; typ from 0.227 V to 1.2 V
|   falling waveform, R_fixture 25.0000, V_fixture 1.2000: 20-80 % time 1.16ns typ, 2.3ns min, 838ps max; typ from 1.2 V to 0.233 V
[Pulldown]
| voltage   I(typ)   I(min)   I(max)
-3.3V     -122.3mA   -83.78mA   -140.9mA
-900mV    -122.3mA   -83.78mA   -140.9mA
-800mV    -122.3mA   -83.78mA   -134.7mA
-600mV    -100.8mA   -77.55mA   -112.3mA
-400mV    -69.54mA   -53.28mA   -78.56mA
300mV     50.82mA    37.52mA    58.82mA
800mV     121.4mA    87.27mA    144.3mA
1.3V      169.5mA    118.5mA    208.6mA
1.7V      188mA      129.1mA    239mA
2V        192.9mA    132.1mA    247.8mA
2.5V      196.7mA    134.7mA    253.8mA
6.6V      216.4mA    148mA      279.4mA
[GND_clamp]
| voltage   I(typ)   I(min)   I(max)
-3.3V     -1.286A    -1.272A    -1.289A
-1.2V     -161.8mA   -205.3mA   -146.7mA
-1.1V     -113.2mA   -157.8mA   -98.56mA
-1V       -68.04mA   -112mA     -56.27mA
-900mV    -31.6mA    -69.09mA   -29.2mA
-800mV    -13.5mA    -32.34mA   -17.42mA
-700mV    -6.408mA   -9.455mA   -9.303mA
-600mV    -2.237mA   -2.349mA   -3.538mA
-500mV    -423.5uA   -545.3uA   -698.3uA
-400mV    -42.44uA   -91.26uA   -59.96uA
3.3V      407.5pA    10.83nA    27.42nA
[POWER_clamp]
| voltage   I(typ)   I(min)   I(max)
-3.3V     1.746nA    15.6nA     1.513nA
-3.2V     1.63nA     15.48nA    1.164nA
-3V       1.397nA    14.67nA    1.164nA
-2.8V     1.397nA    14.44nA    1.164nA
-2.7V     1.281nA    13.97nA    1.048nA
-2.4V     1.048nA    13.5nA     1.048nA
-1.9V     1.048nA    13.1nA     1.048nA
-1.6V     873.1pA    12.22nA    989.5pA
-1.4V     873.1pA    12.22nA    814.9pA
-800mV    814.9pA    11.29nA    640.3pA
-100mV    465.7pA    10.59nA    465.7pA
0V        465.7pA    9.604nA    465.7pA
[Ramp]
| variable   typ   min   max
dV/dt_r   1.5759/1.1814n   1.3140/1.7172n   1.7763/0.9390n
dV/dt_f   1.5607/2.0637n   1.2287/3.3958n   1.7737/1.3701n
R_load = 25.0000
[Rising Waveform]
R_fixture = 25.0000
V_fixture = 1.2000
V_fixture_min = 1.1400
V_fixture_max = 1.2600
| time   V(typ)   V(min)   V(max)
0s        226.7mV    275mV      211.3mV
800ps     228.5mV    275.6mV    216mV
1.6ns     280.9mV    293.1mV    306.8mV
2ns       346mV      324.2mV    444.7mV
2.4ns     460.9mV    365.9mV    687.6mV
3ns       754.5mV    472.2mV    1.01V
4.2ns     1.07V      783.8mV    1.226V
5.6ns     1.19V      1.013V     1.258V
7.6ns     1.199V     1.127V     1.259V
10ns      1.199V     1.138V     1.259V
[Falling Waveform]
R_fixture = 25.0000
V_fixture = 1.2000
V_fixture_min = 1.1400
V_fixture_max = 1.2600
| time   V(typ)   V(min)   V(max)
0s        1.2V       1.14V      1.26V
800ps     1.224V     1.155V     1.261V
1.4ns     1.119V     1.155V     943.2mV
2ns       898.8mV    1.091V     432mV
2.6ns     575.5mV    1.012V     292.9mV
3ns       405.7mV    903.8mV    264mV
3.4ns     350.2mV    810.8mV    250.8mV
4.4ns     285.1mV    532.7mV    229.9mV
5.2ns     267.3mV    438mV      223.6mV
10ns      233.1mV    280.5mV    212.7mV
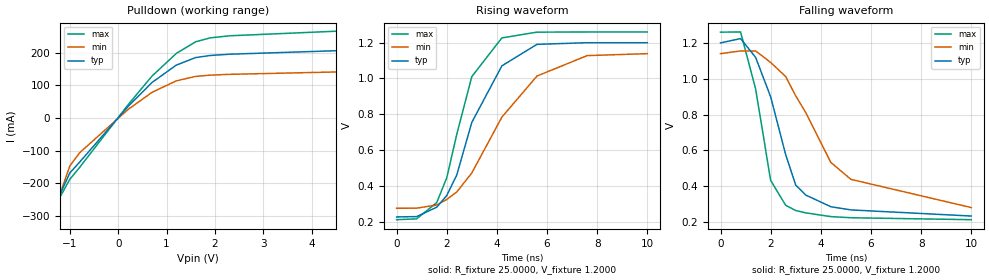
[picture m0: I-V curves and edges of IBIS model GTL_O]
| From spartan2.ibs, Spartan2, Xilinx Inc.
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|   Model GTL_O
[Model]   GTL_O
Model_type   Open_drain
Polarity   Non-Inverting
Vmeas =   0.8000V
Cref =  0.000F
Rref =  25.0000
Vref =   1.2000V
C_comp   6.5000pF   5.0000pF   8.0000pF
[Temperature Range]   27.0000   100.0000   0.000
[Voltage Range]   3.3000V   3.0000V   3.6000V
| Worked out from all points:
|   slope of the pulldown table from 0 to 0.495 V, typ, clamps not added: 6.14 ohm
|   rising waveform, R_fixture 25.0000, V_fixture 1.2000: 20-80 % time 1.57ns typ, 2.36ns min, 1.24ns max; typ from 0.227 V to 1.2 V
|   falling waveform, R_fixture 25.0000, V_fixture 1.2000: 20-80 % time 1.16ns typ, 2.3ns min, 838ps max; typ from 1.2 V to 0.233 V
[Pulldown]
| voltage   I(typ)   I(min)   I(max)
-3.3V     -1.283A    -1.271A    -1.286A
-1.7V     -429.2mA   -457mA     -420mA
-1.5V     -329.8mA   -359.5mA   -322.9mA
-1V       -168.6mA   -147.2mA   -188mA
-800mV    -135.8mA   -107mA     -152.1mA
200mV     34.51mA    25.6mA     39.76mA
700mV     108.9mA    78.71mA    128.7mA
1.2V      162mA      113.8mA    197.8mA
1.6V      185.2mA    127.5mA    233.6mA
1.9V      191.6mA    131.3mA    245.6mA
2.3V      195.5mA    133.8mA    252mA
6.6V      216.4mA    148mA      279.4mA
[Ramp]
| variable   typ   min   max
dV/dt_r   1.5759/1.1814n   1.3140/1.7172n   1.7763/0.9390n
dV/dt_f   1.5607/2.0637n   1.2287/3.3958n   1.7737/1.3701n
R_load = 25.0000
[Rising Waveform]
R_fixture = 25.0000
V_fixture = 1.2000
V_fixture_min = 1.1400
V_fixture_max = 1.2600
| time   V(typ)   V(min)   V(max)
0s        226.7mV    275mV      211.3mV
800ps     228.5mV    275.6mV    216mV
1.6ns     280.9mV    293.1mV    306.8mV
2ns       346mV      324.2mV    444.7mV
2.4ns     460.9mV    365.9mV    687.6mV
3ns       754.5mV    472.2mV    1.01V
4.2ns     1.07V      783.8mV    1.226V
5.6ns     1.19V      1.013V     1.258V
7.6ns     1.199V     1.127V     1.259V
10ns      1.199V     1.138V     1.259V
[Falling Waveform]
R_fixture = 25.0000
V_fixture = 1.2000
V_fixture_min = 1.1400
V_fixture_max = 1.2600
| time   V(typ)   V(min)   V(max)
0s        1.2V       1.14V      1.26V
800ps     1.224V     1.155V     1.261V
1.4ns     1.119V     1.155V     943.2mV
2ns       898.8mV    1.091V     432mV
2.6ns     575.5mV    1.012V     292.9mV
3ns       405.7mV    903.8mV    264mV
3.4ns     350.2mV    810.8mV    250.8mV
4.4ns     285.1mV    532.7mV    229.9mV
5.2ns     267.3mV    438mV      223.6mV
10ns      233.1mV    280.5mV    212.7mV
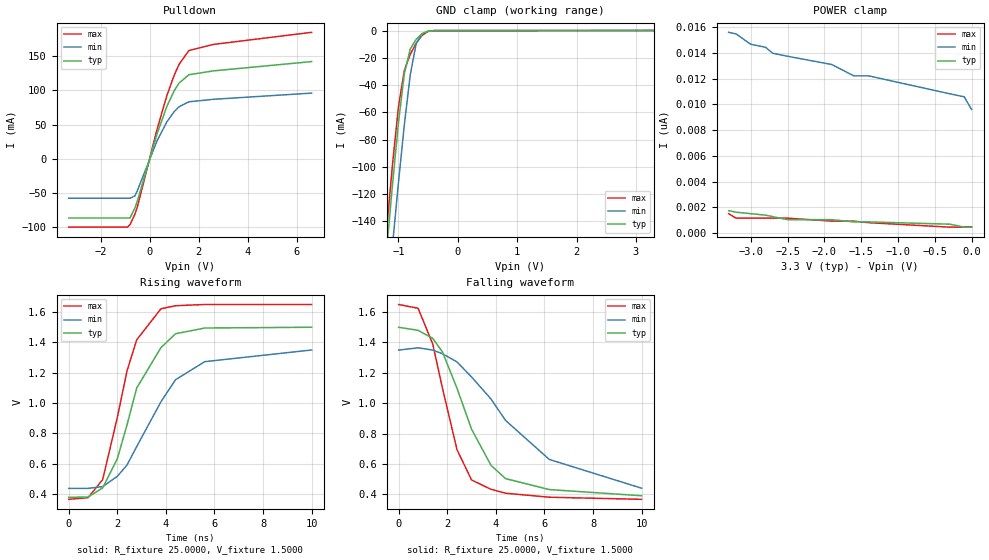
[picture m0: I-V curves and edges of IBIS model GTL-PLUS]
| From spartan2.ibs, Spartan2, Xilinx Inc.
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|   Model GTL-PLUS
[Model]   GTL-PLUS
Model_type   I/O_open_drain
Polarity   Non-Inverting
Enable   Active-Low
Vinl =   0.900V
Vinh =   1.100V
Vmeas =   1.0000V
Cref =  0.000F
Rref =  25.0000
Vref =   1.5000V
C_comp   6.5000pF   5.0000pF   8.0000pF
[Temperature Range]   27.0000   100.0000   0.000
[Voltage Range]   3.3000V   3.0000V   3.6000V
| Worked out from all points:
|   slope of the pulldown table from 0 to 0.495 V, typ, clamps not added: 8.65 ohm
|   GND clamp passes 1 mA (typ) near -0.53 V on its own axis
|   rising waveform, R_fixture 25.0000, V_fixture 1.5000: 20-80 % time 1.42ns typ, 2ns min, 1.11ns max; typ from 0.377 V to 1.5 V
|   falling waveform, R_fixture 25.0000, V_fixture 1.5000: 20-80 % time 1.74ns typ, 3.26ns min, 1.16ns max; typ from 1.5 V to 0.391 V
[Pulldown]
| voltage   I(typ)   I(min)   I(max)
-3.3V     -86.6mA    -57.72mA   -100mA
-900mV    -86.6mA    -57.72mA   -100mA
-800mV    -86.6mA    -57.72mA   -96.28mA
-600mV    -72.01mA   -54.31mA   -81.08mA
-500mV    -61.76mA   -46.43mA   -70.35mA
300mV     36.37mA    26.12mA    42.87mA
700mV     76.56mA    53.94mA    92.26mA
1V        99.44mA    69.02mA    122.2mA
1.2V      110.8mA    76.15mA    138.2mA
1.6V      123mA      83.36mA    158.4mA
2.6V      128.6mA    87.02mA    167.3mA
6.6V      142.2mA    96.1mA     185mA
[GND_clamp]
| voltage   I(typ)   I(min)   I(max)
-3.3V     -1.286A    -1.272A    -1.289A
-1.2V     -161.8mA   -205.3mA   -146.7mA
-1.1V     -113.2mA   -157.8mA   -98.56mA
-1V       -68.04mA   -112mA     -56.27mA
-900mV    -31.6mA    -69.09mA   -29.2mA
-800mV    -13.5mA    -32.35mA   -17.42mA
-700mV    -6.408mA   -9.456mA   -9.303mA
-600mV    -2.237mA   -2.349mA   -3.538mA
-500mV    -423.5uA   -545.4uA   -698.2uA
-400mV    -42.44uA   -91.29uA   -59.93uA
3.3V      465.7pA    42.32nA    407.5pA
[POWER_clamp]
| voltage   I(typ)   I(min)   I(max)
-3.3V     1.746nA    15.6nA     1.513nA
-3.2V     1.63nA     15.48nA    1.164nA
-3V       1.513nA    14.67nA    1.164nA
-2.8V     1.397nA    14.44nA    1.164nA
-2.7V     1.281nA    13.97nA    1.164nA
-2.5V     1.048nA    13.74nA    1.164nA
-1.9V     1.048nA    13.1nA     931.3pA
-1.6V     873.1pA    12.22nA    931.3pA
-1.4V     873.1pA    12.22nA    814.9pA
-300mV    698.5pA    10.83nA    465.7pA
-100mV    465.7pA    10.59nA    465.7pA
0V        465.7pA    9.604nA    465.7pA
[Ramp]
| variable   typ   min   max
dV/dt_r   1.4203/1.0853n   1.1130/1.5802n   1.6405/0.8747n
dV/dt_f   1.3900/2.7762n   0.9630/4.0841n   1.6339/1.8878n
R_load = 25.0000
[Rising Waveform]
R_fixture = 25.0000
V_fixture = 1.5000
V_fixture_min = 1.3500
V_fixture_max = 1.6500
| time   V(typ)   V(min)   V(max)
0s        377.2mV    436.3mV    364.2mV
800ps     379.8mV    436.5mV    375.2mV
1.4ns     439.5mV    448.2mV    494.5mV
2ns       630.7mV    515.5mV    902.1mV
2.4ns     854.2mV    590.1mV    1.21V
2.8ns     1.098V     712mV      1.416V
3.8ns     1.365V     1.008V     1.621V
4.4ns     1.456V     1.153V     1.641V
5.6ns     1.494V     1.272V     1.649V
10ns      1.499V     1.349V     1.649V
[Falling Waveform]
R_fixture = 25.0000
V_fixture = 1.5000
V_fixture_min = 1.3500
V_fixture_max = 1.6500
| time   V(typ)   V(min)   V(max)
0s        1.5V       1.35V      1.65V
800ps     1.48V      1.365V     1.625V
1.4ns     1.427V     1.35V      1.391V
1.8ns     1.338V     1.326V     1.101V
2.4ns     1.099V     1.272V     694.7mV
3ns       829.1mV    1.173V     494.9mV
3.8ns     591.5mV    1.028V     433.4mV
4.4ns     503.7mV    886.8mV    407.7mV
6.2ns     431.7mV    630.1mV    381.3mV
10ns      390.9mV    440.6mV    367.4mV
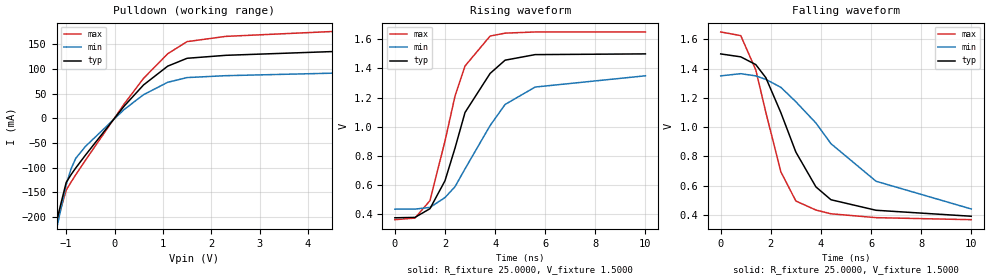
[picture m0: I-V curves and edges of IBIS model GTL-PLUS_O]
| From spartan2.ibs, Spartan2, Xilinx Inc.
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|   Model GTL-PLUS_O
[Model]   GTL-PLUS_O
Model_type   Open_drain
Polarity   Non-Inverting
Vmeas =   1.00V
Cref =  0.000F
Rref =  25.00
Vref =   1.50V
C_comp   6.5000pF   5.0000pF   8.0000pF
[Temperature Range]   27.0000   100.0000   0.000
[Voltage Range]   3.3000V   3.0000V   3.6000V
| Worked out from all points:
|   slope of the pulldown table from 0 to 0.495 V, typ, clamps not added: 8.65 ohm
|   rising waveform, R_fixture 25.0000, V_fixture 1.5000: 20-80 % time 1.42ns typ, 2ns min, 1.11ns max; typ from 0.377 V to 1.5 V
|   falling waveform, R_fixture 25.0000, V_fixture 1.5000: 20-80 % time 1.74ns typ, 3.26ns min, 1.16ns max; typ from 1.5 V to 0.391 V
[Pulldown]
| voltage   I(typ)   I(min)   I(max)
-3.3V     -1.288A    -1.274A    -1.291A
-1.5V     -326.3mA   -358.7mA   -316.4mA
-1V       -129.7mA   -134.3mA   -145.1mA
-900mV    -114mA     -102.2mA   -129.2mA
-800mV    -100.1mA   -80.56mA   -113.7mA
-600mV    -74.25mA   -56.66mA   -84.62mA
200mV     24.8mA     17.89mA    29.08mA
600mV     67.49mA    47.78mA    80.85mA
1.1V      105.5mA    72.88mA    130.6mA
1.5V      121.4mA    82.37mA    155.1mA
2.3V      127.4mA    86.22mA    165.7mA
6.6V      142.2mA    96.1mA     185mA
[Ramp]
| variable   typ   min   max
dV/dt_r   1.4203/1.0853n   1.1130/1.5802n   1.6405/0.8747n
dV/dt_f   1.3900/2.7762n   0.9630/4.0841n   1.6339/1.8878n
R_load = 25.0000
[Rising Waveform]
R_fixture = 25.0000
V_fixture = 1.5000
V_fixture_min = 1.3500
V_fixture_max = 1.6500
| time   V(typ)   V(min)   V(max)
0s        377.2mV    436.3mV    364.2mV
800ps     379.8mV    436.5mV    375.2mV
1.4ns     439.5mV    448.2mV    494.5mV
2ns       630.7mV    515.5mV    902.1mV
2.4ns     854.2mV    590.1mV    1.21V
2.8ns     1.098V     712mV      1.416V
3.8ns     1.365V     1.008V     1.621V
4.4ns     1.456V     1.153V     1.641V
5.6ns     1.494V     1.272V     1.649V
10ns      1.499V     1.349V     1.649V
[Falling Waveform]
R_fixture = 25.0000
V_fixture = 1.5000
V_fixture_min = 1.3500
V_fixture_max = 1.6500
| time   V(typ)   V(min)   V(max)
0s        1.5V       1.35V      1.65V
800ps     1.48V      1.365V     1.625V
1.4ns     1.427V     1.35V      1.391V
1.8ns     1.338V     1.326V     1.101V
2.4ns     1.099V     1.272V     694.7mV
3ns       829.1mV    1.173V     494.9mV
3.8ns     591.5mV    1.028V     433.4mV
4.4ns     503.7mV    886.8mV    407.7mV
6.2ns     431.7mV    630.1mV    381.3mV
10ns      390.9mV    440.6mV    367.4mV
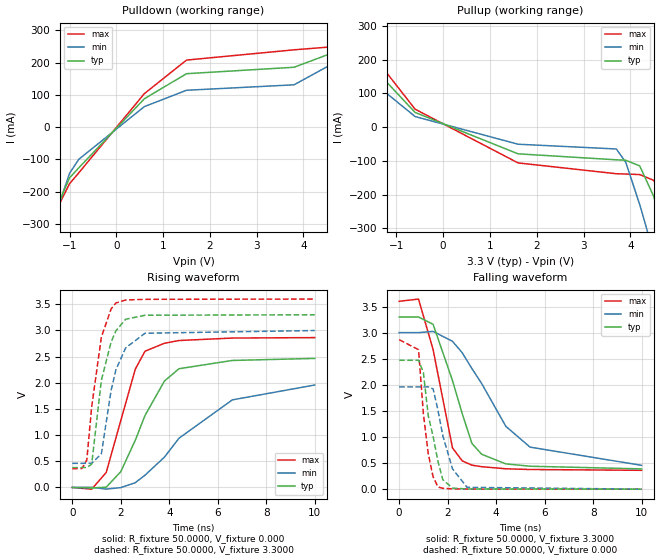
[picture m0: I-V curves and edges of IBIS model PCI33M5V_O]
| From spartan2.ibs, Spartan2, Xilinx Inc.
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|   Model PCI33M5V_O
[Model]   PCI33M5V_O
Model_type   Output
Polarity   Non-Inverting
Vmeas =   1.5000V
Cref =  50.0000pF
Rref =   1.0000M
Vref =  0.000V
C_comp   6.5000pF   5.0000pF   8.0000pF
[Temperature Range]   27.0000   100.0000   0.000
[Voltage Range]   3.3000V   3.0000V   3.6000V
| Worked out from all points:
|   slope of the pulldown table from 0 to 0.495 V, typ, clamps not added: 6.65 ohm
|   slope of the pullup table from 0 to 0.495 V, typ, clamps not added: 15.7 ohm
|   rising waveform, R_fixture 50.0000, V_fixture 0.000: 20-80 % time 1.5ns typ, 2.71ns min, 1.02ns max; typ from 0 V to 2.46 V
|   rising waveform, R_fixture 50.0000, V_fixture 3.3000: 20-80 % time 649ps typ, 684ps min, 559ps max; typ from 0.379 V to 3.3 V
|   falling waveform, R_fixture 50.0000, V_fixture 3.3000: 20-80 % time 1.14ns typ, 2.2ns min, 844ps max; typ from 3.3 V to 0.388 V
|   falling waveform, R_fixture 50.0000, V_fixture 0.000: 20-80 % time 560ps typ, 625ps min, 386ps max; typ from 2.47 V to 0 V
[Pulldown]
| voltage   I(typ)   I(min)   I(max)
-3.3V     -1.283A    -1.271A    -1.286A
-1.5V     -328.3mA   -358.8mA   -320.4mA
-1V       -157.3mA   -143.3mA   -175.7mA
-800mV    -125.9mA   -99.46mA   -141.3mA
600mV     88.12mA    63.71mA    104mA
1.5V      165.7mA    114.3mA    207.9mA
3.8V      185.7mA    131.3mA    239.8mA
4.5V      223.7mA    187mA      247.8mA
4.9V      274.3mA    226.6mA    299.3mA
5.3V      328.6mA    268.6mA    363.4mA
5.7V      384.4mA    311.7mA    429.9mA
6.6V      505.5mA    403.9mA    577.9mA
[Pullup]
| voltage   I(typ)   I(min)   I(max)
-3.3V     447.6mA    344.1mA    537.5mA
-2.7V     358.3mA    273.6mA    429.8mA
-2.3V     295.4mA    224.1mA    355.1mA
-600mV    43.62mA    31.46mA    53.31mA
1.6V      -79.23mA   -50.72mA   -106.2mA
3.7V      -97.01mA   -64.82mA   -138.3mA
3.9V      -98.14mA   -103.8mA   -139.2mA
4.2V      -115mA     -229.6mA   -140.8mA
4.5V      -206mA     -374.5mA   -158mA
4.9V      -403.9mA   -575.1mA   -261.6mA
5.1V      -509.1mA   -676.8mA   -357.4mA
6.6V      -1.32A     -1.449A    -1.171A
[Ramp]
| variable   typ   min   max
dV/dt_r   1.4790/1.4894n   1.1430/2.5760n   1.7178/1.0217n
dV/dt_f   1.7469/1.1800n   1.4917/2.0700n   1.9432/0.7937n
R_load = 50.0000
[Rising Waveform]
R_fixture = 50.0000
V_fixture = 0.000
| time   V(typ)   V(min)   V(max)
0s        0V         0V         0V
800ps     -11.1mV    1.605mV    -33mV
1.4ns     4.272mV    -31.48mV   286.3mV
2ns       301mV      -3.101mV   1.276V
2.6ns     903.2mV    91.09mV    2.261V
3ns       1.375V     234.1mV    2.603V
3.8ns     2.032V     579.2mV    2.754V
4.4ns     2.268V     939.7mV    2.807V
6.6ns     2.426V     1.673V     2.854V
10ns      2.465V     1.957V     2.863V
[Rising Waveform]
R_fixture = 50.0000
V_fixture = 3.3000
V_fixture_min = 3.0000
V_fixture_max = 3.6000
| time   V(typ)   V(min)   V(max)
0s        378.9mV    460.2mV    359.3mV
400ps     379.5mV    460.4mV    361.4mV
600ps     383mV      461mV      525.9mV
800ps     442mV      461.3mV    1.538V
1.2ns     2.049V     641.4mV    2.873V
1.6ns     2.776V     1.852V     3.408V
1.8ns     2.993V     2.248V     3.525V
2.2ns     3.213V     2.666V     3.581V
3ns       3.29V      2.946V     3.594V
10ns      3.299V     2.998V     3.599V
[Falling Waveform]
R_fixture = 50.0000
V_fixture = 3.3000
V_fixture_min = 3.0000
V_fixture_max = 3.6000
| time   V(typ)   V(min)   V(max)
0s        3.3V       3V         3.6V
800ps     3.299V     3V         3.643V
1.4ns     3.159V     3.023V     2.673V
2.2ns     2.081V     2.834V     790.7mV
2.6ns     1.45V      2.615V     542.5mV
3ns       877.6mV    2.312V     460mV
3.4ns     670.4mV    2.027V     431.2mV
4.4ns     485.1mV    1.204V     390.7mV
5.4ns     439.7mV    805.6mV    376.9mV
10ns      388.5mV    456.5mV    361.4mV
[Falling Waveform]
R_fixture = 50.0000
V_fixture = 0.000
| time   V(typ)   V(min)   V(max)
0s        2.47V      1.959V     2.864V
800ps     2.47V      1.959V     2.674V
1ns       2.236V     1.959V     1.441V
1.2ns     1.409V     1.961V     678.9mV
1.4ns     1.012V     1.921V     237.7mV
1.6ns     534.2mV    1.515V     43.64mV
1.8ns     183.3mV    1.025V     15.88mV
2.2ns     20.59mV    390.8mV    6.13mV
2.8ns     4.561mV    35.56mV    2.547mV
10ns      281.4uV    477.3uV    210.6uV
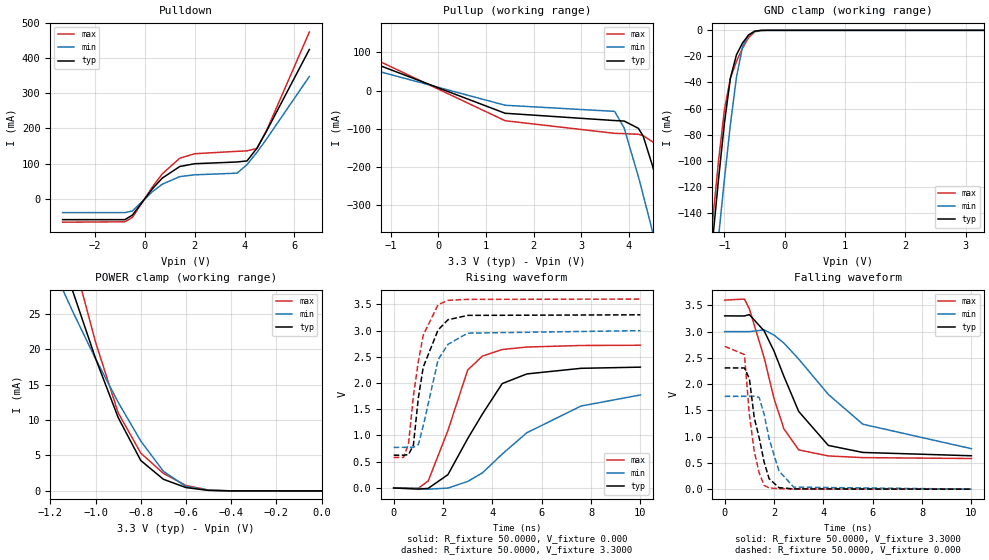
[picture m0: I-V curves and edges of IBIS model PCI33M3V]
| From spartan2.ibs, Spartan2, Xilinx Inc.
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|   Model PCI33M3V
[Model]   PCI33M3V
Model_type   I/O
Polarity   Non-Inverting
Enable   Active-Low
Vinl =   0.900V
Vinh =   1.650V
| Vmeas depends on rising or falling edge, select one of the following:
| For rising edge:
|Vmeas =   0.940V
| For falling edge:
|Vmeas =   2.00V
Cref =  10.0000pF
Rref =  25.0000
| Vref depends on rising or falling edge, select one of the following:
| For rising edge:
|Vref =   0.00V
| For falling edge:
|Vref =   3.30V
C_comp   6.5000pF   5.0000pF   8.0000pF
[Temperature Range]   27.0000   100.0000   0.000
[Voltage Range]   3.3000V   3.0000V   3.6000V
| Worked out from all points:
|   slope of the pulldown table from 0 to 0.495 V, typ, clamps not added: 11.3 ohm
|   slope of the pullup table from 0 to 0.495 V, typ, clamps not added: 19.4 ohm
|   GND clamp passes 1 mA (typ) near -0.51 V on its own axis
|   POWER clamp passes 1 mA (typ) near -0.64 V on its own axis
|   rising waveform, R_fixture 50.0000, V_fixture 0.000: 20-80 % time 1.66ns typ, 2.99ns min, 1.13ns max; typ from 0 V to 2.3 V
|   rising waveform, R_fixture 50.0000, V_fixture 3.3000: 20-80 % time 658ps typ, 711ps min, 598ps max; typ from 0.625 V to 3.3 V
|   falling waveform, R_fixture 50.0000, V_fixture 3.3000: 20-80 % time 1.57ns typ, 2.84ns min, 1.05ns max; typ from 3.3 V to 0.636 V
|   falling waveform, R_fixture 50.0000, V_fixture 0.000: 20-80 % time 564ps typ, 590ps min, 415ps max; typ from 2.31 V to 0 V
[Pulldown]
| voltage   I(typ)   I(min)   I(max)
-3.3V     -59.59mA   -39.63mA   -66.87mA
-800mV    -59.59mA   -39.63mA   -65.71mA
-500mV    -46.71mA   -34.85mA   -53.12mA
300mV     27.92mA    19.96mA    32.99mA
700mV     58.65mA    41.28mA    70.72mA
1.4V      91.61mA    62.87mA    115.2mA
2V        99.56mA    67.99mA    128mA
3.7V      104.5mA    72.65mA    134.8mA
4.1V      107.5mA    97.06mA    136.1mA
4.5V      143.9mA    132.2mA    143.3mA
4.9V      194.6mA    171.6mA    196.4mA
6.6V      424.6mA    347.8mA    474.2mA
[Pullup]
| voltage   I(typ)   I(min)   I(max)
-3.3V     147.4mA    124.4mA    163.8mA
-1.5V     78.26mA    58.57mA    92.03mA
1.4V      -59.13mA   -38.18mA   -78.64mA
3.7V      -78.19mA   -54.2mA    -111.6mA
3.9V      -79.49mA   -97.57mA   -112.4mA
4.2V      -98.59mA   -225.3mA   -114.1mA
4.3V      -118.9mA   -272.8mA   -117.6mA
4.5V      -198.1mA   -370.5mA   -134mA
4.7V      -294.7mA   -470.3mA   -167.8mA
4.9V      -397.4mA   -571.2mA   -249.8mA
5.1V      -502.7mA   -672.9mA   -347.5mA
6.6V      -1.313A    -1.445A    -1.162A
[GND_clamp]
| voltage   I(typ)   I(min)   I(max)
-3.3V     -1.286A    -1.273A    -1.289A
-1.2V     -163.3mA   -206.7mA   -148.3mA
-1.1V     -115.2mA   -159.6mA   -101mA
-1V       -71.04mA   -114.2mA   -60.78mA
-900mV    -36.42mA   -71.86mA   -36.53mA
-800mV    -18.72mA   -35.86mA   -23.84mA
-700mV    -9.715mA   -12.62mA   -13.63mA
-600mV    -3.608mA   -3.649mA   -5.602mA
-500mV    -692.7uA   -854.2uA   -1.156mA
-400mV    -68.48uA   -138.7uA   -98.54uA
-300mV    -4.365uA   -16.73uA   -4.626uA
3.3V      1.106nA    1.475uA    37.54nA
[POWER_clamp]
| voltage   I(typ)   I(min)   I(max)
-3.3V     276.4mA    201.2mA    346.2mA
-1.2V     38.21mA    32.25mA    46.01mA
-1.1V     28.13mA    25.27mA    33mA
-1V       18.72mA    18.66mA    21.02mA
-900mV    10.37mA    12.52mA    11.04mA
-800mV    4.3mA      7.057mA    5.343mA
-700mV    1.647mA    2.774mA    2.48mA
-600mV    473.1uA    621.1uA    767.7uA
-500mV    71.72uA    106uA      114.9uA
-400mV    5.96uA     14.29uA    7.91uA
0V        1.106nA    16.88nA    756.7pA
[Ramp]
| variable   typ   min   max
dV/dt_r   1.3812/1.6793n   1.0212/2.7825n   1.6314/1.1743n
dV/dt_f   1.5983/1.5591n   1.2952/2.6998n   1.8097/1.0214n
R_load = 50.0000
[Rising Waveform]
R_fixture = 50.0000
V_fixture = 0.000
| time   V(typ)   V(min)   V(max)
0s        0V         0V         0V
1ns       -21.37mV   -4.968mV   -6.56mV
1.4ns     -7.112mV   -22.34mV   133.5mV
2.2ns     254.2mV    -1.69mV    1.095V
3ns       940mV      124.7mV    2.247V
3.6ns     1.411V     288.9mV    2.514V
4.4ns     1.989V     646.6mV    2.638V
5.4ns     2.173V     1.053V     2.685V
7.6ns     2.28V      1.562V     2.715V
10ns      2.302V     1.772V     2.719V
[Rising Waveform]
R_fixture = 50.0000
V_fixture = 3.3000
V_fixture_min = 3.0000
V_fixture_max = 3.6000
| time   V(typ)   V(min)   V(max)
0s        625mV      774mV      581.5mV
400ps     625.4mV    774.1mV    582.9mV
600ps     634.4mV    774.5mV    833.4mV
800ps     817.2mV    774.3mV    1.753V
1ns       1.714V     826.4mV    2.411V
1.2ns     2.304V     1.185V     2.911V
1.8ns     3.01V      2.442V     3.491V
2.2ns     3.204V     2.736V     3.575V
3ns       3.288V     2.95V      3.593V
10ns      3.299V     2.998V     3.599V
[Falling Waveform]
R_fixture = 50.0000
V_fixture = 3.3000
V_fixture_min = 3.0000
V_fixture_max = 3.6000
| time   V(typ)   V(min)   V(max)
0s        3.3V       3V         3.6V
800ps     3.298V     3V         3.62V
1ns       3.324V     3V         3.434V
1.6ns     3.013V     3.033V     2.502V
2ns       2.628V     2.933V     1.724V
2.4ns     2.148V     2.782V     1.149V
3ns       1.48V      2.477V     747.4mV
4.2ns     833.1mV    1.804V     633.1mV
5.6ns     699.5mV    1.237V     600.9mV
10ns      636.2mV    771.3mV    583.8mV
[Falling Waveform]
R_fixture = 50.0000
V_fixture = 0.000
| time   V(typ)   V(min)   V(max)
0s        2.309V     1.768V     2.72V
800ps     2.308V     1.768V     2.564V
1ns       2.106V     1.768V     1.42V
1.2ns     1.355V     1.77V      715.4mV
1.4ns     974mV      1.746V     303.7mV
1.6ns     513.3mV    1.423V     71.11mV
1.8ns     199.7mV    962mV      24.36mV
2.2ns     29.02mV    346.4mV    7.88mV
2.8ns     5.398mV    39.2mV     3.043mV
10ns      293.2uV    457.1uV    223.9uV
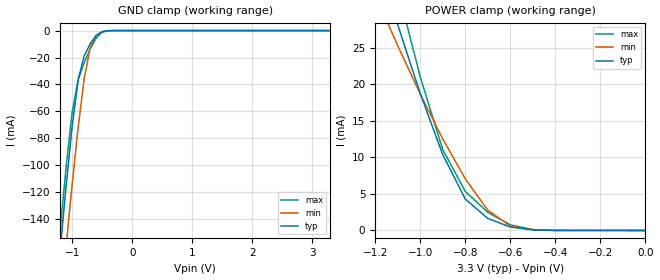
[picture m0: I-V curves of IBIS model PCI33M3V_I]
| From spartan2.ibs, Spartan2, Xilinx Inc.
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|   Model PCI33M3V_I
[Model]   PCI33M3V_I
Model_type   Input
Polarity   Non-Inverting
Vinl =   0.900V
Vinh =   1.650V
C_comp   6.5000pF   5.0000pF   8.0000pF
[Temperature Range]   27.0000   100.0000   0.000
[Voltage Range]   3.3000V   3.0000V   3.6000V
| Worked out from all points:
|   GND clamp passes 1 mA (typ) near -0.51 V on its own axis
|   POWER clamp passes 1 mA (typ) near -0.64 V on its own axis
[GND_clamp]
| voltage   I(typ)   I(min)   I(max)
-3.3V     -1.286A    -1.273A    -1.289A
-1.2V     -163.3mA   -206.7mA   -148.3mA
-1.1V     -115.2mA   -159.6mA   -101mA
-1V       -71.04mA   -114.2mA   -60.78mA
-900mV    -36.42mA   -71.86mA   -36.53mA
-800mV    -18.72mA   -35.86mA   -23.84mA
-700mV    -9.715mA   -12.62mA   -13.63mA
-600mV    -3.608mA   -3.649mA   -5.602mA
-500mV    -692.7uA   -854.2uA   -1.156mA
-400mV    -68.48uA   -138.7uA   -98.54uA
-300mV    -4.365uA   -16.73uA   -4.626uA
3.3V      1.106nA    1.475uA    37.54nA
[POWER_clamp]
| voltage   I(typ)   I(min)   I(max)
-3.3V     276.4mA    201.2mA    346.2mA
-1.2V     38.21mA    32.25mA    46.01mA
-1.1V     28.13mA    25.27mA    33mA
-1V       18.72mA    18.66mA    21.02mA
-900mV    10.37mA    12.52mA    11.04mA
-800mV    4.3mA      7.057mA    5.343mA
-700mV    1.647mA    2.774mA    2.48mA
-600mV    473.1uA    621.1uA    767.7uA
-500mV    71.72uA    106uA      114.9uA
-400mV    5.96uA     14.29uA    7.91uA
0V        1.106nA    16.88nA    756.7pA
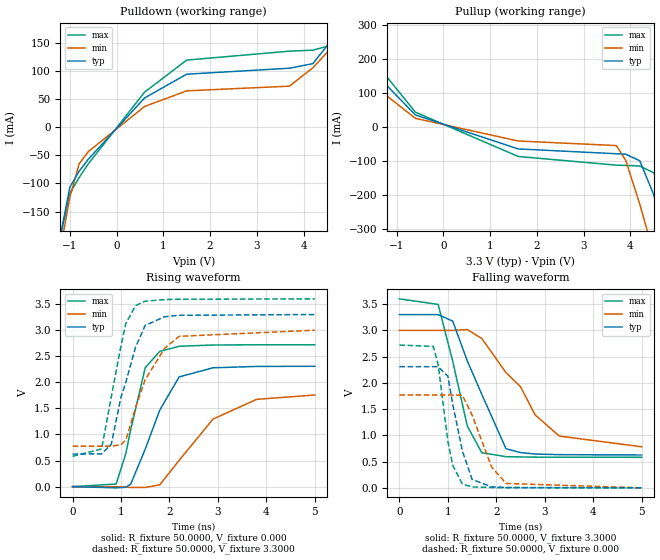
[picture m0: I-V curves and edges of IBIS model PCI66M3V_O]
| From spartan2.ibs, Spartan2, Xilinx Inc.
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|   Model PCI66M3V_O
[Model]   PCI66M3V_O
Model_type   Output
Polarity   Non-Inverting
| Vmeas depends on rising or falling edge, select one of the following:
| For rising edge:
|Vmeas =   0.940V
| For falling edge:
|Vmeas =   2.00V
Cref =  10.0000pF
Rref =  25.0000
| Vref depends on rising or falling edge, select one of the following:
| For rising edge:
|Vref =   0.00V
| For falling edge:
|Vref =   3.30V
C_comp   6.5000pF   5.0000pF   8.0000pF
[Temperature Range]   27.0000   100.0000   0.000
[Voltage Range]   3.3000V   3.0000V   3.6000V
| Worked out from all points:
|   slope of the pulldown table from 0 to 0.495 V, typ, clamps not added: 11.3 ohm
|   slope of the pullup table from 0 to 0.495 V, typ, clamps not added: 19.4 ohm
|   rising waveform, R_fixture 50.0000, V_fixture 0.000: 20-80 % time 614ps typ, 1.01ns min, 393ps max; typ from 0 V to 2.31 V
|   rising waveform, R_fixture 50.0000, V_fixture 3.3000: 20-80 % time 463ps typ, 605ps min, 370ps max; typ from 0.625 V to 3.3 V
|   falling waveform, R_fixture 50.0000, V_fixture 3.3000: 20-80 % time 657ps typ, 1.06ns min, 443ps max; typ from 3.3 V to 0.626 V
|   falling waveform, R_fixture 50.0000, V_fixture 0.000: 20-80 % time 311ps typ, 443ps min, 255ps max; typ from 2.31 V to 0 V
[Pulldown]
| voltage   I(typ)   I(min)   I(max)
-3.3V     -1.282A    -1.27A     -1.284A
-1.5V     -320.5mA   -355mA     -308.6mA
-1V       -107.1mA   -125mA     -118mA
-800mV    -78.31mA   -65.17mA   -89.55mA
-600mV    -56.71mA   -43.28mA   -64.84mA
600mV     51.72mA    36.54mA    62.03mA
1.5V      93.89mA    64.31mA    118.9mA
3.7V      104.5mA    72.65mA    134.8mA
4.2V      112.6mA    105.3mA    136.5mA
4.5V      143.9mA    132.2mA    143.3mA
4.9V      194.6mA    171.6mA    196.4mA
6.6V      424.6mA    347.8mA    474.2mA
[Pullup]
| voltage   I(typ)   I(min)   I(max)
-3.3V     423.8mA    325.6mA    510mA
-2.9V     366mA      280.2mA    440.1mA
-2.3V     275.3mA    208.6mA    331.8mA
-600mV    35.56mA    25.59mA    43.66mA
1.6V      -64.04mA   -40.84mA   -86.17mA
3.7V      -78.19mA   -54.2mA    -111.6mA
3.9V      -79.49mA   -97.57mA   -112.4mA
4.2V      -98.59mA   -225.3mA   -114.1mA
4.5V      -198.1mA   -370.5mA   -134mA
4.9V      -397.4mA   -571.2mA   -249.8mA
5.1V      -502.7mA   -672.9mA   -347.5mA
6.6V      -1.313A    -1.445A    -1.162A
[Ramp]
| variable   typ   min   max
dV/dt_r   1.3842/0.5892n   1.0536/0.9837n   1.6314/0.4116n
dV/dt_f   1.6045/0.6538n   1.3302/1.0576n   1.8107/0.4642n
R_load = 50.0000
[Rising Waveform]
R_fixture = 50.0000
V_fixture = 0.000
| time   V(typ)   V(min)   V(max)
0s        0V         0V         0V
900ps     -23.32mV   -820.2uV   49.8mV
1.1ns     -12.15mV   -8.63mV    637mV
1.2ns     46.42mV    -15.6mV    1.089V
1.5ns     718.7mV    -15.43mV   2.279V
1.8ns     1.466V     34.58mV    2.592V
2.2ns     2.103V     503.5mV    2.691V
2.9ns     2.278V     1.295V     2.714V
3.8ns     2.304V     1.673V     2.719V
5ns       2.307V     1.756V     2.719V
[Rising Waveform]
R_fixture = 50.0000
V_fixture = 3.3000
V_fixture_min = 3.0000
V_fixture_max = 3.6000
| time   V(typ)   V(min)   V(max)
0s        625mV      774mV      581.5mV
600ps     628.7mV    774.5mV    722.1mV
800ps     815.5mV    774.5mV    1.727V
1ns       1.718V     803.7mV    2.701V
1.1ns     2.001V     891.7mV    3.127V
1.3ns     2.673V     1.513V     3.47V
1.5ns     3.091V     2.052V     3.555V
1.9ns     3.256V     2.651V     3.585V
2.2ns     3.284V     2.881V     3.592V
5ns       3.299V     2.998V     3.599V
[Falling Waveform]
R_fixture = 50.0000
V_fixture = 3.3000
V_fixture_min = 3.0000
V_fixture_max = 3.6000
| time   V(typ)   V(min)   V(max)
0s        3.3V       3V         3.6V
800ps     3.3V       3V         3.494V
1.1ns     3.176V     2.999V     2.412V
1.4ns     2.42V      3.016V     1.181V
1.7ns     1.782V     2.846V     669mV
2.2ns     744.7mV    2.195V     594.4mV
2.5ns     672.6mV    1.926V     589mV
2.8ns     644.5mV    1.392V     585.4mV
3.3ns     632.9mV    986.5mV    583.5mV
5ns       625.9mV    783mV      582.1mV
[Falling Waveform]
R_fixture = 50.0000
V_fixture = 0.000
| time   V(typ)   V(min)   V(max)
0s        2.309V     1.768V     2.72V
700ps     2.308V     1.768V     2.694V
800ps     2.308V     1.768V     2.343V
1ns       2.127V     1.768V     884.1mV
1.1ns     1.594V     1.768V     431.3mV
1.3ns     703.4mV    1.763V     72.39mV
1.5ns     161.6mV    1.388V     17.8mV
1.9ns     18.79mV    401.6mV    7.082mV
2.2ns     7.082mV    84.24mV    3.793mV
5ns       411.1uV    614uV      381.3uV
